VERSION 5.7 ;
  NOWIREEXTENSIONATPIN ON ;
  DIVIDERCHAR "/" ;
  BUSBITCHARS "[]" ;
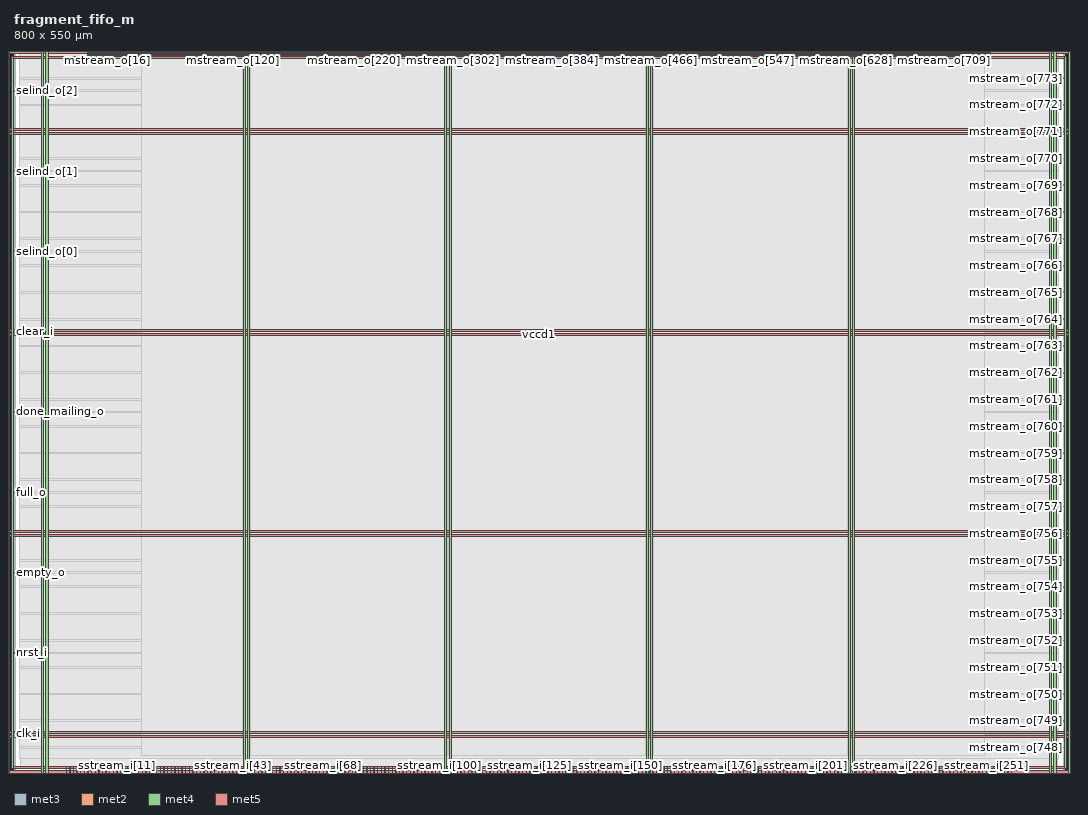
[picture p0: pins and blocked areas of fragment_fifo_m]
MACRO fragment_fifo_m
  CLASS BLOCK ;
  FOREIGN fragment_fifo_m ;
  ORIGIN 0.000 0.000 ;
  SIZE 800.000 BY 550.000 ;
  PIN clear_i
    DIRECTION INPUT ;
    USE SIGNAL ;
    ANTENNAGATEAREA 0.159000 ;
    PORT
      LAYER met3 ;
        RECT 0.000 335.960 4.000 336.560 ;
    END
  END clear_i
  PIN clk_i
    DIRECTION INPUT ;
    USE SIGNAL ;
    ANTENNAGATEAREA 0.852000 ;
    PORT
      LAYER met3 ;
        RECT 0.000 29.960 4.000 30.560 ;
    END
  END clk_i
  PIN done_mailing_o
    DIRECTION OUTPUT TRISTATE ;
    USE SIGNAL ;
    ANTENNADIFFAREA 0.795200 ;
    PORT
      LAYER met3 ;
        RECT 0.000 274.760 4.000 275.360 ;
    END
  END done_mailing_o
  PIN empty_o
    DIRECTION OUTPUT TRISTATE ;
    USE SIGNAL ;
    ANTENNADIFFAREA 0.795200 ;
    PORT
      LAYER met3 ;
        RECT 0.000 152.360 4.000 152.960 ;
    END
  END empty_o
  PIN full_o
    DIRECTION OUTPUT TRISTATE ;
    USE SIGNAL ;
    ANTENNADIFFAREA 0.795200 ;
    PORT
      LAYER met3 ;
        RECT 0.000 213.560 4.000 214.160 ;
    END
  END full_o
  PIN mstream_i[0]
    DIRECTION INPUT ;
    USE SIGNAL ;
    ANTENNAGATEAREA 0.159000 ;
    PORT
      LAYER met2 ;
        RECT 39.650 0.000 39.930 4.000 ;
    END
  END mstream_i[0]
  PIN mstream_i[1]
    DIRECTION INPUT ;
    USE SIGNAL ;
    ANTENNAGATEAREA 0.213000 ;
    PORT
      LAYER met2 ;
        RECT 42.410 0.000 42.690 4.000 ;
    END
  END mstream_i[1]
  PIN mstream_i[2]
    DIRECTION INPUT ;
    USE SIGNAL ;
    ANTENNAGATEAREA 0.213000 ;
    PORT
      LAYER met2 ;
        RECT 45.170 0.000 45.450 4.000 ;
    END
  END mstream_i[2]
  PIN mstream_o[0]
    DIRECTION OUTPUT TRISTATE ;
    USE SIGNAL ;
    ANTENNADIFFAREA 0.795200 ;
    PORT
      LAYER met2 ;
        RECT 56.210 546.000 56.490 550.000 ;
    END
  END mstream_o[0]
  PIN mstream_o[100]
    DIRECTION OUTPUT TRISTATE ;
    USE SIGNAL ;
    ANTENNADIFFAREA 0.795200 ;
    PORT
      LAYER met2 ;
        RECT 148.210 546.000 148.490 550.000 ;
    END
  END mstream_o[100]
  PIN mstream_o[101]
    DIRECTION OUTPUT TRISTATE ;
    USE SIGNAL ;
    ANTENNADIFFAREA 0.795200 ;
    PORT
      LAYER met2 ;
        RECT 149.130 546.000 149.410 550.000 ;
    END
  END mstream_o[101]
  PIN mstream_o[102]
    DIRECTION OUTPUT TRISTATE ;
    USE SIGNAL ;
    ANTENNADIFFAREA 0.795200 ;
    PORT
      LAYER met2 ;
        RECT 150.050 546.000 150.330 550.000 ;
    END
  END mstream_o[102]
  PIN mstream_o[103]
    DIRECTION OUTPUT TRISTATE ;
    USE SIGNAL ;
    ANTENNADIFFAREA 0.795200 ;
    PORT
      LAYER met2 ;
        RECT 150.970 546.000 151.250 550.000 ;
    END
  END mstream_o[103]
  PIN mstream_o[104]
    DIRECTION OUTPUT TRISTATE ;
    USE SIGNAL ;
    ANTENNADIFFAREA 0.795200 ;
    PORT
      LAYER met2 ;
        RECT 151.890 546.000 152.170 550.000 ;
    END
  END mstream_o[104]
  PIN mstream_o[105]
    DIRECTION OUTPUT TRISTATE ;
    USE SIGNAL ;
    ANTENNADIFFAREA 0.795200 ;
    PORT
      LAYER met2 ;
        RECT 152.810 546.000 153.090 550.000 ;
    END
  END mstream_o[105]
  PIN mstream_o[106]
    DIRECTION OUTPUT TRISTATE ;
    USE SIGNAL ;
    ANTENNADIFFAREA 0.795200 ;
    PORT
      LAYER met2 ;
        RECT 153.730 546.000 154.010 550.000 ;
    END
  END mstream_o[106]
  PIN mstream_o[107]
    DIRECTION OUTPUT TRISTATE ;
    USE SIGNAL ;
    ANTENNADIFFAREA 0.795200 ;
    PORT
      LAYER met2 ;
        RECT 154.650 546.000 154.930 550.000 ;
    END
  END mstream_o[107]
  PIN mstream_o[108]
    DIRECTION OUTPUT TRISTATE ;
    USE SIGNAL ;
    ANTENNADIFFAREA 0.795200 ;
    PORT
      LAYER met2 ;
        RECT 155.570 546.000 155.850 550.000 ;
    END
  END mstream_o[108]
  PIN mstream_o[109]
    DIRECTION OUTPUT TRISTATE ;
    USE SIGNAL ;
    ANTENNADIFFAREA 0.795200 ;
    PORT
      LAYER met2 ;
        RECT 156.490 546.000 156.770 550.000 ;
    END
  END mstream_o[109]
  PIN mstream_o[10]
    DIRECTION OUTPUT TRISTATE ;
    USE SIGNAL ;
    ANTENNADIFFAREA 0.795200 ;
    PORT
      LAYER met2 ;
        RECT 65.410 546.000 65.690 550.000 ;
    END
  END mstream_o[10]
  PIN mstream_o[110]
    DIRECTION OUTPUT TRISTATE ;
    USE SIGNAL ;
    ANTENNADIFFAREA 0.795200 ;
    PORT
      LAYER met2 ;
        RECT 157.410 546.000 157.690 550.000 ;
    END
  END mstream_o[110]
  PIN mstream_o[111]
    DIRECTION OUTPUT TRISTATE ;
    USE SIGNAL ;
    ANTENNADIFFAREA 0.795200 ;
    PORT
      LAYER met2 ;
        RECT 158.330 546.000 158.610 550.000 ;
    END
  END mstream_o[111]
  PIN mstream_o[112]
    DIRECTION OUTPUT TRISTATE ;
    USE SIGNAL ;
    ANTENNADIFFAREA 0.795200 ;
    PORT
      LAYER met2 ;
        RECT 159.250 546.000 159.530 550.000 ;
    END
  END mstream_o[112]
  PIN mstream_o[113]
    DIRECTION OUTPUT TRISTATE ;
    USE SIGNAL ;
    ANTENNADIFFAREA 0.795200 ;
    PORT
      LAYER met2 ;
        RECT 160.170 546.000 160.450 550.000 ;
    END
  END mstream_o[113]
  PIN mstream_o[114]
    DIRECTION OUTPUT TRISTATE ;
    USE SIGNAL ;
    ANTENNADIFFAREA 0.795200 ;
    PORT
      LAYER met2 ;
        RECT 161.090 546.000 161.370 550.000 ;
    END
  END mstream_o[114]
  PIN mstream_o[115]
    DIRECTION OUTPUT TRISTATE ;
    USE SIGNAL ;
    ANTENNADIFFAREA 0.795200 ;
    PORT
      LAYER met2 ;
        RECT 162.010 546.000 162.290 550.000 ;
    END
  END mstream_o[115]
  PIN mstream_o[116]
    DIRECTION OUTPUT TRISTATE ;
    USE SIGNAL ;
    ANTENNADIFFAREA 0.795200 ;
    PORT
      LAYER met2 ;
        RECT 162.930 546.000 163.210 550.000 ;
    END
  END mstream_o[116]
  PIN mstream_o[117]
    DIRECTION OUTPUT TRISTATE ;
    USE SIGNAL ;
    ANTENNADIFFAREA 0.795200 ;
    PORT
      LAYER met2 ;
        RECT 163.850 546.000 164.130 550.000 ;
    END
  END mstream_o[117]
  PIN mstream_o[118]
    DIRECTION OUTPUT TRISTATE ;
    USE SIGNAL ;
    ANTENNADIFFAREA 0.795200 ;
    PORT
      LAYER met2 ;
        RECT 164.770 546.000 165.050 550.000 ;
    END
  END mstream_o[118]
  PIN mstream_o[119]
    DIRECTION OUTPUT TRISTATE ;
    USE SIGNAL ;
    ANTENNADIFFAREA 0.795200 ;
    PORT
      LAYER met2 ;
        RECT 165.690 546.000 165.970 550.000 ;
    END
  END mstream_o[119]
  PIN mstream_o[11]
    DIRECTION OUTPUT TRISTATE ;
    USE SIGNAL ;
    ANTENNADIFFAREA 0.795200 ;
    PORT
      LAYER met2 ;
        RECT 66.330 546.000 66.610 550.000 ;
    END
  END mstream_o[11]
  PIN mstream_o[120]
    DIRECTION OUTPUT TRISTATE ;
    USE SIGNAL ;
    ANTENNADIFFAREA 0.795200 ;
    PORT
      LAYER met2 ;
        RECT 166.610 546.000 166.890 550.000 ;
    END
  END mstream_o[120]
  PIN mstream_o[121]
    DIRECTION OUTPUT TRISTATE ;
    USE SIGNAL ;
    ANTENNADIFFAREA 0.795200 ;
    PORT
      LAYER met2 ;
        RECT 167.530 546.000 167.810 550.000 ;
    END
  END mstream_o[121]
  PIN mstream_o[122]
    DIRECTION OUTPUT TRISTATE ;
    USE SIGNAL ;
    ANTENNADIFFAREA 0.795200 ;
    PORT
      LAYER met2 ;
        RECT 168.450 546.000 168.730 550.000 ;
    END
  END mstream_o[122]
  PIN mstream_o[123]
    DIRECTION OUTPUT TRISTATE ;
    USE SIGNAL ;
    ANTENNADIFFAREA 0.795200 ;
    PORT
      LAYER met2 ;
        RECT 169.370 546.000 169.650 550.000 ;
    END
  END mstream_o[123]
  PIN mstream_o[124]
    DIRECTION OUTPUT TRISTATE ;
    USE SIGNAL ;
    ANTENNADIFFAREA 0.795200 ;
    PORT
      LAYER met2 ;
        RECT 170.290 546.000 170.570 550.000 ;
    END
  END mstream_o[124]
  PIN mstream_o[125]
    DIRECTION OUTPUT TRISTATE ;
    USE SIGNAL ;
    ANTENNADIFFAREA 0.795200 ;
    PORT
      LAYER met2 ;
        RECT 171.210 546.000 171.490 550.000 ;
    END
  END mstream_o[125]
  PIN mstream_o[126]
    DIRECTION OUTPUT TRISTATE ;
    USE SIGNAL ;
    ANTENNADIFFAREA 0.795200 ;
    PORT
      LAYER met2 ;
        RECT 172.130 546.000 172.410 550.000 ;
    END
  END mstream_o[126]
  PIN mstream_o[127]
    DIRECTION OUTPUT TRISTATE ;
    USE SIGNAL ;
    ANTENNADIFFAREA 0.795200 ;
    PORT
      LAYER met2 ;
        RECT 173.050 546.000 173.330 550.000 ;
    END
  END mstream_o[127]
  PIN mstream_o[128]
    DIRECTION OUTPUT TRISTATE ;
    USE SIGNAL ;
    ANTENNADIFFAREA 0.795200 ;
    PORT
      LAYER met2 ;
        RECT 173.970 546.000 174.250 550.000 ;
    END
  END mstream_o[128]
  PIN mstream_o[129]
    DIRECTION OUTPUT TRISTATE ;
    USE SIGNAL ;
    ANTENNADIFFAREA 0.795200 ;
    PORT
      LAYER met2 ;
        RECT 174.890 546.000 175.170 550.000 ;
    END
  END mstream_o[129]
  PIN mstream_o[12]
    DIRECTION OUTPUT TRISTATE ;
    USE SIGNAL ;
    ANTENNADIFFAREA 0.795200 ;
    PORT
      LAYER met2 ;
        RECT 67.250 546.000 67.530 550.000 ;
    END
  END mstream_o[12]
  PIN mstream_o[130]
    DIRECTION OUTPUT TRISTATE ;
    USE SIGNAL ;
    ANTENNADIFFAREA 0.795200 ;
    PORT
      LAYER met2 ;
        RECT 175.810 546.000 176.090 550.000 ;
    END
  END mstream_o[130]
  PIN mstream_o[131]
    DIRECTION OUTPUT TRISTATE ;
    USE SIGNAL ;
    ANTENNADIFFAREA 0.795200 ;
    PORT
      LAYER met2 ;
        RECT 176.730 546.000 177.010 550.000 ;
    END
  END mstream_o[131]
  PIN mstream_o[132]
    DIRECTION OUTPUT TRISTATE ;
    USE SIGNAL ;
    ANTENNADIFFAREA 0.795200 ;
    PORT
      LAYER met2 ;
        RECT 177.650 546.000 177.930 550.000 ;
    END
  END mstream_o[132]
  PIN mstream_o[133]
    DIRECTION OUTPUT TRISTATE ;
    USE SIGNAL ;
    ANTENNADIFFAREA 0.795200 ;
    PORT
      LAYER met2 ;
        RECT 178.570 546.000 178.850 550.000 ;
    END
  END mstream_o[133]
  PIN mstream_o[134]
    DIRECTION OUTPUT TRISTATE ;
    USE SIGNAL ;
    ANTENNADIFFAREA 0.795200 ;
    PORT
      LAYER met2 ;
        RECT 179.490 546.000 179.770 550.000 ;
    END
  END mstream_o[134]
  PIN mstream_o[135]
    DIRECTION OUTPUT TRISTATE ;
    USE SIGNAL ;
    ANTENNADIFFAREA 0.795200 ;
    PORT
      LAYER met2 ;
        RECT 180.410 546.000 180.690 550.000 ;
    END
  END mstream_o[135]
  PIN mstream_o[136]
    DIRECTION OUTPUT TRISTATE ;
    USE SIGNAL ;
    ANTENNADIFFAREA 0.795200 ;
    PORT
      LAYER met2 ;
        RECT 181.330 546.000 181.610 550.000 ;
    END
  END mstream_o[136]
  PIN mstream_o[137]
    DIRECTION OUTPUT TRISTATE ;
    USE SIGNAL ;
    ANTENNADIFFAREA 0.795200 ;
    PORT
      LAYER met2 ;
        RECT 182.250 546.000 182.530 550.000 ;
    END
  END mstream_o[137]
  PIN mstream_o[138]
    DIRECTION OUTPUT TRISTATE ;
    USE SIGNAL ;
    ANTENNADIFFAREA 0.795200 ;
    PORT
      LAYER met2 ;
        RECT 183.170 546.000 183.450 550.000 ;
    END
  END mstream_o[138]
  PIN mstream_o[139]
    DIRECTION OUTPUT TRISTATE ;
    USE SIGNAL ;
    ANTENNADIFFAREA 0.795200 ;
    PORT
      LAYER met2 ;
        RECT 184.090 546.000 184.370 550.000 ;
    END
  END mstream_o[139]
  PIN mstream_o[13]
    DIRECTION OUTPUT TRISTATE ;
    USE SIGNAL ;
    ANTENNADIFFAREA 0.795200 ;
    PORT
      LAYER met2 ;
        RECT 68.170 546.000 68.450 550.000 ;
    END
  END mstream_o[13]
  PIN mstream_o[140]
    DIRECTION OUTPUT TRISTATE ;
    USE SIGNAL ;
    ANTENNADIFFAREA 0.795200 ;
    PORT
      LAYER met2 ;
        RECT 185.010 546.000 185.290 550.000 ;
    END
  END mstream_o[140]
  PIN mstream_o[141]
    DIRECTION OUTPUT TRISTATE ;
    USE SIGNAL ;
    ANTENNADIFFAREA 0.795200 ;
    PORT
      LAYER met2 ;
        RECT 185.930 546.000 186.210 550.000 ;
    END
  END mstream_o[141]
  PIN mstream_o[142]
    DIRECTION OUTPUT TRISTATE ;
    USE SIGNAL ;
    ANTENNADIFFAREA 0.795200 ;
    PORT
      LAYER met2 ;
        RECT 186.850 546.000 187.130 550.000 ;
    END
  END mstream_o[142]
  PIN mstream_o[143]
    DIRECTION OUTPUT TRISTATE ;
    USE SIGNAL ;
    ANTENNADIFFAREA 0.795200 ;
    PORT
      LAYER met2 ;
        RECT 187.770 546.000 188.050 550.000 ;
    END
  END mstream_o[143]
  PIN mstream_o[144]
    DIRECTION OUTPUT TRISTATE ;
    USE SIGNAL ;
    ANTENNADIFFAREA 0.795200 ;
    PORT
      LAYER met2 ;
        RECT 188.690 546.000 188.970 550.000 ;
    END
  END mstream_o[144]
  PIN mstream_o[145]
    DIRECTION OUTPUT TRISTATE ;
    USE SIGNAL ;
    ANTENNADIFFAREA 0.795200 ;
    PORT
      LAYER met2 ;
        RECT 189.610 546.000 189.890 550.000 ;
    END
  END mstream_o[145]
  PIN mstream_o[146]
    DIRECTION OUTPUT TRISTATE ;
    USE SIGNAL ;
    ANTENNADIFFAREA 0.795200 ;
    PORT
      LAYER met2 ;
        RECT 190.530 546.000 190.810 550.000 ;
    END
  END mstream_o[146]
  PIN mstream_o[147]
    DIRECTION OUTPUT TRISTATE ;
    USE SIGNAL ;
    ANTENNADIFFAREA 0.795200 ;
    PORT
      LAYER met2 ;
        RECT 191.450 546.000 191.730 550.000 ;
    END
  END mstream_o[147]
  PIN mstream_o[148]
    DIRECTION OUTPUT TRISTATE ;
    USE SIGNAL ;
    ANTENNADIFFAREA 0.795200 ;
    PORT
      LAYER met2 ;
        RECT 192.370 546.000 192.650 550.000 ;
    END
  END mstream_o[148]
  PIN mstream_o[149]
    DIRECTION OUTPUT TRISTATE ;
    USE SIGNAL ;
    ANTENNADIFFAREA 0.795200 ;
    PORT
      LAYER met2 ;
        RECT 193.290 546.000 193.570 550.000 ;
    END
  END mstream_o[149]
  PIN mstream_o[14]
    DIRECTION OUTPUT TRISTATE ;
    USE SIGNAL ;
    ANTENNADIFFAREA 0.795200 ;
    PORT
      LAYER met2 ;
        RECT 69.090 546.000 69.370 550.000 ;
    END
  END mstream_o[14]
  PIN mstream_o[150]
    DIRECTION OUTPUT TRISTATE ;
    USE SIGNAL ;
    ANTENNADIFFAREA 0.795200 ;
    PORT
      LAYER met2 ;
        RECT 194.210 546.000 194.490 550.000 ;
    END
  END mstream_o[150]
  PIN mstream_o[151]
    DIRECTION OUTPUT TRISTATE ;
    USE SIGNAL ;
    ANTENNADIFFAREA 0.795200 ;
    PORT
      LAYER met2 ;
        RECT 195.130 546.000 195.410 550.000 ;
    END
  END mstream_o[151]
  PIN mstream_o[152]
    DIRECTION OUTPUT TRISTATE ;
    USE SIGNAL ;
    ANTENNADIFFAREA 0.795200 ;
    PORT
      LAYER met2 ;
        RECT 196.050 546.000 196.330 550.000 ;
    END
  END mstream_o[152]
  PIN mstream_o[153]
    DIRECTION OUTPUT TRISTATE ;
    USE SIGNAL ;
    ANTENNADIFFAREA 0.795200 ;
    PORT
      LAYER met2 ;
        RECT 196.970 546.000 197.250 550.000 ;
    END
  END mstream_o[153]
  PIN mstream_o[154]
    DIRECTION OUTPUT TRISTATE ;
    USE SIGNAL ;
    ANTENNADIFFAREA 0.795200 ;
    PORT
      LAYER met2 ;
        RECT 197.890 546.000 198.170 550.000 ;
    END
  END mstream_o[154]
  PIN mstream_o[155]
    DIRECTION OUTPUT TRISTATE ;
    USE SIGNAL ;
    ANTENNADIFFAREA 0.795200 ;
    PORT
      LAYER met2 ;
        RECT 198.810 546.000 199.090 550.000 ;
    END
  END mstream_o[155]
  PIN mstream_o[156]
    DIRECTION OUTPUT TRISTATE ;
    USE SIGNAL ;
    ANTENNADIFFAREA 0.795200 ;
    PORT
      LAYER met2 ;
        RECT 199.730 546.000 200.010 550.000 ;
    END
  END mstream_o[156]
  PIN mstream_o[157]
    DIRECTION OUTPUT TRISTATE ;
    USE SIGNAL ;
    ANTENNADIFFAREA 0.795200 ;
    PORT
      LAYER met2 ;
        RECT 200.650 546.000 200.930 550.000 ;
    END
  END mstream_o[157]
  PIN mstream_o[158]
    DIRECTION OUTPUT TRISTATE ;
    USE SIGNAL ;
    ANTENNADIFFAREA 0.795200 ;
    PORT
      LAYER met2 ;
        RECT 201.570 546.000 201.850 550.000 ;
    END
  END mstream_o[158]
  PIN mstream_o[159]
    DIRECTION OUTPUT TRISTATE ;
    USE SIGNAL ;
    ANTENNADIFFAREA 0.795200 ;
    PORT
      LAYER met2 ;
        RECT 202.490 546.000 202.770 550.000 ;
    END
  END mstream_o[159]
  PIN mstream_o[15]
    DIRECTION OUTPUT TRISTATE ;
    USE SIGNAL ;
    ANTENNADIFFAREA 0.795200 ;
    PORT
      LAYER met2 ;
        RECT 70.010 546.000 70.290 550.000 ;
    END
  END mstream_o[15]
  PIN mstream_o[160]
    DIRECTION OUTPUT TRISTATE ;
    USE SIGNAL ;
    ANTENNADIFFAREA 0.795200 ;
    PORT
      LAYER met2 ;
        RECT 203.410 546.000 203.690 550.000 ;
    END
  END mstream_o[160]
  PIN mstream_o[161]
    DIRECTION OUTPUT TRISTATE ;
    USE SIGNAL ;
    ANTENNADIFFAREA 0.795200 ;
    PORT
      LAYER met2 ;
        RECT 204.330 546.000 204.610 550.000 ;
    END
  END mstream_o[161]
  PIN mstream_o[162]
    DIRECTION OUTPUT TRISTATE ;
    USE SIGNAL ;
    ANTENNADIFFAREA 0.795200 ;
    PORT
      LAYER met2 ;
        RECT 205.250 546.000 205.530 550.000 ;
    END
  END mstream_o[162]
  PIN mstream_o[163]
    DIRECTION OUTPUT TRISTATE ;
    USE SIGNAL ;
    ANTENNADIFFAREA 0.795200 ;
    PORT
      LAYER met2 ;
        RECT 206.170 546.000 206.450 550.000 ;
    END
  END mstream_o[163]
  PIN mstream_o[164]
    DIRECTION OUTPUT TRISTATE ;
    USE SIGNAL ;
    ANTENNADIFFAREA 0.795200 ;
    PORT
      LAYER met2 ;
        RECT 207.090 546.000 207.370 550.000 ;
    END
  END mstream_o[164]
  PIN mstream_o[165]
    DIRECTION OUTPUT TRISTATE ;
    USE SIGNAL ;
    ANTENNADIFFAREA 0.795200 ;
    PORT
      LAYER met2 ;
        RECT 208.010 546.000 208.290 550.000 ;
    END
  END mstream_o[165]
  PIN mstream_o[166]
    DIRECTION OUTPUT TRISTATE ;
    USE SIGNAL ;
    ANTENNADIFFAREA 0.795200 ;
    PORT
      LAYER met2 ;
        RECT 208.930 546.000 209.210 550.000 ;
    END
  END mstream_o[166]
  PIN mstream_o[167]
    DIRECTION OUTPUT TRISTATE ;
    USE SIGNAL ;
    ANTENNADIFFAREA 0.795200 ;
    PORT
      LAYER met2 ;
        RECT 209.850 546.000 210.130 550.000 ;
    END
  END mstream_o[167]
  PIN mstream_o[168]
    DIRECTION OUTPUT TRISTATE ;
    USE SIGNAL ;
    ANTENNADIFFAREA 0.795200 ;
    PORT
      LAYER met2 ;
        RECT 210.770 546.000 211.050 550.000 ;
    END
  END mstream_o[168]
  PIN mstream_o[169]
    DIRECTION OUTPUT TRISTATE ;
    USE SIGNAL ;
    ANTENNADIFFAREA 0.795200 ;
    PORT
      LAYER met2 ;
        RECT 211.690 546.000 211.970 550.000 ;
    END
  END mstream_o[169]
  PIN mstream_o[16]
    DIRECTION OUTPUT TRISTATE ;
    USE SIGNAL ;
    ANTENNADIFFAREA 0.795200 ;
    PORT
      LAYER met2 ;
        RECT 70.930 546.000 71.210 550.000 ;
    END
  END mstream_o[16]
  PIN mstream_o[170]
    DIRECTION OUTPUT TRISTATE ;
    USE SIGNAL ;
    ANTENNADIFFAREA 0.795200 ;
    PORT
      LAYER met2 ;
        RECT 212.610 546.000 212.890 550.000 ;
    END
  END mstream_o[170]
  PIN mstream_o[171]
    DIRECTION OUTPUT TRISTATE ;
    USE SIGNAL ;
    ANTENNADIFFAREA 0.795200 ;
    PORT
      LAYER met2 ;
        RECT 213.530 546.000 213.810 550.000 ;
    END
  END mstream_o[171]
  PIN mstream_o[172]
    DIRECTION OUTPUT TRISTATE ;
    USE SIGNAL ;
    ANTENNADIFFAREA 0.795200 ;
    PORT
      LAYER met2 ;
        RECT 214.450 546.000 214.730 550.000 ;
    END
  END mstream_o[172]
  PIN mstream_o[173]
    DIRECTION OUTPUT TRISTATE ;
    USE SIGNAL ;
    ANTENNADIFFAREA 0.795200 ;
    PORT
      LAYER met2 ;
        RECT 215.370 546.000 215.650 550.000 ;
    END
  END mstream_o[173]
  PIN mstream_o[174]
    DIRECTION OUTPUT TRISTATE ;
    USE SIGNAL ;
    ANTENNADIFFAREA 0.795200 ;
    PORT
      LAYER met2 ;
        RECT 216.290 546.000 216.570 550.000 ;
    END
  END mstream_o[174]
  PIN mstream_o[175]
    DIRECTION OUTPUT TRISTATE ;
    USE SIGNAL ;
    ANTENNADIFFAREA 0.795200 ;
    PORT
      LAYER met2 ;
        RECT 217.210 546.000 217.490 550.000 ;
    END
  END mstream_o[175]
  PIN mstream_o[176]
    DIRECTION OUTPUT TRISTATE ;
    USE SIGNAL ;
    ANTENNADIFFAREA 0.795200 ;
    PORT
      LAYER met2 ;
        RECT 218.130 546.000 218.410 550.000 ;
    END
  END mstream_o[176]
  PIN mstream_o[177]
    DIRECTION OUTPUT TRISTATE ;
    USE SIGNAL ;
    ANTENNADIFFAREA 0.795200 ;
    PORT
      LAYER met2 ;
        RECT 219.050 546.000 219.330 550.000 ;
    END
  END mstream_o[177]
  PIN mstream_o[178]
    DIRECTION OUTPUT TRISTATE ;
    USE SIGNAL ;
    ANTENNADIFFAREA 0.795200 ;
    PORT
      LAYER met2 ;
        RECT 219.970 546.000 220.250 550.000 ;
    END
  END mstream_o[178]
  PIN mstream_o[179]
    DIRECTION OUTPUT TRISTATE ;
    USE SIGNAL ;
    ANTENNADIFFAREA 0.795200 ;
    PORT
      LAYER met2 ;
        RECT 220.890 546.000 221.170 550.000 ;
    END
  END mstream_o[179]
  PIN mstream_o[17]
    DIRECTION OUTPUT TRISTATE ;
    USE SIGNAL ;
    ANTENNADIFFAREA 0.795200 ;
    PORT
      LAYER met2 ;
        RECT 71.850 546.000 72.130 550.000 ;
    END
  END mstream_o[17]
  PIN mstream_o[180]
    DIRECTION OUTPUT TRISTATE ;
    USE SIGNAL ;
    ANTENNADIFFAREA 0.795200 ;
    PORT
      LAYER met2 ;
        RECT 221.810 546.000 222.090 550.000 ;
    END
  END mstream_o[180]
  PIN mstream_o[181]
    DIRECTION OUTPUT TRISTATE ;
    USE SIGNAL ;
    ANTENNADIFFAREA 0.795200 ;
    PORT
      LAYER met2 ;
        RECT 222.730 546.000 223.010 550.000 ;
    END
  END mstream_o[181]
  PIN mstream_o[182]
    DIRECTION OUTPUT TRISTATE ;
    USE SIGNAL ;
    ANTENNADIFFAREA 0.795200 ;
    PORT
      LAYER met2 ;
        RECT 223.650 546.000 223.930 550.000 ;
    END
  END mstream_o[182]
  PIN mstream_o[183]
    DIRECTION OUTPUT TRISTATE ;
    USE SIGNAL ;
    ANTENNADIFFAREA 0.795200 ;
    PORT
      LAYER met2 ;
        RECT 224.570 546.000 224.850 550.000 ;
    END
  END mstream_o[183]
  PIN mstream_o[184]
    DIRECTION OUTPUT TRISTATE ;
    USE SIGNAL ;
    ANTENNADIFFAREA 0.795200 ;
    PORT
      LAYER met2 ;
        RECT 225.490 546.000 225.770 550.000 ;
    END
  END mstream_o[184]
  PIN mstream_o[185]
    DIRECTION OUTPUT TRISTATE ;
    USE SIGNAL ;
    ANTENNADIFFAREA 0.795200 ;
    PORT
      LAYER met2 ;
        RECT 226.410 546.000 226.690 550.000 ;
    END
  END mstream_o[185]
  PIN mstream_o[186]
    DIRECTION OUTPUT TRISTATE ;
    USE SIGNAL ;
    ANTENNADIFFAREA 0.795200 ;
    PORT
      LAYER met2 ;
        RECT 227.330 546.000 227.610 550.000 ;
    END
  END mstream_o[186]
  PIN mstream_o[187]
    DIRECTION OUTPUT TRISTATE ;
    USE SIGNAL ;
    ANTENNADIFFAREA 0.795200 ;
    PORT
      LAYER met2 ;
        RECT 228.250 546.000 228.530 550.000 ;
    END
  END mstream_o[187]
  PIN mstream_o[188]
    DIRECTION OUTPUT TRISTATE ;
    USE SIGNAL ;
    ANTENNADIFFAREA 0.795200 ;
    PORT
      LAYER met2 ;
        RECT 229.170 546.000 229.450 550.000 ;
    END
  END mstream_o[188]
  PIN mstream_o[189]
    DIRECTION OUTPUT TRISTATE ;
    USE SIGNAL ;
    ANTENNADIFFAREA 0.795200 ;
    PORT
      LAYER met2 ;
        RECT 230.090 546.000 230.370 550.000 ;
    END
  END mstream_o[189]
  PIN mstream_o[18]
    DIRECTION OUTPUT TRISTATE ;
    USE SIGNAL ;
    ANTENNADIFFAREA 0.795200 ;
    PORT
      LAYER met2 ;
        RECT 72.770 546.000 73.050 550.000 ;
    END
  END mstream_o[18]
  PIN mstream_o[190]
    DIRECTION OUTPUT TRISTATE ;
    USE SIGNAL ;
    ANTENNADIFFAREA 0.795200 ;
    PORT
      LAYER met2 ;
        RECT 231.010 546.000 231.290 550.000 ;
    END
  END mstream_o[190]
  PIN mstream_o[191]
    DIRECTION OUTPUT TRISTATE ;
    USE SIGNAL ;
    ANTENNADIFFAREA 0.795200 ;
    PORT
      LAYER met2 ;
        RECT 231.930 546.000 232.210 550.000 ;
    END
  END mstream_o[191]
  PIN mstream_o[192]
    DIRECTION OUTPUT TRISTATE ;
    USE SIGNAL ;
    ANTENNADIFFAREA 0.795200 ;
    PORT
      LAYER met2 ;
        RECT 232.850 546.000 233.130 550.000 ;
    END
  END mstream_o[192]
  PIN mstream_o[193]
    DIRECTION OUTPUT TRISTATE ;
    USE SIGNAL ;
    ANTENNADIFFAREA 0.795200 ;
    PORT
      LAYER met2 ;
        RECT 233.770 546.000 234.050 550.000 ;
    END
  END mstream_o[193]
  PIN mstream_o[194]
    DIRECTION OUTPUT TRISTATE ;
    USE SIGNAL ;
    ANTENNADIFFAREA 0.795200 ;
    PORT
      LAYER met2 ;
        RECT 234.690 546.000 234.970 550.000 ;
    END
  END mstream_o[194]
  PIN mstream_o[195]
    DIRECTION OUTPUT TRISTATE ;
    USE SIGNAL ;
    ANTENNADIFFAREA 0.795200 ;
    PORT
      LAYER met2 ;
        RECT 235.610 546.000 235.890 550.000 ;
    END
  END mstream_o[195]
  PIN mstream_o[196]
    DIRECTION OUTPUT TRISTATE ;
    USE SIGNAL ;
    ANTENNADIFFAREA 0.795200 ;
    PORT
      LAYER met2 ;
        RECT 236.530 546.000 236.810 550.000 ;
    END
  END mstream_o[196]
  PIN mstream_o[197]
    DIRECTION OUTPUT TRISTATE ;
    USE SIGNAL ;
    ANTENNADIFFAREA 0.795200 ;
    PORT
      LAYER met2 ;
        RECT 237.450 546.000 237.730 550.000 ;
    END
  END mstream_o[197]
  PIN mstream_o[198]
    DIRECTION OUTPUT TRISTATE ;
    USE SIGNAL ;
    ANTENNADIFFAREA 0.795200 ;
    PORT
      LAYER met2 ;
        RECT 238.370 546.000 238.650 550.000 ;
    END
  END mstream_o[198]
  PIN mstream_o[199]
    DIRECTION OUTPUT TRISTATE ;
    USE SIGNAL ;
    ANTENNADIFFAREA 0.795200 ;
    PORT
      LAYER met2 ;
        RECT 239.290 546.000 239.570 550.000 ;
    END
  END mstream_o[199]
  PIN mstream_o[19]
    DIRECTION OUTPUT TRISTATE ;
    USE SIGNAL ;
    ANTENNADIFFAREA 0.795200 ;
    PORT
      LAYER met2 ;
        RECT 73.690 546.000 73.970 550.000 ;
    END
  END mstream_o[19]
  PIN mstream_o[1]
    DIRECTION OUTPUT TRISTATE ;
    USE SIGNAL ;
    ANTENNADIFFAREA 0.795200 ;
    PORT
      LAYER met2 ;
        RECT 57.130 546.000 57.410 550.000 ;
    END
  END mstream_o[1]
  PIN mstream_o[200]
    DIRECTION OUTPUT TRISTATE ;
    USE SIGNAL ;
    ANTENNADIFFAREA 0.795200 ;
    PORT
      LAYER met2 ;
        RECT 240.210 546.000 240.490 550.000 ;
    END
  END mstream_o[200]
  PIN mstream_o[201]
    DIRECTION OUTPUT TRISTATE ;
    USE SIGNAL ;
    ANTENNADIFFAREA 0.795200 ;
    PORT
      LAYER met2 ;
        RECT 241.130 546.000 241.410 550.000 ;
    END
  END mstream_o[201]
  PIN mstream_o[202]
    DIRECTION OUTPUT TRISTATE ;
    USE SIGNAL ;
    ANTENNADIFFAREA 0.795200 ;
    PORT
      LAYER met2 ;
        RECT 242.050 546.000 242.330 550.000 ;
    END
  END mstream_o[202]
  PIN mstream_o[203]
    DIRECTION OUTPUT TRISTATE ;
    USE SIGNAL ;
    ANTENNADIFFAREA 0.795200 ;
    PORT
      LAYER met2 ;
        RECT 242.970 546.000 243.250 550.000 ;
    END
  END mstream_o[203]
  PIN mstream_o[204]
    DIRECTION OUTPUT TRISTATE ;
    USE SIGNAL ;
    ANTENNADIFFAREA 0.795200 ;
    PORT
      LAYER met2 ;
        RECT 243.890 546.000 244.170 550.000 ;
    END
  END mstream_o[204]
  PIN mstream_o[205]
    DIRECTION OUTPUT TRISTATE ;
    USE SIGNAL ;
    ANTENNADIFFAREA 0.795200 ;
    PORT
      LAYER met2 ;
        RECT 244.810 546.000 245.090 550.000 ;
    END
  END mstream_o[205]
  PIN mstream_o[206]
    DIRECTION OUTPUT TRISTATE ;
    USE SIGNAL ;
    ANTENNADIFFAREA 0.795200 ;
    PORT
      LAYER met2 ;
        RECT 245.730 546.000 246.010 550.000 ;
    END
  END mstream_o[206]
  PIN mstream_o[207]
    DIRECTION OUTPUT TRISTATE ;
    USE SIGNAL ;
    ANTENNADIFFAREA 0.795200 ;
    PORT
      LAYER met2 ;
        RECT 246.650 546.000 246.930 550.000 ;
    END
  END mstream_o[207]
  PIN mstream_o[208]
    DIRECTION OUTPUT TRISTATE ;
    USE SIGNAL ;
    ANTENNADIFFAREA 0.795200 ;
    PORT
      LAYER met2 ;
        RECT 247.570 546.000 247.850 550.000 ;
    END
  END mstream_o[208]
  PIN mstream_o[209]
    DIRECTION OUTPUT TRISTATE ;
    USE SIGNAL ;
    ANTENNADIFFAREA 0.795200 ;
    PORT
      LAYER met2 ;
        RECT 248.490 546.000 248.770 550.000 ;
    END
  END mstream_o[209]
  PIN mstream_o[20]
    DIRECTION OUTPUT TRISTATE ;
    USE SIGNAL ;
    ANTENNADIFFAREA 0.795200 ;
    PORT
      LAYER met2 ;
        RECT 74.610 546.000 74.890 550.000 ;
    END
  END mstream_o[20]
  PIN mstream_o[210]
    DIRECTION OUTPUT TRISTATE ;
    USE SIGNAL ;
    ANTENNADIFFAREA 0.795200 ;
    PORT
      LAYER met2 ;
        RECT 249.410 546.000 249.690 550.000 ;
    END
  END mstream_o[210]
  PIN mstream_o[211]
    DIRECTION OUTPUT TRISTATE ;
    USE SIGNAL ;
    ANTENNADIFFAREA 0.795200 ;
    PORT
      LAYER met2 ;
        RECT 250.330 546.000 250.610 550.000 ;
    END
  END mstream_o[211]
  PIN mstream_o[212]
    DIRECTION OUTPUT TRISTATE ;
    USE SIGNAL ;
    ANTENNADIFFAREA 0.795200 ;
    PORT
      LAYER met2 ;
        RECT 251.250 546.000 251.530 550.000 ;
    END
  END mstream_o[212]
  PIN mstream_o[213]
    DIRECTION OUTPUT TRISTATE ;
    USE SIGNAL ;
    ANTENNADIFFAREA 0.795200 ;
    PORT
      LAYER met2 ;
        RECT 252.170 546.000 252.450 550.000 ;
    END
  END mstream_o[213]
  PIN mstream_o[214]
    DIRECTION OUTPUT TRISTATE ;
    USE SIGNAL ;
    ANTENNADIFFAREA 0.795200 ;
    PORT
      LAYER met2 ;
        RECT 253.090 546.000 253.370 550.000 ;
    END
  END mstream_o[214]
  PIN mstream_o[215]
    DIRECTION OUTPUT TRISTATE ;
    USE SIGNAL ;
    ANTENNADIFFAREA 0.795200 ;
    PORT
      LAYER met2 ;
        RECT 254.010 546.000 254.290 550.000 ;
    END
  END mstream_o[215]
  PIN mstream_o[216]
    DIRECTION OUTPUT TRISTATE ;
    USE SIGNAL ;
    ANTENNADIFFAREA 0.795200 ;
    PORT
      LAYER met2 ;
        RECT 254.930 546.000 255.210 550.000 ;
    END
  END mstream_o[216]
  PIN mstream_o[217]
    DIRECTION OUTPUT TRISTATE ;
    USE SIGNAL ;
    ANTENNADIFFAREA 0.795200 ;
    PORT
      LAYER met2 ;
        RECT 255.850 546.000 256.130 550.000 ;
    END
  END mstream_o[217]
  PIN mstream_o[218]
    DIRECTION OUTPUT TRISTATE ;
    USE SIGNAL ;
    ANTENNADIFFAREA 0.795200 ;
    PORT
      LAYER met2 ;
        RECT 256.770 546.000 257.050 550.000 ;
    END
  END mstream_o[218]
  PIN mstream_o[219]
    DIRECTION OUTPUT TRISTATE ;
    USE SIGNAL ;
    ANTENNADIFFAREA 0.795200 ;
    PORT
      LAYER met2 ;
        RECT 257.690 546.000 257.970 550.000 ;
    END
  END mstream_o[219]
  PIN mstream_o[21]
    DIRECTION OUTPUT TRISTATE ;
    USE SIGNAL ;
    ANTENNADIFFAREA 0.795200 ;
    PORT
      LAYER met2 ;
        RECT 75.530 546.000 75.810 550.000 ;
    END
  END mstream_o[21]
  PIN mstream_o[220]
    DIRECTION OUTPUT TRISTATE ;
    USE SIGNAL ;
    ANTENNADIFFAREA 0.795200 ;
    PORT
      LAYER met2 ;
        RECT 258.610 546.000 258.890 550.000 ;
    END
  END mstream_o[220]
  PIN mstream_o[221]
    DIRECTION OUTPUT TRISTATE ;
    USE SIGNAL ;
    ANTENNADIFFAREA 0.795200 ;
    PORT
      LAYER met2 ;
        RECT 259.530 546.000 259.810 550.000 ;
    END
  END mstream_o[221]
  PIN mstream_o[222]
    DIRECTION OUTPUT TRISTATE ;
    USE SIGNAL ;
    ANTENNADIFFAREA 0.795200 ;
    PORT
      LAYER met2 ;
        RECT 260.450 546.000 260.730 550.000 ;
    END
  END mstream_o[222]
  PIN mstream_o[223]
    DIRECTION OUTPUT TRISTATE ;
    USE SIGNAL ;
    ANTENNADIFFAREA 0.795200 ;
    PORT
      LAYER met2 ;
        RECT 261.370 546.000 261.650 550.000 ;
    END
  END mstream_o[223]
  PIN mstream_o[224]
    DIRECTION OUTPUT TRISTATE ;
    USE SIGNAL ;
    ANTENNADIFFAREA 0.795200 ;
    PORT
      LAYER met2 ;
        RECT 262.290 546.000 262.570 550.000 ;
    END
  END mstream_o[224]
  PIN mstream_o[225]
    DIRECTION OUTPUT TRISTATE ;
    USE SIGNAL ;
    ANTENNADIFFAREA 0.795200 ;
    PORT
      LAYER met2 ;
        RECT 263.210 546.000 263.490 550.000 ;
    END
  END mstream_o[225]
  PIN mstream_o[226]
    DIRECTION OUTPUT TRISTATE ;
    USE SIGNAL ;
    ANTENNADIFFAREA 0.795200 ;
    PORT
      LAYER met2 ;
        RECT 264.130 546.000 264.410 550.000 ;
    END
  END mstream_o[226]
  PIN mstream_o[227]
    DIRECTION OUTPUT TRISTATE ;
    USE SIGNAL ;
    ANTENNADIFFAREA 0.795200 ;
    PORT
      LAYER met2 ;
        RECT 265.050 546.000 265.330 550.000 ;
    END
  END mstream_o[227]
  PIN mstream_o[228]
    DIRECTION OUTPUT TRISTATE ;
    USE SIGNAL ;
    ANTENNADIFFAREA 0.795200 ;
    PORT
      LAYER met2 ;
        RECT 265.970 546.000 266.250 550.000 ;
    END
  END mstream_o[228]
  PIN mstream_o[229]
    DIRECTION OUTPUT TRISTATE ;
    USE SIGNAL ;
    ANTENNADIFFAREA 0.795200 ;
    PORT
      LAYER met2 ;
        RECT 266.890 546.000 267.170 550.000 ;
    END
  END mstream_o[229]
  PIN mstream_o[22]
    DIRECTION OUTPUT TRISTATE ;
    USE SIGNAL ;
    ANTENNADIFFAREA 0.795200 ;
    PORT
      LAYER met2 ;
        RECT 76.450 546.000 76.730 550.000 ;
    END
  END mstream_o[22]
  PIN mstream_o[230]
    DIRECTION OUTPUT TRISTATE ;
    USE SIGNAL ;
    ANTENNADIFFAREA 0.795200 ;
    PORT
      LAYER met2 ;
        RECT 267.810 546.000 268.090 550.000 ;
    END
  END mstream_o[230]
  PIN mstream_o[231]
    DIRECTION OUTPUT TRISTATE ;
    USE SIGNAL ;
    ANTENNADIFFAREA 0.795200 ;
    PORT
      LAYER met2 ;
        RECT 268.730 546.000 269.010 550.000 ;
    END
  END mstream_o[231]
  PIN mstream_o[232]
    DIRECTION OUTPUT TRISTATE ;
    USE SIGNAL ;
    ANTENNADIFFAREA 0.795200 ;
    PORT
      LAYER met2 ;
        RECT 269.650 546.000 269.930 550.000 ;
    END
  END mstream_o[232]
  PIN mstream_o[233]
    DIRECTION OUTPUT TRISTATE ;
    USE SIGNAL ;
    ANTENNADIFFAREA 0.795200 ;
    PORT
      LAYER met2 ;
        RECT 270.570 546.000 270.850 550.000 ;
    END
  END mstream_o[233]
  PIN mstream_o[234]
    DIRECTION OUTPUT TRISTATE ;
    USE SIGNAL ;
    ANTENNADIFFAREA 0.795200 ;
    PORT
      LAYER met2 ;
        RECT 271.490 546.000 271.770 550.000 ;
    END
  END mstream_o[234]
  PIN mstream_o[235]
    DIRECTION OUTPUT TRISTATE ;
    USE SIGNAL ;
    ANTENNADIFFAREA 0.795200 ;
    PORT
      LAYER met2 ;
        RECT 272.410 546.000 272.690 550.000 ;
    END
  END mstream_o[235]
  PIN mstream_o[236]
    DIRECTION OUTPUT TRISTATE ;
    USE SIGNAL ;
    ANTENNADIFFAREA 0.795200 ;
    PORT
      LAYER met2 ;
        RECT 273.330 546.000 273.610 550.000 ;
    END
  END mstream_o[236]
  PIN mstream_o[237]
    DIRECTION OUTPUT TRISTATE ;
    USE SIGNAL ;
    ANTENNADIFFAREA 0.795200 ;
    PORT
      LAYER met2 ;
        RECT 274.250 546.000 274.530 550.000 ;
    END
  END mstream_o[237]
  PIN mstream_o[238]
    DIRECTION OUTPUT TRISTATE ;
    USE SIGNAL ;
    ANTENNADIFFAREA 0.795200 ;
    PORT
      LAYER met2 ;
        RECT 275.170 546.000 275.450 550.000 ;
    END
  END mstream_o[238]
  PIN mstream_o[239]
    DIRECTION OUTPUT TRISTATE ;
    USE SIGNAL ;
    ANTENNADIFFAREA 0.795200 ;
    PORT
      LAYER met2 ;
        RECT 276.090 546.000 276.370 550.000 ;
    END
  END mstream_o[239]
  PIN mstream_o[23]
    DIRECTION OUTPUT TRISTATE ;
    USE SIGNAL ;
    ANTENNADIFFAREA 0.795200 ;
    PORT
      LAYER met2 ;
        RECT 77.370 546.000 77.650 550.000 ;
    END
  END mstream_o[23]
  PIN mstream_o[240]
    DIRECTION OUTPUT TRISTATE ;
    USE SIGNAL ;
    ANTENNADIFFAREA 0.795200 ;
    PORT
      LAYER met2 ;
        RECT 277.010 546.000 277.290 550.000 ;
    END
  END mstream_o[240]
  PIN mstream_o[241]
    DIRECTION OUTPUT TRISTATE ;
    USE SIGNAL ;
    ANTENNADIFFAREA 0.795200 ;
    PORT
      LAYER met2 ;
        RECT 277.930 546.000 278.210 550.000 ;
    END
  END mstream_o[241]
  PIN mstream_o[242]
    DIRECTION OUTPUT TRISTATE ;
    USE SIGNAL ;
    ANTENNADIFFAREA 0.795200 ;
    PORT
      LAYER met2 ;
        RECT 278.850 546.000 279.130 550.000 ;
    END
  END mstream_o[242]
  PIN mstream_o[243]
    DIRECTION OUTPUT TRISTATE ;
    USE SIGNAL ;
    ANTENNADIFFAREA 0.795200 ;
    PORT
      LAYER met2 ;
        RECT 279.770 546.000 280.050 550.000 ;
    END
  END mstream_o[243]
  PIN mstream_o[244]
    DIRECTION OUTPUT TRISTATE ;
    USE SIGNAL ;
    ANTENNADIFFAREA 0.795200 ;
    PORT
      LAYER met2 ;
        RECT 280.690 546.000 280.970 550.000 ;
    END
  END mstream_o[244]
  PIN mstream_o[245]
    DIRECTION OUTPUT TRISTATE ;
    USE SIGNAL ;
    ANTENNADIFFAREA 0.795200 ;
    PORT
      LAYER met2 ;
        RECT 281.610 546.000 281.890 550.000 ;
    END
  END mstream_o[245]
  PIN mstream_o[246]
    DIRECTION OUTPUT TRISTATE ;
    USE SIGNAL ;
    ANTENNADIFFAREA 0.795200 ;
    PORT
      LAYER met2 ;
        RECT 282.530 546.000 282.810 550.000 ;
    END
  END mstream_o[246]
  PIN mstream_o[247]
    DIRECTION OUTPUT TRISTATE ;
    USE SIGNAL ;
    ANTENNADIFFAREA 0.795200 ;
    PORT
      LAYER met2 ;
        RECT 283.450 546.000 283.730 550.000 ;
    END
  END mstream_o[247]
  PIN mstream_o[248]
    DIRECTION OUTPUT TRISTATE ;
    USE SIGNAL ;
    ANTENNADIFFAREA 0.795200 ;
    PORT
      LAYER met2 ;
        RECT 284.370 546.000 284.650 550.000 ;
    END
  END mstream_o[248]
  PIN mstream_o[249]
    DIRECTION OUTPUT TRISTATE ;
    USE SIGNAL ;
    ANTENNADIFFAREA 0.795200 ;
    PORT
      LAYER met2 ;
        RECT 285.290 546.000 285.570 550.000 ;
    END
  END mstream_o[249]
  PIN mstream_o[24]
    DIRECTION OUTPUT TRISTATE ;
    USE SIGNAL ;
    ANTENNADIFFAREA 0.795200 ;
    PORT
      LAYER met2 ;
        RECT 78.290 546.000 78.570 550.000 ;
    END
  END mstream_o[24]
  PIN mstream_o[250]
    DIRECTION OUTPUT TRISTATE ;
    USE SIGNAL ;
    ANTENNADIFFAREA 0.795200 ;
    PORT
      LAYER met2 ;
        RECT 286.210 546.000 286.490 550.000 ;
    END
  END mstream_o[250]
  PIN mstream_o[251]
    DIRECTION OUTPUT TRISTATE ;
    USE SIGNAL ;
    ANTENNADIFFAREA 0.795200 ;
    PORT
      LAYER met2 ;
        RECT 287.130 546.000 287.410 550.000 ;
    END
  END mstream_o[251]
  PIN mstream_o[252]
    DIRECTION OUTPUT TRISTATE ;
    USE SIGNAL ;
    ANTENNADIFFAREA 0.795200 ;
    PORT
      LAYER met2 ;
        RECT 288.050 546.000 288.330 550.000 ;
    END
  END mstream_o[252]
  PIN mstream_o[253]
    DIRECTION OUTPUT TRISTATE ;
    USE SIGNAL ;
    ANTENNADIFFAREA 0.795200 ;
    PORT
      LAYER met2 ;
        RECT 288.970 546.000 289.250 550.000 ;
    END
  END mstream_o[253]
  PIN mstream_o[254]
    DIRECTION OUTPUT TRISTATE ;
    USE SIGNAL ;
    ANTENNADIFFAREA 0.795200 ;
    PORT
      LAYER met2 ;
        RECT 289.890 546.000 290.170 550.000 ;
    END
  END mstream_o[254]
  PIN mstream_o[255]
    DIRECTION OUTPUT TRISTATE ;
    USE SIGNAL ;
    ANTENNADIFFAREA 0.795200 ;
    PORT
      LAYER met2 ;
        RECT 290.810 546.000 291.090 550.000 ;
    END
  END mstream_o[255]
  PIN mstream_o[256]
    DIRECTION OUTPUT TRISTATE ;
    USE SIGNAL ;
    ANTENNADIFFAREA 0.795200 ;
    PORT
      LAYER met2 ;
        RECT 291.730 546.000 292.010 550.000 ;
    END
  END mstream_o[256]
  PIN mstream_o[257]
    DIRECTION OUTPUT TRISTATE ;
    USE SIGNAL ;
    ANTENNADIFFAREA 0.795200 ;
    PORT
      LAYER met2 ;
        RECT 292.650 546.000 292.930 550.000 ;
    END
  END mstream_o[257]
  PIN mstream_o[258]
    DIRECTION OUTPUT TRISTATE ;
    USE SIGNAL ;
    ANTENNADIFFAREA 0.795200 ;
    PORT
      LAYER met2 ;
        RECT 293.570 546.000 293.850 550.000 ;
    END
  END mstream_o[258]
  PIN mstream_o[259]
    DIRECTION OUTPUT TRISTATE ;
    USE SIGNAL ;
    ANTENNADIFFAREA 0.795200 ;
    PORT
      LAYER met2 ;
        RECT 294.490 546.000 294.770 550.000 ;
    END
  END mstream_o[259]
  PIN mstream_o[25]
    DIRECTION OUTPUT TRISTATE ;
    USE SIGNAL ;
    ANTENNADIFFAREA 0.795200 ;
    PORT
      LAYER met2 ;
        RECT 79.210 546.000 79.490 550.000 ;
    END
  END mstream_o[25]
  PIN mstream_o[260]
    DIRECTION OUTPUT TRISTATE ;
    USE SIGNAL ;
    ANTENNADIFFAREA 0.795200 ;
    PORT
      LAYER met2 ;
        RECT 295.410 546.000 295.690 550.000 ;
    END
  END mstream_o[260]
  PIN mstream_o[261]
    DIRECTION OUTPUT TRISTATE ;
    USE SIGNAL ;
    ANTENNADIFFAREA 0.795200 ;
    PORT
      LAYER met2 ;
        RECT 296.330 546.000 296.610 550.000 ;
    END
  END mstream_o[261]
  PIN mstream_o[262]
    DIRECTION OUTPUT TRISTATE ;
    USE SIGNAL ;
    ANTENNADIFFAREA 0.795200 ;
    PORT
      LAYER met2 ;
        RECT 297.250 546.000 297.530 550.000 ;
    END
  END mstream_o[262]
  PIN mstream_o[263]
    DIRECTION OUTPUT TRISTATE ;
    USE SIGNAL ;
    ANTENNADIFFAREA 0.795200 ;
    PORT
      LAYER met2 ;
        RECT 298.170 546.000 298.450 550.000 ;
    END
  END mstream_o[263]
  PIN mstream_o[264]
    DIRECTION OUTPUT TRISTATE ;
    USE SIGNAL ;
    ANTENNADIFFAREA 0.795200 ;
    PORT
      LAYER met2 ;
        RECT 299.090 546.000 299.370 550.000 ;
    END
  END mstream_o[264]
  PIN mstream_o[265]
    DIRECTION OUTPUT TRISTATE ;
    USE SIGNAL ;
    ANTENNADIFFAREA 0.795200 ;
    PORT
      LAYER met2 ;
        RECT 300.010 546.000 300.290 550.000 ;
    END
  END mstream_o[265]
  PIN mstream_o[266]
    DIRECTION OUTPUT TRISTATE ;
    USE SIGNAL ;
    ANTENNADIFFAREA 0.795200 ;
    PORT
      LAYER met2 ;
        RECT 300.930 546.000 301.210 550.000 ;
    END
  END mstream_o[266]
  PIN mstream_o[267]
    DIRECTION OUTPUT TRISTATE ;
    USE SIGNAL ;
    ANTENNADIFFAREA 0.795200 ;
    PORT
      LAYER met2 ;
        RECT 301.850 546.000 302.130 550.000 ;
    END
  END mstream_o[267]
  PIN mstream_o[268]
    DIRECTION OUTPUT TRISTATE ;
    USE SIGNAL ;
    ANTENNADIFFAREA 0.795200 ;
    PORT
      LAYER met2 ;
        RECT 302.770 546.000 303.050 550.000 ;
    END
  END mstream_o[268]
  PIN mstream_o[269]
    DIRECTION OUTPUT TRISTATE ;
    USE SIGNAL ;
    ANTENNADIFFAREA 0.795200 ;
    PORT
      LAYER met2 ;
        RECT 303.690 546.000 303.970 550.000 ;
    END
  END mstream_o[269]
  PIN mstream_o[26]
    DIRECTION OUTPUT TRISTATE ;
    USE SIGNAL ;
    ANTENNADIFFAREA 0.795200 ;
    PORT
      LAYER met2 ;
        RECT 80.130 546.000 80.410 550.000 ;
    END
  END mstream_o[26]
  PIN mstream_o[270]
    DIRECTION OUTPUT TRISTATE ;
    USE SIGNAL ;
    ANTENNADIFFAREA 0.795200 ;
    PORT
      LAYER met2 ;
        RECT 304.610 546.000 304.890 550.000 ;
    END
  END mstream_o[270]
  PIN mstream_o[271]
    DIRECTION OUTPUT TRISTATE ;
    USE SIGNAL ;
    ANTENNADIFFAREA 0.795200 ;
    PORT
      LAYER met2 ;
        RECT 305.530 546.000 305.810 550.000 ;
    END
  END mstream_o[271]
  PIN mstream_o[272]
    DIRECTION OUTPUT TRISTATE ;
    USE SIGNAL ;
    ANTENNADIFFAREA 0.795200 ;
    PORT
      LAYER met2 ;
        RECT 306.450 546.000 306.730 550.000 ;
    END
  END mstream_o[272]
  PIN mstream_o[273]
    DIRECTION OUTPUT TRISTATE ;
    USE SIGNAL ;
    ANTENNADIFFAREA 0.795200 ;
    PORT
      LAYER met2 ;
        RECT 307.370 546.000 307.650 550.000 ;
    END
  END mstream_o[273]
  PIN mstream_o[274]
    DIRECTION OUTPUT TRISTATE ;
    USE SIGNAL ;
    ANTENNADIFFAREA 0.795200 ;
    PORT
      LAYER met2 ;
        RECT 308.290 546.000 308.570 550.000 ;
    END
  END mstream_o[274]
  PIN mstream_o[275]
    DIRECTION OUTPUT TRISTATE ;
    USE SIGNAL ;
    ANTENNADIFFAREA 0.795200 ;
    PORT
      LAYER met2 ;
        RECT 309.210 546.000 309.490 550.000 ;
    END
  END mstream_o[275]
  PIN mstream_o[276]
    DIRECTION OUTPUT TRISTATE ;
    USE SIGNAL ;
    ANTENNADIFFAREA 0.795200 ;
    PORT
      LAYER met2 ;
        RECT 310.130 546.000 310.410 550.000 ;
    END
  END mstream_o[276]
  PIN mstream_o[277]
    DIRECTION OUTPUT TRISTATE ;
    USE SIGNAL ;
    ANTENNADIFFAREA 0.795200 ;
    PORT
      LAYER met2 ;
        RECT 311.050 546.000 311.330 550.000 ;
    END
  END mstream_o[277]
  PIN mstream_o[278]
    DIRECTION OUTPUT TRISTATE ;
    USE SIGNAL ;
    ANTENNADIFFAREA 0.795200 ;
    PORT
      LAYER met2 ;
        RECT 311.970 546.000 312.250 550.000 ;
    END
  END mstream_o[278]
  PIN mstream_o[279]
    DIRECTION OUTPUT TRISTATE ;
    USE SIGNAL ;
    ANTENNADIFFAREA 0.795200 ;
    PORT
      LAYER met2 ;
        RECT 312.890 546.000 313.170 550.000 ;
    END
  END mstream_o[279]
  PIN mstream_o[27]
    DIRECTION OUTPUT TRISTATE ;
    USE SIGNAL ;
    ANTENNADIFFAREA 0.795200 ;
    PORT
      LAYER met2 ;
        RECT 81.050 546.000 81.330 550.000 ;
    END
  END mstream_o[27]
  PIN mstream_o[280]
    DIRECTION OUTPUT TRISTATE ;
    USE SIGNAL ;
    ANTENNADIFFAREA 0.795200 ;
    PORT
      LAYER met2 ;
        RECT 313.810 546.000 314.090 550.000 ;
    END
  END mstream_o[280]
  PIN mstream_o[281]
    DIRECTION OUTPUT TRISTATE ;
    USE SIGNAL ;
    ANTENNADIFFAREA 0.795200 ;
    PORT
      LAYER met2 ;
        RECT 314.730 546.000 315.010 550.000 ;
    END
  END mstream_o[281]
  PIN mstream_o[282]
    DIRECTION OUTPUT TRISTATE ;
    USE SIGNAL ;
    ANTENNADIFFAREA 0.795200 ;
    PORT
      LAYER met2 ;
        RECT 315.650 546.000 315.930 550.000 ;
    END
  END mstream_o[282]
  PIN mstream_o[283]
    DIRECTION OUTPUT TRISTATE ;
    USE SIGNAL ;
    ANTENNADIFFAREA 0.795200 ;
    PORT
      LAYER met2 ;
        RECT 316.570 546.000 316.850 550.000 ;
    END
  END mstream_o[283]
  PIN mstream_o[284]
    DIRECTION OUTPUT TRISTATE ;
    USE SIGNAL ;
    ANTENNADIFFAREA 0.795200 ;
    PORT
      LAYER met2 ;
        RECT 317.490 546.000 317.770 550.000 ;
    END
  END mstream_o[284]
  PIN mstream_o[285]
    DIRECTION OUTPUT TRISTATE ;
    USE SIGNAL ;
    ANTENNADIFFAREA 0.795200 ;
    PORT
      LAYER met2 ;
        RECT 318.410 546.000 318.690 550.000 ;
    END
  END mstream_o[285]
  PIN mstream_o[286]
    DIRECTION OUTPUT TRISTATE ;
    USE SIGNAL ;
    ANTENNADIFFAREA 0.795200 ;
    PORT
      LAYER met2 ;
        RECT 319.330 546.000 319.610 550.000 ;
    END
  END mstream_o[286]
  PIN mstream_o[287]
    DIRECTION OUTPUT TRISTATE ;
    USE SIGNAL ;
    ANTENNADIFFAREA 0.795200 ;
    PORT
      LAYER met2 ;
        RECT 320.250 546.000 320.530 550.000 ;
    END
  END mstream_o[287]
  PIN mstream_o[288]
    DIRECTION OUTPUT TRISTATE ;
    USE SIGNAL ;
    ANTENNADIFFAREA 0.795200 ;
    PORT
      LAYER met2 ;
        RECT 321.170 546.000 321.450 550.000 ;
    END
  END mstream_o[288]
  PIN mstream_o[289]
    DIRECTION OUTPUT TRISTATE ;
    USE SIGNAL ;
    ANTENNADIFFAREA 0.795200 ;
    PORT
      LAYER met2 ;
        RECT 322.090 546.000 322.370 550.000 ;
    END
  END mstream_o[289]
  PIN mstream_o[28]
    DIRECTION OUTPUT TRISTATE ;
    USE SIGNAL ;
    ANTENNADIFFAREA 0.795200 ;
    PORT
      LAYER met2 ;
        RECT 81.970 546.000 82.250 550.000 ;
    END
  END mstream_o[28]
  PIN mstream_o[290]
    DIRECTION OUTPUT TRISTATE ;
    USE SIGNAL ;
    ANTENNADIFFAREA 0.795200 ;
    PORT
      LAYER met2 ;
        RECT 323.010 546.000 323.290 550.000 ;
    END
  END mstream_o[290]
  PIN mstream_o[291]
    DIRECTION OUTPUT TRISTATE ;
    USE SIGNAL ;
    ANTENNADIFFAREA 0.795200 ;
    PORT
      LAYER met2 ;
        RECT 323.930 546.000 324.210 550.000 ;
    END
  END mstream_o[291]
  PIN mstream_o[292]
    DIRECTION OUTPUT TRISTATE ;
    USE SIGNAL ;
    ANTENNADIFFAREA 0.795200 ;
    PORT
      LAYER met2 ;
        RECT 324.850 546.000 325.130 550.000 ;
    END
  END mstream_o[292]
  PIN mstream_o[293]
    DIRECTION OUTPUT TRISTATE ;
    USE SIGNAL ;
    ANTENNADIFFAREA 0.795200 ;
    PORT
      LAYER met2 ;
        RECT 325.770 546.000 326.050 550.000 ;
    END
  END mstream_o[293]
  PIN mstream_o[294]
    DIRECTION OUTPUT TRISTATE ;
    USE SIGNAL ;
    ANTENNADIFFAREA 0.795200 ;
    PORT
      LAYER met2 ;
        RECT 326.690 546.000 326.970 550.000 ;
    END
  END mstream_o[294]
  PIN mstream_o[295]
    DIRECTION OUTPUT TRISTATE ;
    USE SIGNAL ;
    ANTENNADIFFAREA 0.795200 ;
    PORT
      LAYER met2 ;
        RECT 327.610 546.000 327.890 550.000 ;
    END
  END mstream_o[295]
  PIN mstream_o[296]
    DIRECTION OUTPUT TRISTATE ;
    USE SIGNAL ;
    ANTENNADIFFAREA 0.795200 ;
    PORT
      LAYER met2 ;
        RECT 328.530 546.000 328.810 550.000 ;
    END
  END mstream_o[296]
  PIN mstream_o[297]
    DIRECTION OUTPUT TRISTATE ;
    USE SIGNAL ;
    ANTENNADIFFAREA 0.795200 ;
    PORT
      LAYER met2 ;
        RECT 329.450 546.000 329.730 550.000 ;
    END
  END mstream_o[297]
  PIN mstream_o[298]
    DIRECTION OUTPUT TRISTATE ;
    USE SIGNAL ;
    ANTENNADIFFAREA 0.795200 ;
    PORT
      LAYER met2 ;
        RECT 330.370 546.000 330.650 550.000 ;
    END
  END mstream_o[298]
  PIN mstream_o[299]
    DIRECTION OUTPUT TRISTATE ;
    USE SIGNAL ;
    ANTENNADIFFAREA 0.795200 ;
    PORT
      LAYER met2 ;
        RECT 331.290 546.000 331.570 550.000 ;
    END
  END mstream_o[299]
  PIN mstream_o[29]
    DIRECTION OUTPUT TRISTATE ;
    USE SIGNAL ;
    ANTENNADIFFAREA 0.795200 ;
    PORT
      LAYER met2 ;
        RECT 82.890 546.000 83.170 550.000 ;
    END
  END mstream_o[29]
  PIN mstream_o[2]
    DIRECTION OUTPUT TRISTATE ;
    USE SIGNAL ;
    ANTENNADIFFAREA 0.795200 ;
    PORT
      LAYER met2 ;
        RECT 58.050 546.000 58.330 550.000 ;
    END
  END mstream_o[2]
  PIN mstream_o[300]
    DIRECTION OUTPUT TRISTATE ;
    USE SIGNAL ;
    ANTENNADIFFAREA 0.795200 ;
    PORT
      LAYER met2 ;
        RECT 332.210 546.000 332.490 550.000 ;
    END
  END mstream_o[300]
  PIN mstream_o[301]
    DIRECTION OUTPUT TRISTATE ;
    USE SIGNAL ;
    ANTENNADIFFAREA 0.795200 ;
    PORT
      LAYER met2 ;
        RECT 333.130 546.000 333.410 550.000 ;
    END
  END mstream_o[301]
  PIN mstream_o[302]
    DIRECTION OUTPUT TRISTATE ;
    USE SIGNAL ;
    ANTENNADIFFAREA 0.795200 ;
    PORT
      LAYER met2 ;
        RECT 334.050 546.000 334.330 550.000 ;
    END
  END mstream_o[302]
  PIN mstream_o[303]
    DIRECTION OUTPUT TRISTATE ;
    USE SIGNAL ;
    ANTENNADIFFAREA 0.795200 ;
    PORT
      LAYER met2 ;
        RECT 334.970 546.000 335.250 550.000 ;
    END
  END mstream_o[303]
  PIN mstream_o[304]
    DIRECTION OUTPUT TRISTATE ;
    USE SIGNAL ;
    ANTENNADIFFAREA 0.795200 ;
    PORT
      LAYER met2 ;
        RECT 335.890 546.000 336.170 550.000 ;
    END
  END mstream_o[304]
  PIN mstream_o[305]
    DIRECTION OUTPUT TRISTATE ;
    USE SIGNAL ;
    ANTENNADIFFAREA 0.795200 ;
    PORT
      LAYER met2 ;
        RECT 336.810 546.000 337.090 550.000 ;
    END
  END mstream_o[305]
  PIN mstream_o[306]
    DIRECTION OUTPUT TRISTATE ;
    USE SIGNAL ;
    ANTENNADIFFAREA 0.795200 ;
    PORT
      LAYER met2 ;
        RECT 337.730 546.000 338.010 550.000 ;
    END
  END mstream_o[306]
  PIN mstream_o[307]
    DIRECTION OUTPUT TRISTATE ;
    USE SIGNAL ;
    ANTENNADIFFAREA 0.795200 ;
    PORT
      LAYER met2 ;
        RECT 338.650 546.000 338.930 550.000 ;
    END
  END mstream_o[307]
  PIN mstream_o[308]
    DIRECTION OUTPUT TRISTATE ;
    USE SIGNAL ;
    ANTENNADIFFAREA 0.795200 ;
    PORT
      LAYER met2 ;
        RECT 339.570 546.000 339.850 550.000 ;
    END
  END mstream_o[308]
  PIN mstream_o[309]
    DIRECTION OUTPUT TRISTATE ;
    USE SIGNAL ;
    ANTENNADIFFAREA 0.795200 ;
    PORT
      LAYER met2 ;
        RECT 340.490 546.000 340.770 550.000 ;
    END
  END mstream_o[309]
  PIN mstream_o[30]
    DIRECTION OUTPUT TRISTATE ;
    USE SIGNAL ;
    ANTENNADIFFAREA 0.795200 ;
    PORT
      LAYER met2 ;
        RECT 83.810 546.000 84.090 550.000 ;
    END
  END mstream_o[30]
  PIN mstream_o[310]
    DIRECTION OUTPUT TRISTATE ;
    USE SIGNAL ;
    ANTENNADIFFAREA 0.795200 ;
    PORT
      LAYER met2 ;
        RECT 341.410 546.000 341.690 550.000 ;
    END
  END mstream_o[310]
  PIN mstream_o[311]
    DIRECTION OUTPUT TRISTATE ;
    USE SIGNAL ;
    ANTENNADIFFAREA 0.795200 ;
    PORT
      LAYER met2 ;
        RECT 342.330 546.000 342.610 550.000 ;
    END
  END mstream_o[311]
  PIN mstream_o[312]
    DIRECTION OUTPUT TRISTATE ;
    USE SIGNAL ;
    ANTENNADIFFAREA 0.795200 ;
    PORT
      LAYER met2 ;
        RECT 343.250 546.000 343.530 550.000 ;
    END
  END mstream_o[312]
  PIN mstream_o[313]
    DIRECTION OUTPUT TRISTATE ;
    USE SIGNAL ;
    ANTENNADIFFAREA 0.795200 ;
    PORT
      LAYER met2 ;
        RECT 344.170 546.000 344.450 550.000 ;
    END
  END mstream_o[313]
  PIN mstream_o[314]
    DIRECTION OUTPUT TRISTATE ;
    USE SIGNAL ;
    ANTENNADIFFAREA 0.795200 ;
    PORT
      LAYER met2 ;
        RECT 345.090 546.000 345.370 550.000 ;
    END
  END mstream_o[314]
  PIN mstream_o[315]
    DIRECTION OUTPUT TRISTATE ;
    USE SIGNAL ;
    ANTENNADIFFAREA 0.795200 ;
    PORT
      LAYER met2 ;
        RECT 346.010 546.000 346.290 550.000 ;
    END
  END mstream_o[315]
  PIN mstream_o[316]
    DIRECTION OUTPUT TRISTATE ;
    USE SIGNAL ;
    ANTENNADIFFAREA 0.795200 ;
    PORT
      LAYER met2 ;
        RECT 346.930 546.000 347.210 550.000 ;
    END
  END mstream_o[316]
  PIN mstream_o[317]
    DIRECTION OUTPUT TRISTATE ;
    USE SIGNAL ;
    ANTENNADIFFAREA 0.795200 ;
    PORT
      LAYER met2 ;
        RECT 347.850 546.000 348.130 550.000 ;
    END
  END mstream_o[317]
  PIN mstream_o[318]
    DIRECTION OUTPUT TRISTATE ;
    USE SIGNAL ;
    ANTENNADIFFAREA 0.795200 ;
    PORT
      LAYER met2 ;
        RECT 348.770 546.000 349.050 550.000 ;
    END
  END mstream_o[318]
  PIN mstream_o[319]
    DIRECTION OUTPUT TRISTATE ;
    USE SIGNAL ;
    ANTENNADIFFAREA 0.795200 ;
    PORT
      LAYER met2 ;
        RECT 349.690 546.000 349.970 550.000 ;
    END
  END mstream_o[319]
  PIN mstream_o[31]
    DIRECTION OUTPUT TRISTATE ;
    USE SIGNAL ;
    ANTENNADIFFAREA 0.795200 ;
    PORT
      LAYER met2 ;
        RECT 84.730 546.000 85.010 550.000 ;
    END
  END mstream_o[31]
  PIN mstream_o[320]
    DIRECTION OUTPUT TRISTATE ;
    USE SIGNAL ;
    ANTENNADIFFAREA 0.795200 ;
    PORT
      LAYER met2 ;
        RECT 350.610 546.000 350.890 550.000 ;
    END
  END mstream_o[320]
  PIN mstream_o[321]
    DIRECTION OUTPUT TRISTATE ;
    USE SIGNAL ;
    ANTENNADIFFAREA 0.795200 ;
    PORT
      LAYER met2 ;
        RECT 351.530 546.000 351.810 550.000 ;
    END
  END mstream_o[321]
  PIN mstream_o[322]
    DIRECTION OUTPUT TRISTATE ;
    USE SIGNAL ;
    ANTENNADIFFAREA 0.795200 ;
    PORT
      LAYER met2 ;
        RECT 352.450 546.000 352.730 550.000 ;
    END
  END mstream_o[322]
  PIN mstream_o[323]
    DIRECTION OUTPUT TRISTATE ;
    USE SIGNAL ;
    ANTENNADIFFAREA 0.795200 ;
    PORT
      LAYER met2 ;
        RECT 353.370 546.000 353.650 550.000 ;
    END
  END mstream_o[323]
  PIN mstream_o[324]
    DIRECTION OUTPUT TRISTATE ;
    USE SIGNAL ;
    ANTENNADIFFAREA 0.795200 ;
    PORT
      LAYER met2 ;
        RECT 354.290 546.000 354.570 550.000 ;
    END
  END mstream_o[324]
  PIN mstream_o[325]
    DIRECTION OUTPUT TRISTATE ;
    USE SIGNAL ;
    ANTENNADIFFAREA 0.795200 ;
    PORT
      LAYER met2 ;
        RECT 355.210 546.000 355.490 550.000 ;
    END
  END mstream_o[325]
  PIN mstream_o[326]
    DIRECTION OUTPUT TRISTATE ;
    USE SIGNAL ;
    ANTENNADIFFAREA 0.795200 ;
    PORT
      LAYER met2 ;
        RECT 356.130 546.000 356.410 550.000 ;
    END
  END mstream_o[326]
  PIN mstream_o[327]
    DIRECTION OUTPUT TRISTATE ;
    USE SIGNAL ;
    ANTENNADIFFAREA 0.795200 ;
    PORT
      LAYER met2 ;
        RECT 357.050 546.000 357.330 550.000 ;
    END
  END mstream_o[327]
  PIN mstream_o[328]
    DIRECTION OUTPUT TRISTATE ;
    USE SIGNAL ;
    ANTENNADIFFAREA 0.795200 ;
    PORT
      LAYER met2 ;
        RECT 357.970 546.000 358.250 550.000 ;
    END
  END mstream_o[328]
  PIN mstream_o[329]
    DIRECTION OUTPUT TRISTATE ;
    USE SIGNAL ;
    ANTENNADIFFAREA 0.795200 ;
    PORT
      LAYER met2 ;
        RECT 358.890 546.000 359.170 550.000 ;
    END
  END mstream_o[329]
  PIN mstream_o[32]
    DIRECTION OUTPUT TRISTATE ;
    USE SIGNAL ;
    ANTENNADIFFAREA 0.795200 ;
    PORT
      LAYER met2 ;
        RECT 85.650 546.000 85.930 550.000 ;
    END
  END mstream_o[32]
  PIN mstream_o[330]
    DIRECTION OUTPUT TRISTATE ;
    USE SIGNAL ;
    ANTENNADIFFAREA 0.795200 ;
    PORT
      LAYER met2 ;
        RECT 359.810 546.000 360.090 550.000 ;
    END
  END mstream_o[330]
  PIN mstream_o[331]
    DIRECTION OUTPUT TRISTATE ;
    USE SIGNAL ;
    ANTENNADIFFAREA 0.795200 ;
    PORT
      LAYER met2 ;
        RECT 360.730 546.000 361.010 550.000 ;
    END
  END mstream_o[331]
  PIN mstream_o[332]
    DIRECTION OUTPUT TRISTATE ;
    USE SIGNAL ;
    ANTENNADIFFAREA 0.795200 ;
    PORT
      LAYER met2 ;
        RECT 361.650 546.000 361.930 550.000 ;
    END
  END mstream_o[332]
  PIN mstream_o[333]
    DIRECTION OUTPUT TRISTATE ;
    USE SIGNAL ;
    ANTENNADIFFAREA 0.795200 ;
    PORT
      LAYER met2 ;
        RECT 362.570 546.000 362.850 550.000 ;
    END
  END mstream_o[333]
  PIN mstream_o[334]
    DIRECTION OUTPUT TRISTATE ;
    USE SIGNAL ;
    ANTENNADIFFAREA 0.795200 ;
    PORT
      LAYER met2 ;
        RECT 363.490 546.000 363.770 550.000 ;
    END
  END mstream_o[334]
  PIN mstream_o[335]
    DIRECTION OUTPUT TRISTATE ;
    USE SIGNAL ;
    ANTENNADIFFAREA 0.795200 ;
    PORT
      LAYER met2 ;
        RECT 364.410 546.000 364.690 550.000 ;
    END
  END mstream_o[335]
  PIN mstream_o[336]
    DIRECTION OUTPUT TRISTATE ;
    USE SIGNAL ;
    ANTENNADIFFAREA 0.795200 ;
    PORT
      LAYER met2 ;
        RECT 365.330 546.000 365.610 550.000 ;
    END
  END mstream_o[336]
  PIN mstream_o[337]
    DIRECTION OUTPUT TRISTATE ;
    USE SIGNAL ;
    ANTENNADIFFAREA 0.795200 ;
    PORT
      LAYER met2 ;
        RECT 366.250 546.000 366.530 550.000 ;
    END
  END mstream_o[337]
  PIN mstream_o[338]
    DIRECTION OUTPUT TRISTATE ;
    USE SIGNAL ;
    ANTENNADIFFAREA 0.795200 ;
    PORT
      LAYER met2 ;
        RECT 367.170 546.000 367.450 550.000 ;
    END
  END mstream_o[338]
  PIN mstream_o[339]
    DIRECTION OUTPUT TRISTATE ;
    USE SIGNAL ;
    ANTENNADIFFAREA 0.795200 ;
    PORT
      LAYER met2 ;
        RECT 368.090 546.000 368.370 550.000 ;
    END
  END mstream_o[339]
  PIN mstream_o[33]
    DIRECTION OUTPUT TRISTATE ;
    USE SIGNAL ;
    ANTENNADIFFAREA 0.795200 ;
    PORT
      LAYER met2 ;
        RECT 86.570 546.000 86.850 550.000 ;
    END
  END mstream_o[33]
  PIN mstream_o[340]
    DIRECTION OUTPUT TRISTATE ;
    USE SIGNAL ;
    ANTENNADIFFAREA 0.795200 ;
    PORT
      LAYER met2 ;
        RECT 369.010 546.000 369.290 550.000 ;
    END
  END mstream_o[340]
  PIN mstream_o[341]
    DIRECTION OUTPUT TRISTATE ;
    USE SIGNAL ;
    ANTENNADIFFAREA 0.795200 ;
    PORT
      LAYER met2 ;
        RECT 369.930 546.000 370.210 550.000 ;
    END
  END mstream_o[341]
  PIN mstream_o[342]
    DIRECTION OUTPUT TRISTATE ;
    USE SIGNAL ;
    ANTENNADIFFAREA 0.795200 ;
    PORT
      LAYER met2 ;
        RECT 370.850 546.000 371.130 550.000 ;
    END
  END mstream_o[342]
  PIN mstream_o[343]
    DIRECTION OUTPUT TRISTATE ;
    USE SIGNAL ;
    ANTENNADIFFAREA 0.795200 ;
    PORT
      LAYER met2 ;
        RECT 371.770 546.000 372.050 550.000 ;
    END
  END mstream_o[343]
  PIN mstream_o[344]
    DIRECTION OUTPUT TRISTATE ;
    USE SIGNAL ;
    ANTENNADIFFAREA 0.795200 ;
    PORT
      LAYER met2 ;
        RECT 372.690 546.000 372.970 550.000 ;
    END
  END mstream_o[344]
  PIN mstream_o[345]
    DIRECTION OUTPUT TRISTATE ;
    USE SIGNAL ;
    ANTENNADIFFAREA 0.795200 ;
    PORT
      LAYER met2 ;
        RECT 373.610 546.000 373.890 550.000 ;
    END
  END mstream_o[345]
  PIN mstream_o[346]
    DIRECTION OUTPUT TRISTATE ;
    USE SIGNAL ;
    ANTENNADIFFAREA 0.795200 ;
    PORT
      LAYER met2 ;
        RECT 374.530 546.000 374.810 550.000 ;
    END
  END mstream_o[346]
  PIN mstream_o[347]
    DIRECTION OUTPUT TRISTATE ;
    USE SIGNAL ;
    ANTENNADIFFAREA 0.795200 ;
    PORT
      LAYER met2 ;
        RECT 375.450 546.000 375.730 550.000 ;
    END
  END mstream_o[347]
  PIN mstream_o[348]
    DIRECTION OUTPUT TRISTATE ;
    USE SIGNAL ;
    ANTENNADIFFAREA 0.795200 ;
    PORT
      LAYER met2 ;
        RECT 376.370 546.000 376.650 550.000 ;
    END
  END mstream_o[348]
  PIN mstream_o[349]
    DIRECTION OUTPUT TRISTATE ;
    USE SIGNAL ;
    ANTENNADIFFAREA 0.795200 ;
    PORT
      LAYER met2 ;
        RECT 377.290 546.000 377.570 550.000 ;
    END
  END mstream_o[349]
  PIN mstream_o[34]
    DIRECTION OUTPUT TRISTATE ;
    USE SIGNAL ;
    ANTENNADIFFAREA 0.795200 ;
    PORT
      LAYER met2 ;
        RECT 87.490 546.000 87.770 550.000 ;
    END
  END mstream_o[34]
  PIN mstream_o[350]
    DIRECTION OUTPUT TRISTATE ;
    USE SIGNAL ;
    ANTENNADIFFAREA 0.795200 ;
    PORT
      LAYER met2 ;
        RECT 378.210 546.000 378.490 550.000 ;
    END
  END mstream_o[350]
  PIN mstream_o[351]
    DIRECTION OUTPUT TRISTATE ;
    USE SIGNAL ;
    ANTENNADIFFAREA 0.795200 ;
    PORT
      LAYER met2 ;
        RECT 379.130 546.000 379.410 550.000 ;
    END
  END mstream_o[351]
  PIN mstream_o[352]
    DIRECTION OUTPUT TRISTATE ;
    USE SIGNAL ;
    ANTENNADIFFAREA 0.795200 ;
    PORT
      LAYER met2 ;
        RECT 380.050 546.000 380.330 550.000 ;
    END
  END mstream_o[352]
  PIN mstream_o[353]
    DIRECTION OUTPUT TRISTATE ;
    USE SIGNAL ;
    ANTENNADIFFAREA 0.795200 ;
    PORT
      LAYER met2 ;
        RECT 380.970 546.000 381.250 550.000 ;
    END
  END mstream_o[353]
  PIN mstream_o[354]
    DIRECTION OUTPUT TRISTATE ;
    USE SIGNAL ;
    ANTENNADIFFAREA 0.795200 ;
    PORT
      LAYER met2 ;
        RECT 381.890 546.000 382.170 550.000 ;
    END
  END mstream_o[354]
  PIN mstream_o[355]
    DIRECTION OUTPUT TRISTATE ;
    USE SIGNAL ;
    ANTENNADIFFAREA 0.795200 ;
    PORT
      LAYER met2 ;
        RECT 382.810 546.000 383.090 550.000 ;
    END
  END mstream_o[355]
  PIN mstream_o[356]
    DIRECTION OUTPUT TRISTATE ;
    USE SIGNAL ;
    ANTENNADIFFAREA 0.795200 ;
    PORT
      LAYER met2 ;
        RECT 383.730 546.000 384.010 550.000 ;
    END
  END mstream_o[356]
  PIN mstream_o[357]
    DIRECTION OUTPUT TRISTATE ;
    USE SIGNAL ;
    ANTENNADIFFAREA 0.795200 ;
    PORT
      LAYER met2 ;
        RECT 384.650 546.000 384.930 550.000 ;
    END
  END mstream_o[357]
  PIN mstream_o[358]
    DIRECTION OUTPUT TRISTATE ;
    USE SIGNAL ;
    ANTENNADIFFAREA 0.795200 ;
    PORT
      LAYER met2 ;
        RECT 385.570 546.000 385.850 550.000 ;
    END
  END mstream_o[358]
  PIN mstream_o[359]
    DIRECTION OUTPUT TRISTATE ;
    USE SIGNAL ;
    ANTENNADIFFAREA 0.795200 ;
    PORT
      LAYER met2 ;
        RECT 386.490 546.000 386.770 550.000 ;
    END
  END mstream_o[359]
  PIN mstream_o[35]
    DIRECTION OUTPUT TRISTATE ;
    USE SIGNAL ;
    ANTENNADIFFAREA 0.795200 ;
    PORT
      LAYER met2 ;
        RECT 88.410 546.000 88.690 550.000 ;
    END
  END mstream_o[35]
  PIN mstream_o[360]
    DIRECTION OUTPUT TRISTATE ;
    USE SIGNAL ;
    ANTENNADIFFAREA 0.795200 ;
    PORT
      LAYER met2 ;
        RECT 387.410 546.000 387.690 550.000 ;
    END
  END mstream_o[360]
  PIN mstream_o[361]
    DIRECTION OUTPUT TRISTATE ;
    USE SIGNAL ;
    ANTENNADIFFAREA 0.795200 ;
    PORT
      LAYER met2 ;
        RECT 388.330 546.000 388.610 550.000 ;
    END
  END mstream_o[361]
  PIN mstream_o[362]
    DIRECTION OUTPUT TRISTATE ;
    USE SIGNAL ;
    ANTENNADIFFAREA 0.795200 ;
    PORT
      LAYER met2 ;
        RECT 389.250 546.000 389.530 550.000 ;
    END
  END mstream_o[362]
  PIN mstream_o[363]
    DIRECTION OUTPUT TRISTATE ;
    USE SIGNAL ;
    ANTENNADIFFAREA 0.795200 ;
    PORT
      LAYER met2 ;
        RECT 390.170 546.000 390.450 550.000 ;
    END
  END mstream_o[363]
  PIN mstream_o[364]
    DIRECTION OUTPUT TRISTATE ;
    USE SIGNAL ;
    ANTENNADIFFAREA 0.795200 ;
    PORT
      LAYER met2 ;
        RECT 391.090 546.000 391.370 550.000 ;
    END
  END mstream_o[364]
  PIN mstream_o[365]
    DIRECTION OUTPUT TRISTATE ;
    USE SIGNAL ;
    ANTENNADIFFAREA 0.795200 ;
    PORT
      LAYER met2 ;
        RECT 392.010 546.000 392.290 550.000 ;
    END
  END mstream_o[365]
  PIN mstream_o[366]
    DIRECTION OUTPUT TRISTATE ;
    USE SIGNAL ;
    ANTENNADIFFAREA 0.795200 ;
    PORT
      LAYER met2 ;
        RECT 392.930 546.000 393.210 550.000 ;
    END
  END mstream_o[366]
  PIN mstream_o[367]
    DIRECTION OUTPUT TRISTATE ;
    USE SIGNAL ;
    ANTENNADIFFAREA 0.795200 ;
    PORT
      LAYER met2 ;
        RECT 393.850 546.000 394.130 550.000 ;
    END
  END mstream_o[367]
  PIN mstream_o[368]
    DIRECTION OUTPUT TRISTATE ;
    USE SIGNAL ;
    ANTENNADIFFAREA 0.795200 ;
    PORT
      LAYER met2 ;
        RECT 394.770 546.000 395.050 550.000 ;
    END
  END mstream_o[368]
  PIN mstream_o[369]
    DIRECTION OUTPUT TRISTATE ;
    USE SIGNAL ;
    ANTENNADIFFAREA 0.795200 ;
    PORT
      LAYER met2 ;
        RECT 395.690 546.000 395.970 550.000 ;
    END
  END mstream_o[369]
  PIN mstream_o[36]
    DIRECTION OUTPUT TRISTATE ;
    USE SIGNAL ;
    ANTENNADIFFAREA 0.795200 ;
    PORT
      LAYER met2 ;
        RECT 89.330 546.000 89.610 550.000 ;
    END
  END mstream_o[36]
  PIN mstream_o[370]
    DIRECTION OUTPUT TRISTATE ;
    USE SIGNAL ;
    ANTENNADIFFAREA 0.795200 ;
    PORT
      LAYER met2 ;
        RECT 396.610 546.000 396.890 550.000 ;
    END
  END mstream_o[370]
  PIN mstream_o[371]
    DIRECTION OUTPUT TRISTATE ;
    USE SIGNAL ;
    ANTENNADIFFAREA 0.795200 ;
    PORT
      LAYER met2 ;
        RECT 397.530 546.000 397.810 550.000 ;
    END
  END mstream_o[371]
  PIN mstream_o[372]
    DIRECTION OUTPUT TRISTATE ;
    USE SIGNAL ;
    ANTENNADIFFAREA 0.795200 ;
    PORT
      LAYER met2 ;
        RECT 398.450 546.000 398.730 550.000 ;
    END
  END mstream_o[372]
  PIN mstream_o[373]
    DIRECTION OUTPUT TRISTATE ;
    USE SIGNAL ;
    ANTENNADIFFAREA 0.795200 ;
    PORT
      LAYER met2 ;
        RECT 399.370 546.000 399.650 550.000 ;
    END
  END mstream_o[373]
  PIN mstream_o[374]
    DIRECTION OUTPUT TRISTATE ;
    USE SIGNAL ;
    ANTENNADIFFAREA 0.795200 ;
    PORT
      LAYER met2 ;
        RECT 400.290 546.000 400.570 550.000 ;
    END
  END mstream_o[374]
  PIN mstream_o[375]
    DIRECTION OUTPUT TRISTATE ;
    USE SIGNAL ;
    ANTENNADIFFAREA 0.795200 ;
    PORT
      LAYER met2 ;
        RECT 401.210 546.000 401.490 550.000 ;
    END
  END mstream_o[375]
  PIN mstream_o[376]
    DIRECTION OUTPUT TRISTATE ;
    USE SIGNAL ;
    ANTENNADIFFAREA 0.795200 ;
    PORT
      LAYER met2 ;
        RECT 402.130 546.000 402.410 550.000 ;
    END
  END mstream_o[376]
  PIN mstream_o[377]
    DIRECTION OUTPUT TRISTATE ;
    USE SIGNAL ;
    ANTENNADIFFAREA 0.795200 ;
    PORT
      LAYER met2 ;
        RECT 403.050 546.000 403.330 550.000 ;
    END
  END mstream_o[377]
  PIN mstream_o[378]
    DIRECTION OUTPUT TRISTATE ;
    USE SIGNAL ;
    ANTENNADIFFAREA 0.795200 ;
    PORT
      LAYER met2 ;
        RECT 403.970 546.000 404.250 550.000 ;
    END
  END mstream_o[378]
  PIN mstream_o[379]
    DIRECTION OUTPUT TRISTATE ;
    USE SIGNAL ;
    ANTENNADIFFAREA 0.795200 ;
    PORT
      LAYER met2 ;
        RECT 404.890 546.000 405.170 550.000 ;
    END
  END mstream_o[379]
  PIN mstream_o[37]
    DIRECTION OUTPUT TRISTATE ;
    USE SIGNAL ;
    ANTENNADIFFAREA 0.795200 ;
    PORT
      LAYER met2 ;
        RECT 90.250 546.000 90.530 550.000 ;
    END
  END mstream_o[37]
  PIN mstream_o[380]
    DIRECTION OUTPUT TRISTATE ;
    USE SIGNAL ;
    ANTENNADIFFAREA 0.795200 ;
    PORT
      LAYER met2 ;
        RECT 405.810 546.000 406.090 550.000 ;
    END
  END mstream_o[380]
  PIN mstream_o[381]
    DIRECTION OUTPUT TRISTATE ;
    USE SIGNAL ;
    ANTENNADIFFAREA 0.795200 ;
    PORT
      LAYER met2 ;
        RECT 406.730 546.000 407.010 550.000 ;
    END
  END mstream_o[381]
  PIN mstream_o[382]
    DIRECTION OUTPUT TRISTATE ;
    USE SIGNAL ;
    ANTENNADIFFAREA 0.795200 ;
    PORT
      LAYER met2 ;
        RECT 407.650 546.000 407.930 550.000 ;
    END
  END mstream_o[382]
  PIN mstream_o[383]
    DIRECTION OUTPUT TRISTATE ;
    USE SIGNAL ;
    ANTENNADIFFAREA 0.795200 ;
    PORT
      LAYER met2 ;
        RECT 408.570 546.000 408.850 550.000 ;
    END
  END mstream_o[383]
  PIN mstream_o[384]
    DIRECTION OUTPUT TRISTATE ;
    USE SIGNAL ;
    ANTENNADIFFAREA 0.795200 ;
    PORT
      LAYER met2 ;
        RECT 409.490 546.000 409.770 550.000 ;
    END
  END mstream_o[384]
  PIN mstream_o[385]
    DIRECTION OUTPUT TRISTATE ;
    USE SIGNAL ;
    ANTENNADIFFAREA 0.795200 ;
    PORT
      LAYER met2 ;
        RECT 410.410 546.000 410.690 550.000 ;
    END
  END mstream_o[385]
  PIN mstream_o[386]
    DIRECTION OUTPUT TRISTATE ;
    USE SIGNAL ;
    ANTENNADIFFAREA 0.795200 ;
    PORT
      LAYER met2 ;
        RECT 411.330 546.000 411.610 550.000 ;
    END
  END mstream_o[386]
  PIN mstream_o[387]
    DIRECTION OUTPUT TRISTATE ;
    USE SIGNAL ;
    ANTENNADIFFAREA 0.795200 ;
    PORT
      LAYER met2 ;
        RECT 412.250 546.000 412.530 550.000 ;
    END
  END mstream_o[387]
  PIN mstream_o[388]
    DIRECTION OUTPUT TRISTATE ;
    USE SIGNAL ;
    ANTENNADIFFAREA 0.795200 ;
    PORT
      LAYER met2 ;
        RECT 413.170 546.000 413.450 550.000 ;
    END
  END mstream_o[388]
  PIN mstream_o[389]
    DIRECTION OUTPUT TRISTATE ;
    USE SIGNAL ;
    ANTENNADIFFAREA 0.795200 ;
    PORT
      LAYER met2 ;
        RECT 414.090 546.000 414.370 550.000 ;
    END
  END mstream_o[389]
  PIN mstream_o[38]
    DIRECTION OUTPUT TRISTATE ;
    USE SIGNAL ;
    ANTENNADIFFAREA 0.795200 ;
    PORT
      LAYER met2 ;
        RECT 91.170 546.000 91.450 550.000 ;
    END
  END mstream_o[38]
  PIN mstream_o[390]
    DIRECTION OUTPUT TRISTATE ;
    USE SIGNAL ;
    ANTENNADIFFAREA 0.795200 ;
    PORT
      LAYER met2 ;
        RECT 415.010 546.000 415.290 550.000 ;
    END
  END mstream_o[390]
  PIN mstream_o[391]
    DIRECTION OUTPUT TRISTATE ;
    USE SIGNAL ;
    ANTENNADIFFAREA 0.795200 ;
    PORT
      LAYER met2 ;
        RECT 415.930 546.000 416.210 550.000 ;
    END
  END mstream_o[391]
  PIN mstream_o[392]
    DIRECTION OUTPUT TRISTATE ;
    USE SIGNAL ;
    ANTENNADIFFAREA 0.795200 ;
    PORT
      LAYER met2 ;
        RECT 416.850 546.000 417.130 550.000 ;
    END
  END mstream_o[392]
  PIN mstream_o[393]
    DIRECTION OUTPUT TRISTATE ;
    USE SIGNAL ;
    ANTENNADIFFAREA 0.795200 ;
    PORT
      LAYER met2 ;
        RECT 417.770 546.000 418.050 550.000 ;
    END
  END mstream_o[393]
  PIN mstream_o[394]
    DIRECTION OUTPUT TRISTATE ;
    USE SIGNAL ;
    ANTENNADIFFAREA 0.795200 ;
    PORT
      LAYER met2 ;
        RECT 418.690 546.000 418.970 550.000 ;
    END
  END mstream_o[394]
  PIN mstream_o[395]
    DIRECTION OUTPUT TRISTATE ;
    USE SIGNAL ;
    ANTENNADIFFAREA 0.795200 ;
    PORT
      LAYER met2 ;
        RECT 419.610 546.000 419.890 550.000 ;
    END
  END mstream_o[395]
  PIN mstream_o[396]
    DIRECTION OUTPUT TRISTATE ;
    USE SIGNAL ;
    ANTENNADIFFAREA 0.795200 ;
    PORT
      LAYER met2 ;
        RECT 420.530 546.000 420.810 550.000 ;
    END
  END mstream_o[396]
  PIN mstream_o[397]
    DIRECTION OUTPUT TRISTATE ;
    USE SIGNAL ;
    ANTENNADIFFAREA 0.795200 ;
    PORT
      LAYER met2 ;
        RECT 421.450 546.000 421.730 550.000 ;
    END
  END mstream_o[397]
  PIN mstream_o[398]
    DIRECTION OUTPUT TRISTATE ;
    USE SIGNAL ;
    ANTENNADIFFAREA 0.795200 ;
    PORT
      LAYER met2 ;
        RECT 422.370 546.000 422.650 550.000 ;
    END
  END mstream_o[398]
  PIN mstream_o[399]
    DIRECTION OUTPUT TRISTATE ;
    USE SIGNAL ;
    ANTENNADIFFAREA 0.795200 ;
    PORT
      LAYER met2 ;
        RECT 423.290 546.000 423.570 550.000 ;
    END
  END mstream_o[399]
  PIN mstream_o[39]
    DIRECTION OUTPUT TRISTATE ;
    USE SIGNAL ;
    ANTENNADIFFAREA 0.795200 ;
    PORT
      LAYER met2 ;
        RECT 92.090 546.000 92.370 550.000 ;
    END
  END mstream_o[39]
  PIN mstream_o[3]
    DIRECTION OUTPUT TRISTATE ;
    USE SIGNAL ;
    ANTENNADIFFAREA 0.795200 ;
    PORT
      LAYER met2 ;
        RECT 58.970 546.000 59.250 550.000 ;
    END
  END mstream_o[3]
  PIN mstream_o[400]
    DIRECTION OUTPUT TRISTATE ;
    USE SIGNAL ;
    ANTENNADIFFAREA 0.795200 ;
    PORT
      LAYER met2 ;
        RECT 424.210 546.000 424.490 550.000 ;
    END
  END mstream_o[400]
  PIN mstream_o[401]
    DIRECTION OUTPUT TRISTATE ;
    USE SIGNAL ;
    ANTENNADIFFAREA 0.795200 ;
    PORT
      LAYER met2 ;
        RECT 425.130 546.000 425.410 550.000 ;
    END
  END mstream_o[401]
  PIN mstream_o[402]
    DIRECTION OUTPUT TRISTATE ;
    USE SIGNAL ;
    ANTENNADIFFAREA 0.795200 ;
    PORT
      LAYER met2 ;
        RECT 426.050 546.000 426.330 550.000 ;
    END
  END mstream_o[402]
  PIN mstream_o[403]
    DIRECTION OUTPUT TRISTATE ;
    USE SIGNAL ;
    ANTENNADIFFAREA 0.795200 ;
    PORT
      LAYER met2 ;
        RECT 426.970 546.000 427.250 550.000 ;
    END
  END mstream_o[403]
  PIN mstream_o[404]
    DIRECTION OUTPUT TRISTATE ;
    USE SIGNAL ;
    ANTENNADIFFAREA 0.795200 ;
    PORT
      LAYER met2 ;
        RECT 427.890 546.000 428.170 550.000 ;
    END
  END mstream_o[404]
  PIN mstream_o[405]
    DIRECTION OUTPUT TRISTATE ;
    USE SIGNAL ;
    ANTENNADIFFAREA 0.795200 ;
    PORT
      LAYER met2 ;
        RECT 428.810 546.000 429.090 550.000 ;
    END
  END mstream_o[405]
  PIN mstream_o[406]
    DIRECTION OUTPUT TRISTATE ;
    USE SIGNAL ;
    ANTENNADIFFAREA 0.795200 ;
    PORT
      LAYER met2 ;
        RECT 429.730 546.000 430.010 550.000 ;
    END
  END mstream_o[406]
  PIN mstream_o[407]
    DIRECTION OUTPUT TRISTATE ;
    USE SIGNAL ;
    ANTENNADIFFAREA 0.795200 ;
    PORT
      LAYER met2 ;
        RECT 430.650 546.000 430.930 550.000 ;
    END
  END mstream_o[407]
  PIN mstream_o[408]
    DIRECTION OUTPUT TRISTATE ;
    USE SIGNAL ;
    ANTENNADIFFAREA 0.795200 ;
    PORT
      LAYER met2 ;
        RECT 431.570 546.000 431.850 550.000 ;
    END
  END mstream_o[408]
  PIN mstream_o[409]
    DIRECTION OUTPUT TRISTATE ;
    USE SIGNAL ;
    ANTENNADIFFAREA 0.795200 ;
    PORT
      LAYER met2 ;
        RECT 432.490 546.000 432.770 550.000 ;
    END
  END mstream_o[409]
  PIN mstream_o[40]
    DIRECTION OUTPUT TRISTATE ;
    USE SIGNAL ;
    ANTENNADIFFAREA 0.795200 ;
    PORT
      LAYER met2 ;
        RECT 93.010 546.000 93.290 550.000 ;
    END
  END mstream_o[40]
  PIN mstream_o[410]
    DIRECTION OUTPUT TRISTATE ;
    USE SIGNAL ;
    ANTENNADIFFAREA 0.795200 ;
    PORT
      LAYER met2 ;
        RECT 433.410 546.000 433.690 550.000 ;
    END
  END mstream_o[410]
  PIN mstream_o[411]
    DIRECTION OUTPUT TRISTATE ;
    USE SIGNAL ;
    ANTENNADIFFAREA 0.795200 ;
    PORT
      LAYER met2 ;
        RECT 434.330 546.000 434.610 550.000 ;
    END
  END mstream_o[411]
  PIN mstream_o[412]
    DIRECTION OUTPUT TRISTATE ;
    USE SIGNAL ;
    ANTENNADIFFAREA 0.795200 ;
    PORT
      LAYER met2 ;
        RECT 435.250 546.000 435.530 550.000 ;
    END
  END mstream_o[412]
  PIN mstream_o[413]
    DIRECTION OUTPUT TRISTATE ;
    USE SIGNAL ;
    ANTENNADIFFAREA 0.795200 ;
    PORT
      LAYER met2 ;
        RECT 436.170 546.000 436.450 550.000 ;
    END
  END mstream_o[413]
  PIN mstream_o[414]
    DIRECTION OUTPUT TRISTATE ;
    USE SIGNAL ;
    ANTENNADIFFAREA 0.795200 ;
    PORT
      LAYER met2 ;
        RECT 437.090 546.000 437.370 550.000 ;
    END
  END mstream_o[414]
  PIN mstream_o[415]
    DIRECTION OUTPUT TRISTATE ;
    USE SIGNAL ;
    ANTENNADIFFAREA 0.795200 ;
    PORT
      LAYER met2 ;
        RECT 438.010 546.000 438.290 550.000 ;
    END
  END mstream_o[415]
  PIN mstream_o[416]
    DIRECTION OUTPUT TRISTATE ;
    USE SIGNAL ;
    ANTENNADIFFAREA 0.795200 ;
    PORT
      LAYER met2 ;
        RECT 438.930 546.000 439.210 550.000 ;
    END
  END mstream_o[416]
  PIN mstream_o[417]
    DIRECTION OUTPUT TRISTATE ;
    USE SIGNAL ;
    ANTENNADIFFAREA 0.795200 ;
    PORT
      LAYER met2 ;
        RECT 439.850 546.000 440.130 550.000 ;
    END
  END mstream_o[417]
  PIN mstream_o[418]
    DIRECTION OUTPUT TRISTATE ;
    USE SIGNAL ;
    ANTENNADIFFAREA 0.795200 ;
    PORT
      LAYER met2 ;
        RECT 440.770 546.000 441.050 550.000 ;
    END
  END mstream_o[418]
  PIN mstream_o[419]
    DIRECTION OUTPUT TRISTATE ;
    USE SIGNAL ;
    ANTENNADIFFAREA 0.795200 ;
    PORT
      LAYER met2 ;
        RECT 441.690 546.000 441.970 550.000 ;
    END
  END mstream_o[419]
  PIN mstream_o[41]
    DIRECTION OUTPUT TRISTATE ;
    USE SIGNAL ;
    ANTENNADIFFAREA 0.795200 ;
    PORT
      LAYER met2 ;
        RECT 93.930 546.000 94.210 550.000 ;
    END
  END mstream_o[41]
  PIN mstream_o[420]
    DIRECTION OUTPUT TRISTATE ;
    USE SIGNAL ;
    ANTENNADIFFAREA 0.795200 ;
    PORT
      LAYER met2 ;
        RECT 442.610 546.000 442.890 550.000 ;
    END
  END mstream_o[420]
  PIN mstream_o[421]
    DIRECTION OUTPUT TRISTATE ;
    USE SIGNAL ;
    ANTENNADIFFAREA 0.795200 ;
    PORT
      LAYER met2 ;
        RECT 443.530 546.000 443.810 550.000 ;
    END
  END mstream_o[421]
  PIN mstream_o[422]
    DIRECTION OUTPUT TRISTATE ;
    USE SIGNAL ;
    ANTENNADIFFAREA 0.795200 ;
    PORT
      LAYER met2 ;
        RECT 444.450 546.000 444.730 550.000 ;
    END
  END mstream_o[422]
  PIN mstream_o[423]
    DIRECTION OUTPUT TRISTATE ;
    USE SIGNAL ;
    ANTENNADIFFAREA 0.795200 ;
    PORT
      LAYER met2 ;
        RECT 445.370 546.000 445.650 550.000 ;
    END
  END mstream_o[423]
  PIN mstream_o[424]
    DIRECTION OUTPUT TRISTATE ;
    USE SIGNAL ;
    ANTENNADIFFAREA 0.795200 ;
    PORT
      LAYER met2 ;
        RECT 446.290 546.000 446.570 550.000 ;
    END
  END mstream_o[424]
  PIN mstream_o[425]
    DIRECTION OUTPUT TRISTATE ;
    USE SIGNAL ;
    ANTENNADIFFAREA 0.795200 ;
    PORT
      LAYER met2 ;
        RECT 447.210 546.000 447.490 550.000 ;
    END
  END mstream_o[425]
  PIN mstream_o[426]
    DIRECTION OUTPUT TRISTATE ;
    USE SIGNAL ;
    ANTENNADIFFAREA 0.795200 ;
    PORT
      LAYER met2 ;
        RECT 448.130 546.000 448.410 550.000 ;
    END
  END mstream_o[426]
  PIN mstream_o[427]
    DIRECTION OUTPUT TRISTATE ;
    USE SIGNAL ;
    ANTENNADIFFAREA 0.795200 ;
    PORT
      LAYER met2 ;
        RECT 449.050 546.000 449.330 550.000 ;
    END
  END mstream_o[427]
  PIN mstream_o[428]
    DIRECTION OUTPUT TRISTATE ;
    USE SIGNAL ;
    ANTENNADIFFAREA 0.795200 ;
    PORT
      LAYER met2 ;
        RECT 449.970 546.000 450.250 550.000 ;
    END
  END mstream_o[428]
  PIN mstream_o[429]
    DIRECTION OUTPUT TRISTATE ;
    USE SIGNAL ;
    ANTENNADIFFAREA 0.795200 ;
    PORT
      LAYER met2 ;
        RECT 450.890 546.000 451.170 550.000 ;
    END
  END mstream_o[429]
  PIN mstream_o[42]
    DIRECTION OUTPUT TRISTATE ;
    USE SIGNAL ;
    ANTENNADIFFAREA 0.795200 ;
    PORT
      LAYER met2 ;
        RECT 94.850 546.000 95.130 550.000 ;
    END
  END mstream_o[42]
  PIN mstream_o[430]
    DIRECTION OUTPUT TRISTATE ;
    USE SIGNAL ;
    ANTENNADIFFAREA 0.795200 ;
    PORT
      LAYER met2 ;
        RECT 451.810 546.000 452.090 550.000 ;
    END
  END mstream_o[430]
  PIN mstream_o[431]
    DIRECTION OUTPUT TRISTATE ;
    USE SIGNAL ;
    ANTENNADIFFAREA 0.795200 ;
    PORT
      LAYER met2 ;
        RECT 452.730 546.000 453.010 550.000 ;
    END
  END mstream_o[431]
  PIN mstream_o[432]
    DIRECTION OUTPUT TRISTATE ;
    USE SIGNAL ;
    ANTENNADIFFAREA 0.795200 ;
    PORT
      LAYER met2 ;
        RECT 453.650 546.000 453.930 550.000 ;
    END
  END mstream_o[432]
  PIN mstream_o[433]
    DIRECTION OUTPUT TRISTATE ;
    USE SIGNAL ;
    ANTENNADIFFAREA 0.795200 ;
    PORT
      LAYER met2 ;
        RECT 454.570 546.000 454.850 550.000 ;
    END
  END mstream_o[433]
  PIN mstream_o[434]
    DIRECTION OUTPUT TRISTATE ;
    USE SIGNAL ;
    ANTENNADIFFAREA 0.795200 ;
    PORT
      LAYER met2 ;
        RECT 455.490 546.000 455.770 550.000 ;
    END
  END mstream_o[434]
  PIN mstream_o[435]
    DIRECTION OUTPUT TRISTATE ;
    USE SIGNAL ;
    ANTENNADIFFAREA 0.891000 ;
    PORT
      LAYER met2 ;
        RECT 456.410 546.000 456.690 550.000 ;
    END
  END mstream_o[435]
  PIN mstream_o[436]
    DIRECTION OUTPUT TRISTATE ;
    USE SIGNAL ;
    ANTENNADIFFAREA 0.795200 ;
    PORT
      LAYER met2 ;
        RECT 457.330 546.000 457.610 550.000 ;
    END
  END mstream_o[436]
  PIN mstream_o[437]
    DIRECTION OUTPUT TRISTATE ;
    USE SIGNAL ;
    ANTENNADIFFAREA 0.795200 ;
    PORT
      LAYER met2 ;
        RECT 458.250 546.000 458.530 550.000 ;
    END
  END mstream_o[437]
  PIN mstream_o[438]
    DIRECTION OUTPUT TRISTATE ;
    USE SIGNAL ;
    ANTENNADIFFAREA 0.795200 ;
    PORT
      LAYER met2 ;
        RECT 459.170 546.000 459.450 550.000 ;
    END
  END mstream_o[438]
  PIN mstream_o[439]
    DIRECTION OUTPUT TRISTATE ;
    USE SIGNAL ;
    ANTENNADIFFAREA 0.795200 ;
    PORT
      LAYER met2 ;
        RECT 460.090 546.000 460.370 550.000 ;
    END
  END mstream_o[439]
  PIN mstream_o[43]
    DIRECTION OUTPUT TRISTATE ;
    USE SIGNAL ;
    ANTENNADIFFAREA 0.795200 ;
    PORT
      LAYER met2 ;
        RECT 95.770 546.000 96.050 550.000 ;
    END
  END mstream_o[43]
  PIN mstream_o[440]
    DIRECTION OUTPUT TRISTATE ;
    USE SIGNAL ;
    ANTENNADIFFAREA 0.795200 ;
    PORT
      LAYER met2 ;
        RECT 461.010 546.000 461.290 550.000 ;
    END
  END mstream_o[440]
  PIN mstream_o[441]
    DIRECTION OUTPUT TRISTATE ;
    USE SIGNAL ;
    ANTENNADIFFAREA 0.795200 ;
    PORT
      LAYER met2 ;
        RECT 461.930 546.000 462.210 550.000 ;
    END
  END mstream_o[441]
  PIN mstream_o[442]
    DIRECTION OUTPUT TRISTATE ;
    USE SIGNAL ;
    ANTENNADIFFAREA 0.795200 ;
    PORT
      LAYER met2 ;
        RECT 462.850 546.000 463.130 550.000 ;
    END
  END mstream_o[442]
  PIN mstream_o[443]
    DIRECTION OUTPUT TRISTATE ;
    USE SIGNAL ;
    ANTENNADIFFAREA 0.795200 ;
    PORT
      LAYER met2 ;
        RECT 463.770 546.000 464.050 550.000 ;
    END
  END mstream_o[443]
  PIN mstream_o[444]
    DIRECTION OUTPUT TRISTATE ;
    USE SIGNAL ;
    ANTENNADIFFAREA 0.795200 ;
    PORT
      LAYER met2 ;
        RECT 464.690 546.000 464.970 550.000 ;
    END
  END mstream_o[444]
  PIN mstream_o[445]
    DIRECTION OUTPUT TRISTATE ;
    USE SIGNAL ;
    ANTENNADIFFAREA 0.795200 ;
    PORT
      LAYER met2 ;
        RECT 465.610 546.000 465.890 550.000 ;
    END
  END mstream_o[445]
  PIN mstream_o[446]
    DIRECTION OUTPUT TRISTATE ;
    USE SIGNAL ;
    ANTENNADIFFAREA 0.795200 ;
    PORT
      LAYER met2 ;
        RECT 466.530 546.000 466.810 550.000 ;
    END
  END mstream_o[446]
  PIN mstream_o[447]
    DIRECTION OUTPUT TRISTATE ;
    USE SIGNAL ;
    ANTENNADIFFAREA 0.795200 ;
    PORT
      LAYER met2 ;
        RECT 467.450 546.000 467.730 550.000 ;
    END
  END mstream_o[447]
  PIN mstream_o[448]
    DIRECTION OUTPUT TRISTATE ;
    USE SIGNAL ;
    ANTENNADIFFAREA 0.795200 ;
    PORT
      LAYER met2 ;
        RECT 468.370 546.000 468.650 550.000 ;
    END
  END mstream_o[448]
  PIN mstream_o[449]
    DIRECTION OUTPUT TRISTATE ;
    USE SIGNAL ;
    ANTENNADIFFAREA 0.795200 ;
    PORT
      LAYER met2 ;
        RECT 469.290 546.000 469.570 550.000 ;
    END
  END mstream_o[449]
  PIN mstream_o[44]
    DIRECTION OUTPUT TRISTATE ;
    USE SIGNAL ;
    ANTENNADIFFAREA 0.795200 ;
    PORT
      LAYER met2 ;
        RECT 96.690 546.000 96.970 550.000 ;
    END
  END mstream_o[44]
  PIN mstream_o[450]
    DIRECTION OUTPUT TRISTATE ;
    USE SIGNAL ;
    ANTENNADIFFAREA 0.795200 ;
    PORT
      LAYER met2 ;
        RECT 470.210 546.000 470.490 550.000 ;
    END
  END mstream_o[450]
  PIN mstream_o[451]
    DIRECTION OUTPUT TRISTATE ;
    USE SIGNAL ;
    ANTENNADIFFAREA 0.795200 ;
    PORT
      LAYER met2 ;
        RECT 471.130 546.000 471.410 550.000 ;
    END
  END mstream_o[451]
  PIN mstream_o[452]
    DIRECTION OUTPUT TRISTATE ;
    USE SIGNAL ;
    ANTENNADIFFAREA 0.795200 ;
    PORT
      LAYER met2 ;
        RECT 472.050 546.000 472.330 550.000 ;
    END
  END mstream_o[452]
  PIN mstream_o[453]
    DIRECTION OUTPUT TRISTATE ;
    USE SIGNAL ;
    ANTENNADIFFAREA 0.795200 ;
    PORT
      LAYER met2 ;
        RECT 472.970 546.000 473.250 550.000 ;
    END
  END mstream_o[453]
  PIN mstream_o[454]
    DIRECTION OUTPUT TRISTATE ;
    USE SIGNAL ;
    ANTENNADIFFAREA 0.795200 ;
    PORT
      LAYER met2 ;
        RECT 473.890 546.000 474.170 550.000 ;
    END
  END mstream_o[454]
  PIN mstream_o[455]
    DIRECTION OUTPUT TRISTATE ;
    USE SIGNAL ;
    ANTENNADIFFAREA 0.795200 ;
    PORT
      LAYER met2 ;
        RECT 474.810 546.000 475.090 550.000 ;
    END
  END mstream_o[455]
  PIN mstream_o[456]
    DIRECTION OUTPUT TRISTATE ;
    USE SIGNAL ;
    ANTENNADIFFAREA 0.795200 ;
    PORT
      LAYER met2 ;
        RECT 475.730 546.000 476.010 550.000 ;
    END
  END mstream_o[456]
  PIN mstream_o[457]
    DIRECTION OUTPUT TRISTATE ;
    USE SIGNAL ;
    ANTENNADIFFAREA 0.795200 ;
    PORT
      LAYER met2 ;
        RECT 476.650 546.000 476.930 550.000 ;
    END
  END mstream_o[457]
  PIN mstream_o[458]
    DIRECTION OUTPUT TRISTATE ;
    USE SIGNAL ;
    ANTENNADIFFAREA 0.795200 ;
    PORT
      LAYER met2 ;
        RECT 477.570 546.000 477.850 550.000 ;
    END
  END mstream_o[458]
  PIN mstream_o[459]
    DIRECTION OUTPUT TRISTATE ;
    USE SIGNAL ;
    ANTENNADIFFAREA 0.795200 ;
    PORT
      LAYER met2 ;
        RECT 478.490 546.000 478.770 550.000 ;
    END
  END mstream_o[459]
  PIN mstream_o[45]
    DIRECTION OUTPUT TRISTATE ;
    USE SIGNAL ;
    ANTENNADIFFAREA 0.795200 ;
    PORT
      LAYER met2 ;
        RECT 97.610 546.000 97.890 550.000 ;
    END
  END mstream_o[45]
  PIN mstream_o[460]
    DIRECTION OUTPUT TRISTATE ;
    USE SIGNAL ;
    ANTENNADIFFAREA 0.795200 ;
    PORT
      LAYER met2 ;
        RECT 479.410 546.000 479.690 550.000 ;
    END
  END mstream_o[460]
  PIN mstream_o[461]
    DIRECTION OUTPUT TRISTATE ;
    USE SIGNAL ;
    ANTENNADIFFAREA 0.795200 ;
    PORT
      LAYER met2 ;
        RECT 480.330 546.000 480.610 550.000 ;
    END
  END mstream_o[461]
  PIN mstream_o[462]
    DIRECTION OUTPUT TRISTATE ;
    USE SIGNAL ;
    ANTENNADIFFAREA 0.795200 ;
    PORT
      LAYER met2 ;
        RECT 481.250 546.000 481.530 550.000 ;
    END
  END mstream_o[462]
  PIN mstream_o[463]
    DIRECTION OUTPUT TRISTATE ;
    USE SIGNAL ;
    ANTENNADIFFAREA 0.795200 ;
    PORT
      LAYER met2 ;
        RECT 482.170 546.000 482.450 550.000 ;
    END
  END mstream_o[463]
  PIN mstream_o[464]
    DIRECTION OUTPUT TRISTATE ;
    USE SIGNAL ;
    ANTENNADIFFAREA 0.795200 ;
    PORT
      LAYER met2 ;
        RECT 483.090 546.000 483.370 550.000 ;
    END
  END mstream_o[464]
  PIN mstream_o[465]
    DIRECTION OUTPUT TRISTATE ;
    USE SIGNAL ;
    ANTENNADIFFAREA 0.795200 ;
    PORT
      LAYER met2 ;
        RECT 484.010 546.000 484.290 550.000 ;
    END
  END mstream_o[465]
  PIN mstream_o[466]
    DIRECTION OUTPUT TRISTATE ;
    USE SIGNAL ;
    ANTENNADIFFAREA 0.795200 ;
    PORT
      LAYER met2 ;
        RECT 484.930 546.000 485.210 550.000 ;
    END
  END mstream_o[466]
  PIN mstream_o[467]
    DIRECTION OUTPUT TRISTATE ;
    USE SIGNAL ;
    ANTENNADIFFAREA 0.795200 ;
    PORT
      LAYER met2 ;
        RECT 485.850 546.000 486.130 550.000 ;
    END
  END mstream_o[467]
  PIN mstream_o[468]
    DIRECTION OUTPUT TRISTATE ;
    USE SIGNAL ;
    ANTENNADIFFAREA 0.795200 ;
    PORT
      LAYER met2 ;
        RECT 486.770 546.000 487.050 550.000 ;
    END
  END mstream_o[468]
  PIN mstream_o[469]
    DIRECTION OUTPUT TRISTATE ;
    USE SIGNAL ;
    ANTENNADIFFAREA 0.795200 ;
    PORT
      LAYER met2 ;
        RECT 487.690 546.000 487.970 550.000 ;
    END
  END mstream_o[469]
  PIN mstream_o[46]
    DIRECTION OUTPUT TRISTATE ;
    USE SIGNAL ;
    ANTENNADIFFAREA 0.795200 ;
    PORT
      LAYER met2 ;
        RECT 98.530 546.000 98.810 550.000 ;
    END
  END mstream_o[46]
  PIN mstream_o[470]
    DIRECTION OUTPUT TRISTATE ;
    USE SIGNAL ;
    ANTENNADIFFAREA 0.795200 ;
    PORT
      LAYER met2 ;
        RECT 488.610 546.000 488.890 550.000 ;
    END
  END mstream_o[470]
  PIN mstream_o[471]
    DIRECTION OUTPUT TRISTATE ;
    USE SIGNAL ;
    ANTENNADIFFAREA 0.795200 ;
    PORT
      LAYER met2 ;
        RECT 489.530 546.000 489.810 550.000 ;
    END
  END mstream_o[471]
  PIN mstream_o[472]
    DIRECTION OUTPUT TRISTATE ;
    USE SIGNAL ;
    ANTENNADIFFAREA 0.795200 ;
    PORT
      LAYER met2 ;
        RECT 490.450 546.000 490.730 550.000 ;
    END
  END mstream_o[472]
  PIN mstream_o[473]
    DIRECTION OUTPUT TRISTATE ;
    USE SIGNAL ;
    ANTENNADIFFAREA 0.795200 ;
    PORT
      LAYER met2 ;
        RECT 491.370 546.000 491.650 550.000 ;
    END
  END mstream_o[473]
  PIN mstream_o[474]
    DIRECTION OUTPUT TRISTATE ;
    USE SIGNAL ;
    ANTENNADIFFAREA 0.795200 ;
    PORT
      LAYER met2 ;
        RECT 492.290 546.000 492.570 550.000 ;
    END
  END mstream_o[474]
  PIN mstream_o[475]
    DIRECTION OUTPUT TRISTATE ;
    USE SIGNAL ;
    ANTENNADIFFAREA 0.795200 ;
    PORT
      LAYER met2 ;
        RECT 493.210 546.000 493.490 550.000 ;
    END
  END mstream_o[475]
  PIN mstream_o[476]
    DIRECTION OUTPUT TRISTATE ;
    USE SIGNAL ;
    ANTENNADIFFAREA 0.795200 ;
    PORT
      LAYER met2 ;
        RECT 494.130 546.000 494.410 550.000 ;
    END
  END mstream_o[476]
  PIN mstream_o[477]
    DIRECTION OUTPUT TRISTATE ;
    USE SIGNAL ;
    ANTENNADIFFAREA 0.795200 ;
    PORT
      LAYER met2 ;
        RECT 495.050 546.000 495.330 550.000 ;
    END
  END mstream_o[477]
  PIN mstream_o[478]
    DIRECTION OUTPUT TRISTATE ;
    USE SIGNAL ;
    ANTENNADIFFAREA 0.795200 ;
    PORT
      LAYER met2 ;
        RECT 495.970 546.000 496.250 550.000 ;
    END
  END mstream_o[478]
  PIN mstream_o[479]
    DIRECTION OUTPUT TRISTATE ;
    USE SIGNAL ;
    ANTENNADIFFAREA 0.795200 ;
    PORT
      LAYER met2 ;
        RECT 496.890 546.000 497.170 550.000 ;
    END
  END mstream_o[479]
  PIN mstream_o[47]
    DIRECTION OUTPUT TRISTATE ;
    USE SIGNAL ;
    ANTENNADIFFAREA 0.795200 ;
    PORT
      LAYER met2 ;
        RECT 99.450 546.000 99.730 550.000 ;
    END
  END mstream_o[47]
  PIN mstream_o[480]
    DIRECTION OUTPUT TRISTATE ;
    USE SIGNAL ;
    ANTENNADIFFAREA 0.795200 ;
    PORT
      LAYER met2 ;
        RECT 497.810 546.000 498.090 550.000 ;
    END
  END mstream_o[480]
  PIN mstream_o[481]
    DIRECTION OUTPUT TRISTATE ;
    USE SIGNAL ;
    ANTENNADIFFAREA 0.795200 ;
    PORT
      LAYER met2 ;
        RECT 498.730 546.000 499.010 550.000 ;
    END
  END mstream_o[481]
  PIN mstream_o[482]
    DIRECTION OUTPUT TRISTATE ;
    USE SIGNAL ;
    ANTENNADIFFAREA 0.795200 ;
    PORT
      LAYER met2 ;
        RECT 499.650 546.000 499.930 550.000 ;
    END
  END mstream_o[482]
  PIN mstream_o[483]
    DIRECTION OUTPUT TRISTATE ;
    USE SIGNAL ;
    ANTENNADIFFAREA 0.795200 ;
    PORT
      LAYER met2 ;
        RECT 500.570 546.000 500.850 550.000 ;
    END
  END mstream_o[483]
  PIN mstream_o[484]
    DIRECTION OUTPUT TRISTATE ;
    USE SIGNAL ;
    ANTENNADIFFAREA 0.795200 ;
    PORT
      LAYER met2 ;
        RECT 501.490 546.000 501.770 550.000 ;
    END
  END mstream_o[484]
  PIN mstream_o[485]
    DIRECTION OUTPUT TRISTATE ;
    USE SIGNAL ;
    ANTENNADIFFAREA 0.795200 ;
    PORT
      LAYER met2 ;
        RECT 502.410 546.000 502.690 550.000 ;
    END
  END mstream_o[485]
  PIN mstream_o[486]
    DIRECTION OUTPUT TRISTATE ;
    USE SIGNAL ;
    ANTENNADIFFAREA 0.795200 ;
    PORT
      LAYER met2 ;
        RECT 503.330 546.000 503.610 550.000 ;
    END
  END mstream_o[486]
  PIN mstream_o[487]
    DIRECTION OUTPUT TRISTATE ;
    USE SIGNAL ;
    ANTENNADIFFAREA 0.795200 ;
    PORT
      LAYER met2 ;
        RECT 504.250 546.000 504.530 550.000 ;
    END
  END mstream_o[487]
  PIN mstream_o[488]
    DIRECTION OUTPUT TRISTATE ;
    USE SIGNAL ;
    ANTENNADIFFAREA 0.795200 ;
    PORT
      LAYER met2 ;
        RECT 505.170 546.000 505.450 550.000 ;
    END
  END mstream_o[488]
  PIN mstream_o[489]
    DIRECTION OUTPUT TRISTATE ;
    USE SIGNAL ;
    ANTENNADIFFAREA 0.795200 ;
    PORT
      LAYER met2 ;
        RECT 506.090 546.000 506.370 550.000 ;
    END
  END mstream_o[489]
  PIN mstream_o[48]
    DIRECTION OUTPUT TRISTATE ;
    USE SIGNAL ;
    ANTENNADIFFAREA 0.795200 ;
    PORT
      LAYER met2 ;
        RECT 100.370 546.000 100.650 550.000 ;
    END
  END mstream_o[48]
  PIN mstream_o[490]
    DIRECTION OUTPUT TRISTATE ;
    USE SIGNAL ;
    ANTENNADIFFAREA 0.795200 ;
    PORT
      LAYER met2 ;
        RECT 507.010 546.000 507.290 550.000 ;
    END
  END mstream_o[490]
  PIN mstream_o[491]
    DIRECTION OUTPUT TRISTATE ;
    USE SIGNAL ;
    ANTENNADIFFAREA 0.795200 ;
    PORT
      LAYER met2 ;
        RECT 507.930 546.000 508.210 550.000 ;
    END
  END mstream_o[491]
  PIN mstream_o[492]
    DIRECTION OUTPUT TRISTATE ;
    USE SIGNAL ;
    ANTENNADIFFAREA 0.795200 ;
    PORT
      LAYER met2 ;
        RECT 508.850 546.000 509.130 550.000 ;
    END
  END mstream_o[492]
  PIN mstream_o[493]
    DIRECTION OUTPUT TRISTATE ;
    USE SIGNAL ;
    ANTENNADIFFAREA 0.795200 ;
    PORT
      LAYER met2 ;
        RECT 509.770 546.000 510.050 550.000 ;
    END
  END mstream_o[493]
  PIN mstream_o[494]
    DIRECTION OUTPUT TRISTATE ;
    USE SIGNAL ;
    ANTENNADIFFAREA 0.795200 ;
    PORT
      LAYER met2 ;
        RECT 510.690 546.000 510.970 550.000 ;
    END
  END mstream_o[494]
  PIN mstream_o[495]
    DIRECTION OUTPUT TRISTATE ;
    USE SIGNAL ;
    ANTENNADIFFAREA 0.795200 ;
    PORT
      LAYER met2 ;
        RECT 511.610 546.000 511.890 550.000 ;
    END
  END mstream_o[495]
  PIN mstream_o[496]
    DIRECTION OUTPUT TRISTATE ;
    USE SIGNAL ;
    ANTENNADIFFAREA 0.795200 ;
    PORT
      LAYER met2 ;
        RECT 512.530 546.000 512.810 550.000 ;
    END
  END mstream_o[496]
  PIN mstream_o[497]
    DIRECTION OUTPUT TRISTATE ;
    USE SIGNAL ;
    ANTENNADIFFAREA 0.795200 ;
    PORT
      LAYER met2 ;
        RECT 513.450 546.000 513.730 550.000 ;
    END
  END mstream_o[497]
  PIN mstream_o[498]
    DIRECTION OUTPUT TRISTATE ;
    USE SIGNAL ;
    ANTENNADIFFAREA 0.795200 ;
    PORT
      LAYER met2 ;
        RECT 514.370 546.000 514.650 550.000 ;
    END
  END mstream_o[498]
  PIN mstream_o[499]
    DIRECTION OUTPUT TRISTATE ;
    USE SIGNAL ;
    ANTENNADIFFAREA 0.795200 ;
    PORT
      LAYER met2 ;
        RECT 515.290 546.000 515.570 550.000 ;
    END
  END mstream_o[499]
  PIN mstream_o[49]
    DIRECTION OUTPUT TRISTATE ;
    USE SIGNAL ;
    ANTENNADIFFAREA 0.795200 ;
    PORT
      LAYER met2 ;
        RECT 101.290 546.000 101.570 550.000 ;
    END
  END mstream_o[49]
  PIN mstream_o[4]
    DIRECTION OUTPUT TRISTATE ;
    USE SIGNAL ;
    ANTENNADIFFAREA 0.795200 ;
    PORT
      LAYER met2 ;
        RECT 59.890 546.000 60.170 550.000 ;
    END
  END mstream_o[4]
  PIN mstream_o[500]
    DIRECTION OUTPUT TRISTATE ;
    USE SIGNAL ;
    ANTENNADIFFAREA 0.795200 ;
    PORT
      LAYER met2 ;
        RECT 516.210 546.000 516.490 550.000 ;
    END
  END mstream_o[500]
  PIN mstream_o[501]
    DIRECTION OUTPUT TRISTATE ;
    USE SIGNAL ;
    ANTENNADIFFAREA 0.795200 ;
    PORT
      LAYER met2 ;
        RECT 517.130 546.000 517.410 550.000 ;
    END
  END mstream_o[501]
  PIN mstream_o[502]
    DIRECTION OUTPUT TRISTATE ;
    USE SIGNAL ;
    ANTENNADIFFAREA 0.795200 ;
    PORT
      LAYER met2 ;
        RECT 518.050 546.000 518.330 550.000 ;
    END
  END mstream_o[502]
  PIN mstream_o[503]
    DIRECTION OUTPUT TRISTATE ;
    USE SIGNAL ;
    ANTENNADIFFAREA 0.795200 ;
    PORT
      LAYER met2 ;
        RECT 518.970 546.000 519.250 550.000 ;
    END
  END mstream_o[503]
  PIN mstream_o[504]
    DIRECTION OUTPUT TRISTATE ;
    USE SIGNAL ;
    ANTENNADIFFAREA 0.795200 ;
    PORT
      LAYER met2 ;
        RECT 519.890 546.000 520.170 550.000 ;
    END
  END mstream_o[504]
  PIN mstream_o[505]
    DIRECTION OUTPUT TRISTATE ;
    USE SIGNAL ;
    ANTENNADIFFAREA 0.795200 ;
    PORT
      LAYER met2 ;
        RECT 520.810 546.000 521.090 550.000 ;
    END
  END mstream_o[505]
  PIN mstream_o[506]
    DIRECTION OUTPUT TRISTATE ;
    USE SIGNAL ;
    ANTENNADIFFAREA 0.795200 ;
    PORT
      LAYER met2 ;
        RECT 521.730 546.000 522.010 550.000 ;
    END
  END mstream_o[506]
  PIN mstream_o[507]
    DIRECTION OUTPUT TRISTATE ;
    USE SIGNAL ;
    ANTENNADIFFAREA 0.795200 ;
    PORT
      LAYER met2 ;
        RECT 522.650 546.000 522.930 550.000 ;
    END
  END mstream_o[507]
  PIN mstream_o[508]
    DIRECTION OUTPUT TRISTATE ;
    USE SIGNAL ;
    ANTENNADIFFAREA 0.795200 ;
    PORT
      LAYER met2 ;
        RECT 523.570 546.000 523.850 550.000 ;
    END
  END mstream_o[508]
  PIN mstream_o[509]
    DIRECTION OUTPUT TRISTATE ;
    USE SIGNAL ;
    ANTENNADIFFAREA 0.795200 ;
    PORT
      LAYER met2 ;
        RECT 524.490 546.000 524.770 550.000 ;
    END
  END mstream_o[509]
  PIN mstream_o[50]
    DIRECTION OUTPUT TRISTATE ;
    USE SIGNAL ;
    ANTENNADIFFAREA 0.795200 ;
    PORT
      LAYER met2 ;
        RECT 102.210 546.000 102.490 550.000 ;
    END
  END mstream_o[50]
  PIN mstream_o[510]
    DIRECTION OUTPUT TRISTATE ;
    USE SIGNAL ;
    ANTENNADIFFAREA 0.795200 ;
    PORT
      LAYER met2 ;
        RECT 525.410 546.000 525.690 550.000 ;
    END
  END mstream_o[510]
  PIN mstream_o[511]
    DIRECTION OUTPUT TRISTATE ;
    USE SIGNAL ;
    ANTENNADIFFAREA 0.795200 ;
    PORT
      LAYER met2 ;
        RECT 526.330 546.000 526.610 550.000 ;
    END
  END mstream_o[511]
  PIN mstream_o[512]
    DIRECTION OUTPUT TRISTATE ;
    USE SIGNAL ;
    ANTENNADIFFAREA 0.795200 ;
    PORT
      LAYER met2 ;
        RECT 527.250 546.000 527.530 550.000 ;
    END
  END mstream_o[512]
  PIN mstream_o[513]
    DIRECTION OUTPUT TRISTATE ;
    USE SIGNAL ;
    ANTENNADIFFAREA 0.795200 ;
    PORT
      LAYER met2 ;
        RECT 528.170 546.000 528.450 550.000 ;
    END
  END mstream_o[513]
  PIN mstream_o[514]
    DIRECTION OUTPUT TRISTATE ;
    USE SIGNAL ;
    ANTENNADIFFAREA 0.795200 ;
    PORT
      LAYER met2 ;
        RECT 529.090 546.000 529.370 550.000 ;
    END
  END mstream_o[514]
  PIN mstream_o[515]
    DIRECTION OUTPUT TRISTATE ;
    USE SIGNAL ;
    ANTENNADIFFAREA 0.795200 ;
    PORT
      LAYER met2 ;
        RECT 530.010 546.000 530.290 550.000 ;
    END
  END mstream_o[515]
  PIN mstream_o[516]
    DIRECTION OUTPUT TRISTATE ;
    USE SIGNAL ;
    ANTENNADIFFAREA 0.795200 ;
    PORT
      LAYER met2 ;
        RECT 530.930 546.000 531.210 550.000 ;
    END
  END mstream_o[516]
  PIN mstream_o[517]
    DIRECTION OUTPUT TRISTATE ;
    USE SIGNAL ;
    ANTENNADIFFAREA 0.795200 ;
    PORT
      LAYER met2 ;
        RECT 531.850 546.000 532.130 550.000 ;
    END
  END mstream_o[517]
  PIN mstream_o[518]
    DIRECTION OUTPUT TRISTATE ;
    USE SIGNAL ;
    ANTENNADIFFAREA 0.795200 ;
    PORT
      LAYER met2 ;
        RECT 532.770 546.000 533.050 550.000 ;
    END
  END mstream_o[518]
  PIN mstream_o[519]
    DIRECTION OUTPUT TRISTATE ;
    USE SIGNAL ;
    ANTENNADIFFAREA 0.795200 ;
    PORT
      LAYER met2 ;
        RECT 533.690 546.000 533.970 550.000 ;
    END
  END mstream_o[519]
  PIN mstream_o[51]
    DIRECTION OUTPUT TRISTATE ;
    USE SIGNAL ;
    ANTENNADIFFAREA 0.795200 ;
    PORT
      LAYER met2 ;
        RECT 103.130 546.000 103.410 550.000 ;
    END
  END mstream_o[51]
  PIN mstream_o[520]
    DIRECTION OUTPUT TRISTATE ;
    USE SIGNAL ;
    ANTENNADIFFAREA 0.795200 ;
    PORT
      LAYER met2 ;
        RECT 534.610 546.000 534.890 550.000 ;
    END
  END mstream_o[520]
  PIN mstream_o[521]
    DIRECTION OUTPUT TRISTATE ;
    USE SIGNAL ;
    ANTENNADIFFAREA 0.795200 ;
    PORT
      LAYER met2 ;
        RECT 535.530 546.000 535.810 550.000 ;
    END
  END mstream_o[521]
  PIN mstream_o[522]
    DIRECTION OUTPUT TRISTATE ;
    USE SIGNAL ;
    ANTENNADIFFAREA 0.795200 ;
    PORT
      LAYER met2 ;
        RECT 536.450 546.000 536.730 550.000 ;
    END
  END mstream_o[522]
  PIN mstream_o[523]
    DIRECTION OUTPUT TRISTATE ;
    USE SIGNAL ;
    ANTENNADIFFAREA 0.795200 ;
    PORT
      LAYER met2 ;
        RECT 537.370 546.000 537.650 550.000 ;
    END
  END mstream_o[523]
  PIN mstream_o[524]
    DIRECTION OUTPUT TRISTATE ;
    USE SIGNAL ;
    ANTENNADIFFAREA 0.795200 ;
    PORT
      LAYER met2 ;
        RECT 538.290 546.000 538.570 550.000 ;
    END
  END mstream_o[524]
  PIN mstream_o[525]
    DIRECTION OUTPUT TRISTATE ;
    USE SIGNAL ;
    ANTENNADIFFAREA 0.795200 ;
    PORT
      LAYER met2 ;
        RECT 539.210 546.000 539.490 550.000 ;
    END
  END mstream_o[525]
  PIN mstream_o[526]
    DIRECTION OUTPUT TRISTATE ;
    USE SIGNAL ;
    ANTENNADIFFAREA 0.795200 ;
    PORT
      LAYER met2 ;
        RECT 540.130 546.000 540.410 550.000 ;
    END
  END mstream_o[526]
  PIN mstream_o[527]
    DIRECTION OUTPUT TRISTATE ;
    USE SIGNAL ;
    ANTENNADIFFAREA 0.795200 ;
    PORT
      LAYER met2 ;
        RECT 541.050 546.000 541.330 550.000 ;
    END
  END mstream_o[527]
  PIN mstream_o[528]
    DIRECTION OUTPUT TRISTATE ;
    USE SIGNAL ;
    ANTENNADIFFAREA 0.795200 ;
    PORT
      LAYER met2 ;
        RECT 541.970 546.000 542.250 550.000 ;
    END
  END mstream_o[528]
  PIN mstream_o[529]
    DIRECTION OUTPUT TRISTATE ;
    USE SIGNAL ;
    ANTENNADIFFAREA 0.795200 ;
    PORT
      LAYER met2 ;
        RECT 542.890 546.000 543.170 550.000 ;
    END
  END mstream_o[529]
  PIN mstream_o[52]
    DIRECTION OUTPUT TRISTATE ;
    USE SIGNAL ;
    ANTENNADIFFAREA 0.795200 ;
    PORT
      LAYER met2 ;
        RECT 104.050 546.000 104.330 550.000 ;
    END
  END mstream_o[52]
  PIN mstream_o[530]
    DIRECTION OUTPUT TRISTATE ;
    USE SIGNAL ;
    ANTENNADIFFAREA 0.795200 ;
    PORT
      LAYER met2 ;
        RECT 543.810 546.000 544.090 550.000 ;
    END
  END mstream_o[530]
  PIN mstream_o[531]
    DIRECTION OUTPUT TRISTATE ;
    USE SIGNAL ;
    ANTENNADIFFAREA 0.795200 ;
    PORT
      LAYER met2 ;
        RECT 544.730 546.000 545.010 550.000 ;
    END
  END mstream_o[531]
  PIN mstream_o[532]
    DIRECTION OUTPUT TRISTATE ;
    USE SIGNAL ;
    ANTENNADIFFAREA 0.795200 ;
    PORT
      LAYER met2 ;
        RECT 545.650 546.000 545.930 550.000 ;
    END
  END mstream_o[532]
  PIN mstream_o[533]
    DIRECTION OUTPUT TRISTATE ;
    USE SIGNAL ;
    ANTENNADIFFAREA 0.795200 ;
    PORT
      LAYER met2 ;
        RECT 546.570 546.000 546.850 550.000 ;
    END
  END mstream_o[533]
  PIN mstream_o[534]
    DIRECTION OUTPUT TRISTATE ;
    USE SIGNAL ;
    ANTENNADIFFAREA 0.795200 ;
    PORT
      LAYER met2 ;
        RECT 547.490 546.000 547.770 550.000 ;
    END
  END mstream_o[534]
  PIN mstream_o[535]
    DIRECTION OUTPUT TRISTATE ;
    USE SIGNAL ;
    ANTENNADIFFAREA 0.795200 ;
    PORT
      LAYER met2 ;
        RECT 548.410 546.000 548.690 550.000 ;
    END
  END mstream_o[535]
  PIN mstream_o[536]
    DIRECTION OUTPUT TRISTATE ;
    USE SIGNAL ;
    ANTENNADIFFAREA 0.795200 ;
    PORT
      LAYER met2 ;
        RECT 549.330 546.000 549.610 550.000 ;
    END
  END mstream_o[536]
  PIN mstream_o[537]
    DIRECTION OUTPUT TRISTATE ;
    USE SIGNAL ;
    ANTENNADIFFAREA 0.795200 ;
    PORT
      LAYER met2 ;
        RECT 550.250 546.000 550.530 550.000 ;
    END
  END mstream_o[537]
  PIN mstream_o[538]
    DIRECTION OUTPUT TRISTATE ;
    USE SIGNAL ;
    ANTENNADIFFAREA 0.795200 ;
    PORT
      LAYER met2 ;
        RECT 551.170 546.000 551.450 550.000 ;
    END
  END mstream_o[538]
  PIN mstream_o[539]
    DIRECTION OUTPUT TRISTATE ;
    USE SIGNAL ;
    ANTENNADIFFAREA 0.795200 ;
    PORT
      LAYER met2 ;
        RECT 552.090 546.000 552.370 550.000 ;
    END
  END mstream_o[539]
  PIN mstream_o[53]
    DIRECTION OUTPUT TRISTATE ;
    USE SIGNAL ;
    ANTENNADIFFAREA 0.795200 ;
    PORT
      LAYER met2 ;
        RECT 104.970 546.000 105.250 550.000 ;
    END
  END mstream_o[53]
  PIN mstream_o[540]
    DIRECTION OUTPUT TRISTATE ;
    USE SIGNAL ;
    ANTENNADIFFAREA 0.795200 ;
    PORT
      LAYER met2 ;
        RECT 553.010 546.000 553.290 550.000 ;
    END
  END mstream_o[540]
  PIN mstream_o[541]
    DIRECTION OUTPUT TRISTATE ;
    USE SIGNAL ;
    ANTENNADIFFAREA 0.795200 ;
    PORT
      LAYER met2 ;
        RECT 553.930 546.000 554.210 550.000 ;
    END
  END mstream_o[541]
  PIN mstream_o[542]
    DIRECTION OUTPUT TRISTATE ;
    USE SIGNAL ;
    ANTENNADIFFAREA 0.795200 ;
    PORT
      LAYER met2 ;
        RECT 554.850 546.000 555.130 550.000 ;
    END
  END mstream_o[542]
  PIN mstream_o[543]
    DIRECTION OUTPUT TRISTATE ;
    USE SIGNAL ;
    ANTENNADIFFAREA 0.795200 ;
    PORT
      LAYER met2 ;
        RECT 555.770 546.000 556.050 550.000 ;
    END
  END mstream_o[543]
  PIN mstream_o[544]
    DIRECTION OUTPUT TRISTATE ;
    USE SIGNAL ;
    ANTENNADIFFAREA 0.795200 ;
    PORT
      LAYER met2 ;
        RECT 556.690 546.000 556.970 550.000 ;
    END
  END mstream_o[544]
  PIN mstream_o[545]
    DIRECTION OUTPUT TRISTATE ;
    USE SIGNAL ;
    ANTENNADIFFAREA 0.795200 ;
    PORT
      LAYER met2 ;
        RECT 557.610 546.000 557.890 550.000 ;
    END
  END mstream_o[545]
  PIN mstream_o[546]
    DIRECTION OUTPUT TRISTATE ;
    USE SIGNAL ;
    ANTENNADIFFAREA 0.795200 ;
    PORT
      LAYER met2 ;
        RECT 558.530 546.000 558.810 550.000 ;
    END
  END mstream_o[546]
  PIN mstream_o[547]
    DIRECTION OUTPUT TRISTATE ;
    USE SIGNAL ;
    ANTENNADIFFAREA 0.795200 ;
    PORT
      LAYER met2 ;
        RECT 559.450 546.000 559.730 550.000 ;
    END
  END mstream_o[547]
  PIN mstream_o[548]
    DIRECTION OUTPUT TRISTATE ;
    USE SIGNAL ;
    ANTENNADIFFAREA 0.795200 ;
    PORT
      LAYER met2 ;
        RECT 560.370 546.000 560.650 550.000 ;
    END
  END mstream_o[548]
  PIN mstream_o[549]
    DIRECTION OUTPUT TRISTATE ;
    USE SIGNAL ;
    ANTENNADIFFAREA 0.795200 ;
    PORT
      LAYER met2 ;
        RECT 561.290 546.000 561.570 550.000 ;
    END
  END mstream_o[549]
  PIN mstream_o[54]
    DIRECTION OUTPUT TRISTATE ;
    USE SIGNAL ;
    ANTENNADIFFAREA 0.795200 ;
    PORT
      LAYER met2 ;
        RECT 105.890 546.000 106.170 550.000 ;
    END
  END mstream_o[54]
  PIN mstream_o[550]
    DIRECTION OUTPUT TRISTATE ;
    USE SIGNAL ;
    ANTENNADIFFAREA 0.795200 ;
    PORT
      LAYER met2 ;
        RECT 562.210 546.000 562.490 550.000 ;
    END
  END mstream_o[550]
  PIN mstream_o[551]
    DIRECTION OUTPUT TRISTATE ;
    USE SIGNAL ;
    ANTENNADIFFAREA 0.795200 ;
    PORT
      LAYER met2 ;
        RECT 563.130 546.000 563.410 550.000 ;
    END
  END mstream_o[551]
  PIN mstream_o[552]
    DIRECTION OUTPUT TRISTATE ;
    USE SIGNAL ;
    ANTENNADIFFAREA 0.795200 ;
    PORT
      LAYER met2 ;
        RECT 564.050 546.000 564.330 550.000 ;
    END
  END mstream_o[552]
  PIN mstream_o[553]
    DIRECTION OUTPUT TRISTATE ;
    USE SIGNAL ;
    ANTENNADIFFAREA 0.795200 ;
    PORT
      LAYER met2 ;
        RECT 564.970 546.000 565.250 550.000 ;
    END
  END mstream_o[553]
  PIN mstream_o[554]
    DIRECTION OUTPUT TRISTATE ;
    USE SIGNAL ;
    ANTENNADIFFAREA 0.795200 ;
    PORT
      LAYER met2 ;
        RECT 565.890 546.000 566.170 550.000 ;
    END
  END mstream_o[554]
  PIN mstream_o[555]
    DIRECTION OUTPUT TRISTATE ;
    USE SIGNAL ;
    ANTENNADIFFAREA 0.795200 ;
    PORT
      LAYER met2 ;
        RECT 566.810 546.000 567.090 550.000 ;
    END
  END mstream_o[555]
  PIN mstream_o[556]
    DIRECTION OUTPUT TRISTATE ;
    USE SIGNAL ;
    ANTENNADIFFAREA 0.795200 ;
    PORT
      LAYER met2 ;
        RECT 567.730 546.000 568.010 550.000 ;
    END
  END mstream_o[556]
  PIN mstream_o[557]
    DIRECTION OUTPUT TRISTATE ;
    USE SIGNAL ;
    ANTENNADIFFAREA 0.795200 ;
    PORT
      LAYER met2 ;
        RECT 568.650 546.000 568.930 550.000 ;
    END
  END mstream_o[557]
  PIN mstream_o[558]
    DIRECTION OUTPUT TRISTATE ;
    USE SIGNAL ;
    ANTENNADIFFAREA 0.795200 ;
    PORT
      LAYER met2 ;
        RECT 569.570 546.000 569.850 550.000 ;
    END
  END mstream_o[558]
  PIN mstream_o[559]
    DIRECTION OUTPUT TRISTATE ;
    USE SIGNAL ;
    ANTENNADIFFAREA 0.795200 ;
    PORT
      LAYER met2 ;
        RECT 570.490 546.000 570.770 550.000 ;
    END
  END mstream_o[559]
  PIN mstream_o[55]
    DIRECTION OUTPUT TRISTATE ;
    USE SIGNAL ;
    ANTENNADIFFAREA 0.795200 ;
    PORT
      LAYER met2 ;
        RECT 106.810 546.000 107.090 550.000 ;
    END
  END mstream_o[55]
  PIN mstream_o[560]
    DIRECTION OUTPUT TRISTATE ;
    USE SIGNAL ;
    ANTENNADIFFAREA 0.795200 ;
    PORT
      LAYER met2 ;
        RECT 571.410 546.000 571.690 550.000 ;
    END
  END mstream_o[560]
  PIN mstream_o[561]
    DIRECTION OUTPUT TRISTATE ;
    USE SIGNAL ;
    ANTENNADIFFAREA 0.795200 ;
    PORT
      LAYER met2 ;
        RECT 572.330 546.000 572.610 550.000 ;
    END
  END mstream_o[561]
  PIN mstream_o[562]
    DIRECTION OUTPUT TRISTATE ;
    USE SIGNAL ;
    ANTENNADIFFAREA 0.795200 ;
    PORT
      LAYER met2 ;
        RECT 573.250 546.000 573.530 550.000 ;
    END
  END mstream_o[562]
  PIN mstream_o[563]
    DIRECTION OUTPUT TRISTATE ;
    USE SIGNAL ;
    ANTENNADIFFAREA 0.795200 ;
    PORT
      LAYER met2 ;
        RECT 574.170 546.000 574.450 550.000 ;
    END
  END mstream_o[563]
  PIN mstream_o[564]
    DIRECTION OUTPUT TRISTATE ;
    USE SIGNAL ;
    ANTENNADIFFAREA 0.795200 ;
    PORT
      LAYER met2 ;
        RECT 575.090 546.000 575.370 550.000 ;
    END
  END mstream_o[564]
  PIN mstream_o[565]
    DIRECTION OUTPUT TRISTATE ;
    USE SIGNAL ;
    ANTENNADIFFAREA 0.795200 ;
    PORT
      LAYER met2 ;
        RECT 576.010 546.000 576.290 550.000 ;
    END
  END mstream_o[565]
  PIN mstream_o[566]
    DIRECTION OUTPUT TRISTATE ;
    USE SIGNAL ;
    ANTENNADIFFAREA 0.795200 ;
    PORT
      LAYER met2 ;
        RECT 576.930 546.000 577.210 550.000 ;
    END
  END mstream_o[566]
  PIN mstream_o[567]
    DIRECTION OUTPUT TRISTATE ;
    USE SIGNAL ;
    ANTENNADIFFAREA 0.795200 ;
    PORT
      LAYER met2 ;
        RECT 577.850 546.000 578.130 550.000 ;
    END
  END mstream_o[567]
  PIN mstream_o[568]
    DIRECTION OUTPUT TRISTATE ;
    USE SIGNAL ;
    ANTENNADIFFAREA 0.795200 ;
    PORT
      LAYER met2 ;
        RECT 578.770 546.000 579.050 550.000 ;
    END
  END mstream_o[568]
  PIN mstream_o[569]
    DIRECTION OUTPUT TRISTATE ;
    USE SIGNAL ;
    ANTENNADIFFAREA 0.795200 ;
    PORT
      LAYER met2 ;
        RECT 579.690 546.000 579.970 550.000 ;
    END
  END mstream_o[569]
  PIN mstream_o[56]
    DIRECTION OUTPUT TRISTATE ;
    USE SIGNAL ;
    ANTENNADIFFAREA 0.795200 ;
    PORT
      LAYER met2 ;
        RECT 107.730 546.000 108.010 550.000 ;
    END
  END mstream_o[56]
  PIN mstream_o[570]
    DIRECTION OUTPUT TRISTATE ;
    USE SIGNAL ;
    ANTENNADIFFAREA 0.795200 ;
    PORT
      LAYER met2 ;
        RECT 580.610 546.000 580.890 550.000 ;
    END
  END mstream_o[570]
  PIN mstream_o[571]
    DIRECTION OUTPUT TRISTATE ;
    USE SIGNAL ;
    ANTENNADIFFAREA 0.795200 ;
    PORT
      LAYER met2 ;
        RECT 581.530 546.000 581.810 550.000 ;
    END
  END mstream_o[571]
  PIN mstream_o[572]
    DIRECTION OUTPUT TRISTATE ;
    USE SIGNAL ;
    ANTENNADIFFAREA 0.795200 ;
    PORT
      LAYER met2 ;
        RECT 582.450 546.000 582.730 550.000 ;
    END
  END mstream_o[572]
  PIN mstream_o[573]
    DIRECTION OUTPUT TRISTATE ;
    USE SIGNAL ;
    ANTENNADIFFAREA 0.795200 ;
    PORT
      LAYER met2 ;
        RECT 583.370 546.000 583.650 550.000 ;
    END
  END mstream_o[573]
  PIN mstream_o[574]
    DIRECTION OUTPUT TRISTATE ;
    USE SIGNAL ;
    ANTENNADIFFAREA 0.795200 ;
    PORT
      LAYER met2 ;
        RECT 584.290 546.000 584.570 550.000 ;
    END
  END mstream_o[574]
  PIN mstream_o[575]
    DIRECTION OUTPUT TRISTATE ;
    USE SIGNAL ;
    ANTENNADIFFAREA 0.795200 ;
    PORT
      LAYER met2 ;
        RECT 585.210 546.000 585.490 550.000 ;
    END
  END mstream_o[575]
  PIN mstream_o[576]
    DIRECTION OUTPUT TRISTATE ;
    USE SIGNAL ;
    ANTENNADIFFAREA 0.795200 ;
    PORT
      LAYER met2 ;
        RECT 586.130 546.000 586.410 550.000 ;
    END
  END mstream_o[576]
  PIN mstream_o[577]
    DIRECTION OUTPUT TRISTATE ;
    USE SIGNAL ;
    ANTENNADIFFAREA 0.795200 ;
    PORT
      LAYER met2 ;
        RECT 587.050 546.000 587.330 550.000 ;
    END
  END mstream_o[577]
  PIN mstream_o[578]
    DIRECTION OUTPUT TRISTATE ;
    USE SIGNAL ;
    ANTENNADIFFAREA 0.795200 ;
    PORT
      LAYER met2 ;
        RECT 587.970 546.000 588.250 550.000 ;
    END
  END mstream_o[578]
  PIN mstream_o[579]
    DIRECTION OUTPUT TRISTATE ;
    USE SIGNAL ;
    ANTENNADIFFAREA 0.795200 ;
    PORT
      LAYER met2 ;
        RECT 588.890 546.000 589.170 550.000 ;
    END
  END mstream_o[579]
  PIN mstream_o[57]
    DIRECTION OUTPUT TRISTATE ;
    USE SIGNAL ;
    ANTENNADIFFAREA 0.795200 ;
    PORT
      LAYER met2 ;
        RECT 108.650 546.000 108.930 550.000 ;
    END
  END mstream_o[57]
  PIN mstream_o[580]
    DIRECTION OUTPUT TRISTATE ;
    USE SIGNAL ;
    ANTENNADIFFAREA 0.795200 ;
    PORT
      LAYER met2 ;
        RECT 589.810 546.000 590.090 550.000 ;
    END
  END mstream_o[580]
  PIN mstream_o[581]
    DIRECTION OUTPUT TRISTATE ;
    USE SIGNAL ;
    ANTENNADIFFAREA 0.795200 ;
    PORT
      LAYER met2 ;
        RECT 590.730 546.000 591.010 550.000 ;
    END
  END mstream_o[581]
  PIN mstream_o[582]
    DIRECTION OUTPUT TRISTATE ;
    USE SIGNAL ;
    ANTENNADIFFAREA 0.795200 ;
    PORT
      LAYER met2 ;
        RECT 591.650 546.000 591.930 550.000 ;
    END
  END mstream_o[582]
  PIN mstream_o[583]
    DIRECTION OUTPUT TRISTATE ;
    USE SIGNAL ;
    ANTENNADIFFAREA 0.795200 ;
    PORT
      LAYER met2 ;
        RECT 592.570 546.000 592.850 550.000 ;
    END
  END mstream_o[583]
  PIN mstream_o[584]
    DIRECTION OUTPUT TRISTATE ;
    USE SIGNAL ;
    ANTENNADIFFAREA 0.795200 ;
    PORT
      LAYER met2 ;
        RECT 593.490 546.000 593.770 550.000 ;
    END
  END mstream_o[584]
  PIN mstream_o[585]
    DIRECTION OUTPUT TRISTATE ;
    USE SIGNAL ;
    ANTENNADIFFAREA 0.795200 ;
    PORT
      LAYER met2 ;
        RECT 594.410 546.000 594.690 550.000 ;
    END
  END mstream_o[585]
  PIN mstream_o[586]
    DIRECTION OUTPUT TRISTATE ;
    USE SIGNAL ;
    ANTENNADIFFAREA 0.795200 ;
    PORT
      LAYER met2 ;
        RECT 595.330 546.000 595.610 550.000 ;
    END
  END mstream_o[586]
  PIN mstream_o[587]
    DIRECTION OUTPUT TRISTATE ;
    USE SIGNAL ;
    ANTENNADIFFAREA 0.795200 ;
    PORT
      LAYER met2 ;
        RECT 596.250 546.000 596.530 550.000 ;
    END
  END mstream_o[587]
  PIN mstream_o[588]
    DIRECTION OUTPUT TRISTATE ;
    USE SIGNAL ;
    ANTENNADIFFAREA 0.795200 ;
    PORT
      LAYER met2 ;
        RECT 597.170 546.000 597.450 550.000 ;
    END
  END mstream_o[588]
  PIN mstream_o[589]
    DIRECTION OUTPUT TRISTATE ;
    USE SIGNAL ;
    ANTENNADIFFAREA 0.795200 ;
    PORT
      LAYER met2 ;
        RECT 598.090 546.000 598.370 550.000 ;
    END
  END mstream_o[589]
  PIN mstream_o[58]
    DIRECTION OUTPUT TRISTATE ;
    USE SIGNAL ;
    ANTENNADIFFAREA 0.795200 ;
    PORT
      LAYER met2 ;
        RECT 109.570 546.000 109.850 550.000 ;
    END
  END mstream_o[58]
  PIN mstream_o[590]
    DIRECTION OUTPUT TRISTATE ;
    USE SIGNAL ;
    ANTENNADIFFAREA 0.795200 ;
    PORT
      LAYER met2 ;
        RECT 599.010 546.000 599.290 550.000 ;
    END
  END mstream_o[590]
  PIN mstream_o[591]
    DIRECTION OUTPUT TRISTATE ;
    USE SIGNAL ;
    ANTENNADIFFAREA 0.795200 ;
    PORT
      LAYER met2 ;
        RECT 599.930 546.000 600.210 550.000 ;
    END
  END mstream_o[591]
  PIN mstream_o[592]
    DIRECTION OUTPUT TRISTATE ;
    USE SIGNAL ;
    ANTENNADIFFAREA 0.795200 ;
    PORT
      LAYER met2 ;
        RECT 600.850 546.000 601.130 550.000 ;
    END
  END mstream_o[592]
  PIN mstream_o[593]
    DIRECTION OUTPUT TRISTATE ;
    USE SIGNAL ;
    ANTENNADIFFAREA 0.795200 ;
    PORT
      LAYER met2 ;
        RECT 601.770 546.000 602.050 550.000 ;
    END
  END mstream_o[593]
  PIN mstream_o[594]
    DIRECTION OUTPUT TRISTATE ;
    USE SIGNAL ;
    ANTENNADIFFAREA 0.795200 ;
    PORT
      LAYER met2 ;
        RECT 602.690 546.000 602.970 550.000 ;
    END
  END mstream_o[594]
  PIN mstream_o[595]
    DIRECTION OUTPUT TRISTATE ;
    USE SIGNAL ;
    ANTENNADIFFAREA 0.795200 ;
    PORT
      LAYER met2 ;
        RECT 603.610 546.000 603.890 550.000 ;
    END
  END mstream_o[595]
  PIN mstream_o[596]
    DIRECTION OUTPUT TRISTATE ;
    USE SIGNAL ;
    ANTENNADIFFAREA 0.795200 ;
    PORT
      LAYER met2 ;
        RECT 604.530 546.000 604.810 550.000 ;
    END
  END mstream_o[596]
  PIN mstream_o[597]
    DIRECTION OUTPUT TRISTATE ;
    USE SIGNAL ;
    ANTENNADIFFAREA 0.795200 ;
    PORT
      LAYER met2 ;
        RECT 605.450 546.000 605.730 550.000 ;
    END
  END mstream_o[597]
  PIN mstream_o[598]
    DIRECTION OUTPUT TRISTATE ;
    USE SIGNAL ;
    ANTENNADIFFAREA 0.795200 ;
    PORT
      LAYER met2 ;
        RECT 606.370 546.000 606.650 550.000 ;
    END
  END mstream_o[598]
  PIN mstream_o[599]
    DIRECTION OUTPUT TRISTATE ;
    USE SIGNAL ;
    ANTENNADIFFAREA 0.795200 ;
    PORT
      LAYER met2 ;
        RECT 607.290 546.000 607.570 550.000 ;
    END
  END mstream_o[599]
  PIN mstream_o[59]
    DIRECTION OUTPUT TRISTATE ;
    USE SIGNAL ;
    ANTENNADIFFAREA 0.795200 ;
    PORT
      LAYER met2 ;
        RECT 110.490 546.000 110.770 550.000 ;
    END
  END mstream_o[59]
  PIN mstream_o[5]
    DIRECTION OUTPUT TRISTATE ;
    USE SIGNAL ;
    ANTENNADIFFAREA 0.795200 ;
    PORT
      LAYER met2 ;
        RECT 60.810 546.000 61.090 550.000 ;
    END
  END mstream_o[5]
  PIN mstream_o[600]
    DIRECTION OUTPUT TRISTATE ;
    USE SIGNAL ;
    ANTENNADIFFAREA 0.795200 ;
    PORT
      LAYER met2 ;
        RECT 608.210 546.000 608.490 550.000 ;
    END
  END mstream_o[600]
  PIN mstream_o[601]
    DIRECTION OUTPUT TRISTATE ;
    USE SIGNAL ;
    ANTENNADIFFAREA 0.795200 ;
    PORT
      LAYER met2 ;
        RECT 609.130 546.000 609.410 550.000 ;
    END
  END mstream_o[601]
  PIN mstream_o[602]
    DIRECTION OUTPUT TRISTATE ;
    USE SIGNAL ;
    ANTENNADIFFAREA 0.795200 ;
    PORT
      LAYER met2 ;
        RECT 610.050 546.000 610.330 550.000 ;
    END
  END mstream_o[602]
  PIN mstream_o[603]
    DIRECTION OUTPUT TRISTATE ;
    USE SIGNAL ;
    ANTENNADIFFAREA 0.795200 ;
    PORT
      LAYER met2 ;
        RECT 610.970 546.000 611.250 550.000 ;
    END
  END mstream_o[603]
  PIN mstream_o[604]
    DIRECTION OUTPUT TRISTATE ;
    USE SIGNAL ;
    ANTENNADIFFAREA 0.795200 ;
    PORT
      LAYER met2 ;
        RECT 611.890 546.000 612.170 550.000 ;
    END
  END mstream_o[604]
  PIN mstream_o[605]
    DIRECTION OUTPUT TRISTATE ;
    USE SIGNAL ;
    ANTENNADIFFAREA 0.795200 ;
    PORT
      LAYER met2 ;
        RECT 612.810 546.000 613.090 550.000 ;
    END
  END mstream_o[605]
  PIN mstream_o[606]
    DIRECTION OUTPUT TRISTATE ;
    USE SIGNAL ;
    ANTENNADIFFAREA 0.795200 ;
    PORT
      LAYER met2 ;
        RECT 613.730 546.000 614.010 550.000 ;
    END
  END mstream_o[606]
  PIN mstream_o[607]
    DIRECTION OUTPUT TRISTATE ;
    USE SIGNAL ;
    ANTENNADIFFAREA 0.795200 ;
    PORT
      LAYER met2 ;
        RECT 614.650 546.000 614.930 550.000 ;
    END
  END mstream_o[607]
  PIN mstream_o[608]
    DIRECTION OUTPUT TRISTATE ;
    USE SIGNAL ;
    ANTENNADIFFAREA 0.795200 ;
    PORT
      LAYER met2 ;
        RECT 615.570 546.000 615.850 550.000 ;
    END
  END mstream_o[608]
  PIN mstream_o[609]
    DIRECTION OUTPUT TRISTATE ;
    USE SIGNAL ;
    ANTENNADIFFAREA 0.795200 ;
    PORT
      LAYER met2 ;
        RECT 616.490 546.000 616.770 550.000 ;
    END
  END mstream_o[609]
  PIN mstream_o[60]
    DIRECTION OUTPUT TRISTATE ;
    USE SIGNAL ;
    ANTENNADIFFAREA 0.795200 ;
    PORT
      LAYER met2 ;
        RECT 111.410 546.000 111.690 550.000 ;
    END
  END mstream_o[60]
  PIN mstream_o[610]
    DIRECTION OUTPUT TRISTATE ;
    USE SIGNAL ;
    ANTENNADIFFAREA 0.795200 ;
    PORT
      LAYER met2 ;
        RECT 617.410 546.000 617.690 550.000 ;
    END
  END mstream_o[610]
  PIN mstream_o[611]
    DIRECTION OUTPUT TRISTATE ;
    USE SIGNAL ;
    ANTENNADIFFAREA 0.795200 ;
    PORT
      LAYER met2 ;
        RECT 618.330 546.000 618.610 550.000 ;
    END
  END mstream_o[611]
  PIN mstream_o[612]
    DIRECTION OUTPUT TRISTATE ;
    USE SIGNAL ;
    ANTENNADIFFAREA 0.795200 ;
    PORT
      LAYER met2 ;
        RECT 619.250 546.000 619.530 550.000 ;
    END
  END mstream_o[612]
  PIN mstream_o[613]
    DIRECTION OUTPUT TRISTATE ;
    USE SIGNAL ;
    ANTENNADIFFAREA 0.795200 ;
    PORT
      LAYER met2 ;
        RECT 620.170 546.000 620.450 550.000 ;
    END
  END mstream_o[613]
  PIN mstream_o[614]
    DIRECTION OUTPUT TRISTATE ;
    USE SIGNAL ;
    ANTENNADIFFAREA 0.795200 ;
    PORT
      LAYER met2 ;
        RECT 621.090 546.000 621.370 550.000 ;
    END
  END mstream_o[614]
  PIN mstream_o[615]
    DIRECTION OUTPUT TRISTATE ;
    USE SIGNAL ;
    ANTENNADIFFAREA 0.795200 ;
    PORT
      LAYER met2 ;
        RECT 622.010 546.000 622.290 550.000 ;
    END
  END mstream_o[615]
  PIN mstream_o[616]
    DIRECTION OUTPUT TRISTATE ;
    USE SIGNAL ;
    ANTENNADIFFAREA 0.795200 ;
    PORT
      LAYER met2 ;
        RECT 622.930 546.000 623.210 550.000 ;
    END
  END mstream_o[616]
  PIN mstream_o[617]
    DIRECTION OUTPUT TRISTATE ;
    USE SIGNAL ;
    ANTENNADIFFAREA 0.795200 ;
    PORT
      LAYER met2 ;
        RECT 623.850 546.000 624.130 550.000 ;
    END
  END mstream_o[617]
  PIN mstream_o[618]
    DIRECTION OUTPUT TRISTATE ;
    USE SIGNAL ;
    ANTENNADIFFAREA 0.795200 ;
    PORT
      LAYER met2 ;
        RECT 624.770 546.000 625.050 550.000 ;
    END
  END mstream_o[618]
  PIN mstream_o[619]
    DIRECTION OUTPUT TRISTATE ;
    USE SIGNAL ;
    ANTENNADIFFAREA 0.795200 ;
    PORT
      LAYER met2 ;
        RECT 625.690 546.000 625.970 550.000 ;
    END
  END mstream_o[619]
  PIN mstream_o[61]
    DIRECTION OUTPUT TRISTATE ;
    USE SIGNAL ;
    ANTENNADIFFAREA 0.795200 ;
    PORT
      LAYER met2 ;
        RECT 112.330 546.000 112.610 550.000 ;
    END
  END mstream_o[61]
  PIN mstream_o[620]
    DIRECTION OUTPUT TRISTATE ;
    USE SIGNAL ;
    ANTENNADIFFAREA 0.795200 ;
    PORT
      LAYER met2 ;
        RECT 626.610 546.000 626.890 550.000 ;
    END
  END mstream_o[620]
  PIN mstream_o[621]
    DIRECTION OUTPUT TRISTATE ;
    USE SIGNAL ;
    ANTENNADIFFAREA 0.795200 ;
    PORT
      LAYER met2 ;
        RECT 627.530 546.000 627.810 550.000 ;
    END
  END mstream_o[621]
  PIN mstream_o[622]
    DIRECTION OUTPUT TRISTATE ;
    USE SIGNAL ;
    ANTENNADIFFAREA 0.795200 ;
    PORT
      LAYER met2 ;
        RECT 628.450 546.000 628.730 550.000 ;
    END
  END mstream_o[622]
  PIN mstream_o[623]
    DIRECTION OUTPUT TRISTATE ;
    USE SIGNAL ;
    ANTENNADIFFAREA 0.795200 ;
    PORT
      LAYER met2 ;
        RECT 629.370 546.000 629.650 550.000 ;
    END
  END mstream_o[623]
  PIN mstream_o[624]
    DIRECTION OUTPUT TRISTATE ;
    USE SIGNAL ;
    ANTENNADIFFAREA 0.795200 ;
    PORT
      LAYER met2 ;
        RECT 630.290 546.000 630.570 550.000 ;
    END
  END mstream_o[624]
  PIN mstream_o[625]
    DIRECTION OUTPUT TRISTATE ;
    USE SIGNAL ;
    ANTENNADIFFAREA 0.795200 ;
    PORT
      LAYER met2 ;
        RECT 631.210 546.000 631.490 550.000 ;
    END
  END mstream_o[625]
  PIN mstream_o[626]
    DIRECTION OUTPUT TRISTATE ;
    USE SIGNAL ;
    ANTENNADIFFAREA 0.795200 ;
    PORT
      LAYER met2 ;
        RECT 632.130 546.000 632.410 550.000 ;
    END
  END mstream_o[626]
  PIN mstream_o[627]
    DIRECTION OUTPUT TRISTATE ;
    USE SIGNAL ;
    ANTENNADIFFAREA 0.795200 ;
    PORT
      LAYER met2 ;
        RECT 633.050 546.000 633.330 550.000 ;
    END
  END mstream_o[627]
  PIN mstream_o[628]
    DIRECTION OUTPUT TRISTATE ;
    USE SIGNAL ;
    ANTENNADIFFAREA 0.795200 ;
    PORT
      LAYER met2 ;
        RECT 633.970 546.000 634.250 550.000 ;
    END
  END mstream_o[628]
  PIN mstream_o[629]
    DIRECTION OUTPUT TRISTATE ;
    USE SIGNAL ;
    ANTENNADIFFAREA 0.795200 ;
    PORT
      LAYER met2 ;
        RECT 634.890 546.000 635.170 550.000 ;
    END
  END mstream_o[629]
  PIN mstream_o[62]
    DIRECTION OUTPUT TRISTATE ;
    USE SIGNAL ;
    ANTENNADIFFAREA 0.795200 ;
    PORT
      LAYER met2 ;
        RECT 113.250 546.000 113.530 550.000 ;
    END
  END mstream_o[62]
  PIN mstream_o[630]
    DIRECTION OUTPUT TRISTATE ;
    USE SIGNAL ;
    ANTENNADIFFAREA 0.795200 ;
    PORT
      LAYER met2 ;
        RECT 635.810 546.000 636.090 550.000 ;
    END
  END mstream_o[630]
  PIN mstream_o[631]
    DIRECTION OUTPUT TRISTATE ;
    USE SIGNAL ;
    ANTENNADIFFAREA 0.795200 ;
    PORT
      LAYER met2 ;
        RECT 636.730 546.000 637.010 550.000 ;
    END
  END mstream_o[631]
  PIN mstream_o[632]
    DIRECTION OUTPUT TRISTATE ;
    USE SIGNAL ;
    ANTENNADIFFAREA 0.795200 ;
    PORT
      LAYER met2 ;
        RECT 637.650 546.000 637.930 550.000 ;
    END
  END mstream_o[632]
  PIN mstream_o[633]
    DIRECTION OUTPUT TRISTATE ;
    USE SIGNAL ;
    ANTENNADIFFAREA 0.795200 ;
    PORT
      LAYER met2 ;
        RECT 638.570 546.000 638.850 550.000 ;
    END
  END mstream_o[633]
  PIN mstream_o[634]
    DIRECTION OUTPUT TRISTATE ;
    USE SIGNAL ;
    ANTENNADIFFAREA 0.795200 ;
    PORT
      LAYER met2 ;
        RECT 639.490 546.000 639.770 550.000 ;
    END
  END mstream_o[634]
  PIN mstream_o[635]
    DIRECTION OUTPUT TRISTATE ;
    USE SIGNAL ;
    ANTENNADIFFAREA 0.795200 ;
    PORT
      LAYER met2 ;
        RECT 640.410 546.000 640.690 550.000 ;
    END
  END mstream_o[635]
  PIN mstream_o[636]
    DIRECTION OUTPUT TRISTATE ;
    USE SIGNAL ;
    ANTENNADIFFAREA 0.795200 ;
    PORT
      LAYER met2 ;
        RECT 641.330 546.000 641.610 550.000 ;
    END
  END mstream_o[636]
  PIN mstream_o[637]
    DIRECTION OUTPUT TRISTATE ;
    USE SIGNAL ;
    ANTENNADIFFAREA 0.795200 ;
    PORT
      LAYER met2 ;
        RECT 642.250 546.000 642.530 550.000 ;
    END
  END mstream_o[637]
  PIN mstream_o[638]
    DIRECTION OUTPUT TRISTATE ;
    USE SIGNAL ;
    ANTENNADIFFAREA 0.795200 ;
    PORT
      LAYER met2 ;
        RECT 643.170 546.000 643.450 550.000 ;
    END
  END mstream_o[638]
  PIN mstream_o[639]
    DIRECTION OUTPUT TRISTATE ;
    USE SIGNAL ;
    ANTENNADIFFAREA 0.795200 ;
    PORT
      LAYER met2 ;
        RECT 644.090 546.000 644.370 550.000 ;
    END
  END mstream_o[639]
  PIN mstream_o[63]
    DIRECTION OUTPUT TRISTATE ;
    USE SIGNAL ;
    ANTENNADIFFAREA 0.795200 ;
    PORT
      LAYER met2 ;
        RECT 114.170 546.000 114.450 550.000 ;
    END
  END mstream_o[63]
  PIN mstream_o[640]
    DIRECTION OUTPUT TRISTATE ;
    USE SIGNAL ;
    ANTENNADIFFAREA 0.795200 ;
    PORT
      LAYER met2 ;
        RECT 645.010 546.000 645.290 550.000 ;
    END
  END mstream_o[640]
  PIN mstream_o[641]
    DIRECTION OUTPUT TRISTATE ;
    USE SIGNAL ;
    ANTENNADIFFAREA 0.795200 ;
    PORT
      LAYER met2 ;
        RECT 645.930 546.000 646.210 550.000 ;
    END
  END mstream_o[641]
  PIN mstream_o[642]
    DIRECTION OUTPUT TRISTATE ;
    USE SIGNAL ;
    ANTENNADIFFAREA 0.795200 ;
    PORT
      LAYER met2 ;
        RECT 646.850 546.000 647.130 550.000 ;
    END
  END mstream_o[642]
  PIN mstream_o[643]
    DIRECTION OUTPUT TRISTATE ;
    USE SIGNAL ;
    ANTENNADIFFAREA 0.795200 ;
    PORT
      LAYER met2 ;
        RECT 647.770 546.000 648.050 550.000 ;
    END
  END mstream_o[643]
  PIN mstream_o[644]
    DIRECTION OUTPUT TRISTATE ;
    USE SIGNAL ;
    ANTENNADIFFAREA 0.795200 ;
    PORT
      LAYER met2 ;
        RECT 648.690 546.000 648.970 550.000 ;
    END
  END mstream_o[644]
  PIN mstream_o[645]
    DIRECTION OUTPUT TRISTATE ;
    USE SIGNAL ;
    ANTENNADIFFAREA 0.795200 ;
    PORT
      LAYER met2 ;
        RECT 649.610 546.000 649.890 550.000 ;
    END
  END mstream_o[645]
  PIN mstream_o[646]
    DIRECTION OUTPUT TRISTATE ;
    USE SIGNAL ;
    ANTENNADIFFAREA 0.795200 ;
    PORT
      LAYER met2 ;
        RECT 650.530 546.000 650.810 550.000 ;
    END
  END mstream_o[646]
  PIN mstream_o[647]
    DIRECTION OUTPUT TRISTATE ;
    USE SIGNAL ;
    ANTENNADIFFAREA 0.795200 ;
    PORT
      LAYER met2 ;
        RECT 651.450 546.000 651.730 550.000 ;
    END
  END mstream_o[647]
  PIN mstream_o[648]
    DIRECTION OUTPUT TRISTATE ;
    USE SIGNAL ;
    ANTENNADIFFAREA 0.795200 ;
    PORT
      LAYER met2 ;
        RECT 652.370 546.000 652.650 550.000 ;
    END
  END mstream_o[648]
  PIN mstream_o[649]
    DIRECTION OUTPUT TRISTATE ;
    USE SIGNAL ;
    ANTENNADIFFAREA 0.795200 ;
    PORT
      LAYER met2 ;
        RECT 653.290 546.000 653.570 550.000 ;
    END
  END mstream_o[649]
  PIN mstream_o[64]
    DIRECTION OUTPUT TRISTATE ;
    USE SIGNAL ;
    ANTENNADIFFAREA 0.795200 ;
    PORT
      LAYER met2 ;
        RECT 115.090 546.000 115.370 550.000 ;
    END
  END mstream_o[64]
  PIN mstream_o[650]
    DIRECTION OUTPUT TRISTATE ;
    USE SIGNAL ;
    ANTENNADIFFAREA 0.795200 ;
    PORT
      LAYER met2 ;
        RECT 654.210 546.000 654.490 550.000 ;
    END
  END mstream_o[650]
  PIN mstream_o[651]
    DIRECTION OUTPUT TRISTATE ;
    USE SIGNAL ;
    ANTENNADIFFAREA 0.795200 ;
    PORT
      LAYER met2 ;
        RECT 655.130 546.000 655.410 550.000 ;
    END
  END mstream_o[651]
  PIN mstream_o[652]
    DIRECTION OUTPUT TRISTATE ;
    USE SIGNAL ;
    ANTENNADIFFAREA 0.795200 ;
    PORT
      LAYER met2 ;
        RECT 656.050 546.000 656.330 550.000 ;
    END
  END mstream_o[652]
  PIN mstream_o[653]
    DIRECTION OUTPUT TRISTATE ;
    USE SIGNAL ;
    ANTENNADIFFAREA 0.795200 ;
    PORT
      LAYER met2 ;
        RECT 656.970 546.000 657.250 550.000 ;
    END
  END mstream_o[653]
  PIN mstream_o[654]
    DIRECTION OUTPUT TRISTATE ;
    USE SIGNAL ;
    ANTENNADIFFAREA 0.795200 ;
    PORT
      LAYER met2 ;
        RECT 657.890 546.000 658.170 550.000 ;
    END
  END mstream_o[654]
  PIN mstream_o[655]
    DIRECTION OUTPUT TRISTATE ;
    USE SIGNAL ;
    ANTENNADIFFAREA 0.795200 ;
    PORT
      LAYER met2 ;
        RECT 658.810 546.000 659.090 550.000 ;
    END
  END mstream_o[655]
  PIN mstream_o[656]
    DIRECTION OUTPUT TRISTATE ;
    USE SIGNAL ;
    ANTENNADIFFAREA 0.795200 ;
    PORT
      LAYER met2 ;
        RECT 659.730 546.000 660.010 550.000 ;
    END
  END mstream_o[656]
  PIN mstream_o[657]
    DIRECTION OUTPUT TRISTATE ;
    USE SIGNAL ;
    ANTENNADIFFAREA 0.795200 ;
    PORT
      LAYER met2 ;
        RECT 660.650 546.000 660.930 550.000 ;
    END
  END mstream_o[657]
  PIN mstream_o[658]
    DIRECTION OUTPUT TRISTATE ;
    USE SIGNAL ;
    ANTENNADIFFAREA 0.795200 ;
    PORT
      LAYER met2 ;
        RECT 661.570 546.000 661.850 550.000 ;
    END
  END mstream_o[658]
  PIN mstream_o[659]
    DIRECTION OUTPUT TRISTATE ;
    USE SIGNAL ;
    ANTENNADIFFAREA 0.795200 ;
    PORT
      LAYER met2 ;
        RECT 662.490 546.000 662.770 550.000 ;
    END
  END mstream_o[659]
  PIN mstream_o[65]
    DIRECTION OUTPUT TRISTATE ;
    USE SIGNAL ;
    ANTENNADIFFAREA 0.795200 ;
    PORT
      LAYER met2 ;
        RECT 116.010 546.000 116.290 550.000 ;
    END
  END mstream_o[65]
  PIN mstream_o[660]
    DIRECTION OUTPUT TRISTATE ;
    USE SIGNAL ;
    ANTENNADIFFAREA 0.795200 ;
    PORT
      LAYER met2 ;
        RECT 663.410 546.000 663.690 550.000 ;
    END
  END mstream_o[660]
  PIN mstream_o[661]
    DIRECTION OUTPUT TRISTATE ;
    USE SIGNAL ;
    ANTENNADIFFAREA 0.795200 ;
    PORT
      LAYER met2 ;
        RECT 664.330 546.000 664.610 550.000 ;
    END
  END mstream_o[661]
  PIN mstream_o[662]
    DIRECTION OUTPUT TRISTATE ;
    USE SIGNAL ;
    ANTENNADIFFAREA 0.795200 ;
    PORT
      LAYER met2 ;
        RECT 665.250 546.000 665.530 550.000 ;
    END
  END mstream_o[662]
  PIN mstream_o[663]
    DIRECTION OUTPUT TRISTATE ;
    USE SIGNAL ;
    ANTENNADIFFAREA 0.795200 ;
    PORT
      LAYER met2 ;
        RECT 666.170 546.000 666.450 550.000 ;
    END
  END mstream_o[663]
  PIN mstream_o[664]
    DIRECTION OUTPUT TRISTATE ;
    USE SIGNAL ;
    ANTENNADIFFAREA 0.795200 ;
    PORT
      LAYER met2 ;
        RECT 667.090 546.000 667.370 550.000 ;
    END
  END mstream_o[664]
  PIN mstream_o[665]
    DIRECTION OUTPUT TRISTATE ;
    USE SIGNAL ;
    ANTENNADIFFAREA 0.795200 ;
    PORT
      LAYER met2 ;
        RECT 668.010 546.000 668.290 550.000 ;
    END
  END mstream_o[665]
  PIN mstream_o[666]
    DIRECTION OUTPUT TRISTATE ;
    USE SIGNAL ;
    ANTENNADIFFAREA 0.795200 ;
    PORT
      LAYER met2 ;
        RECT 668.930 546.000 669.210 550.000 ;
    END
  END mstream_o[666]
  PIN mstream_o[667]
    DIRECTION OUTPUT TRISTATE ;
    USE SIGNAL ;
    ANTENNADIFFAREA 0.795200 ;
    PORT
      LAYER met2 ;
        RECT 669.850 546.000 670.130 550.000 ;
    END
  END mstream_o[667]
  PIN mstream_o[668]
    DIRECTION OUTPUT TRISTATE ;
    USE SIGNAL ;
    ANTENNADIFFAREA 0.795200 ;
    PORT
      LAYER met2 ;
        RECT 670.770 546.000 671.050 550.000 ;
    END
  END mstream_o[668]
  PIN mstream_o[669]
    DIRECTION OUTPUT TRISTATE ;
    USE SIGNAL ;
    ANTENNADIFFAREA 0.795200 ;
    PORT
      LAYER met2 ;
        RECT 671.690 546.000 671.970 550.000 ;
    END
  END mstream_o[669]
  PIN mstream_o[66]
    DIRECTION OUTPUT TRISTATE ;
    USE SIGNAL ;
    ANTENNADIFFAREA 0.795200 ;
    PORT
      LAYER met2 ;
        RECT 116.930 546.000 117.210 550.000 ;
    END
  END mstream_o[66]
  PIN mstream_o[670]
    DIRECTION OUTPUT TRISTATE ;
    USE SIGNAL ;
    ANTENNADIFFAREA 0.795200 ;
    PORT
      LAYER met2 ;
        RECT 672.610 546.000 672.890 550.000 ;
    END
  END mstream_o[670]
  PIN mstream_o[671]
    DIRECTION OUTPUT TRISTATE ;
    USE SIGNAL ;
    ANTENNADIFFAREA 0.795200 ;
    PORT
      LAYER met2 ;
        RECT 673.530 546.000 673.810 550.000 ;
    END
  END mstream_o[671]
  PIN mstream_o[672]
    DIRECTION OUTPUT TRISTATE ;
    USE SIGNAL ;
    ANTENNADIFFAREA 0.795200 ;
    PORT
      LAYER met2 ;
        RECT 674.450 546.000 674.730 550.000 ;
    END
  END mstream_o[672]
  PIN mstream_o[673]
    DIRECTION OUTPUT TRISTATE ;
    USE SIGNAL ;
    ANTENNADIFFAREA 0.795200 ;
    PORT
      LAYER met2 ;
        RECT 675.370 546.000 675.650 550.000 ;
    END
  END mstream_o[673]
  PIN mstream_o[674]
    DIRECTION OUTPUT TRISTATE ;
    USE SIGNAL ;
    ANTENNADIFFAREA 0.795200 ;
    PORT
      LAYER met2 ;
        RECT 676.290 546.000 676.570 550.000 ;
    END
  END mstream_o[674]
  PIN mstream_o[675]
    DIRECTION OUTPUT TRISTATE ;
    USE SIGNAL ;
    ANTENNADIFFAREA 0.795200 ;
    PORT
      LAYER met2 ;
        RECT 677.210 546.000 677.490 550.000 ;
    END
  END mstream_o[675]
  PIN mstream_o[676]
    DIRECTION OUTPUT TRISTATE ;
    USE SIGNAL ;
    ANTENNADIFFAREA 0.795200 ;
    PORT
      LAYER met2 ;
        RECT 678.130 546.000 678.410 550.000 ;
    END
  END mstream_o[676]
  PIN mstream_o[677]
    DIRECTION OUTPUT TRISTATE ;
    USE SIGNAL ;
    ANTENNADIFFAREA 0.795200 ;
    PORT
      LAYER met2 ;
        RECT 679.050 546.000 679.330 550.000 ;
    END
  END mstream_o[677]
  PIN mstream_o[678]
    DIRECTION OUTPUT TRISTATE ;
    USE SIGNAL ;
    ANTENNADIFFAREA 0.795200 ;
    PORT
      LAYER met2 ;
        RECT 679.970 546.000 680.250 550.000 ;
    END
  END mstream_o[678]
  PIN mstream_o[679]
    DIRECTION OUTPUT TRISTATE ;
    USE SIGNAL ;
    ANTENNADIFFAREA 0.795200 ;
    PORT
      LAYER met2 ;
        RECT 680.890 546.000 681.170 550.000 ;
    END
  END mstream_o[679]
  PIN mstream_o[67]
    DIRECTION OUTPUT TRISTATE ;
    USE SIGNAL ;
    ANTENNADIFFAREA 0.795200 ;
    PORT
      LAYER met2 ;
        RECT 117.850 546.000 118.130 550.000 ;
    END
  END mstream_o[67]
  PIN mstream_o[680]
    DIRECTION OUTPUT TRISTATE ;
    USE SIGNAL ;
    ANTENNADIFFAREA 0.795200 ;
    PORT
      LAYER met2 ;
        RECT 681.810 546.000 682.090 550.000 ;
    END
  END mstream_o[680]
  PIN mstream_o[681]
    DIRECTION OUTPUT TRISTATE ;
    USE SIGNAL ;
    ANTENNADIFFAREA 0.795200 ;
    PORT
      LAYER met2 ;
        RECT 682.730 546.000 683.010 550.000 ;
    END
  END mstream_o[681]
  PIN mstream_o[682]
    DIRECTION OUTPUT TRISTATE ;
    USE SIGNAL ;
    ANTENNADIFFAREA 0.795200 ;
    PORT
      LAYER met2 ;
        RECT 683.650 546.000 683.930 550.000 ;
    END
  END mstream_o[682]
  PIN mstream_o[683]
    DIRECTION OUTPUT TRISTATE ;
    USE SIGNAL ;
    ANTENNADIFFAREA 0.795200 ;
    PORT
      LAYER met2 ;
        RECT 684.570 546.000 684.850 550.000 ;
    END
  END mstream_o[683]
  PIN mstream_o[684]
    DIRECTION OUTPUT TRISTATE ;
    USE SIGNAL ;
    ANTENNADIFFAREA 0.795200 ;
    PORT
      LAYER met2 ;
        RECT 685.490 546.000 685.770 550.000 ;
    END
  END mstream_o[684]
  PIN mstream_o[685]
    DIRECTION OUTPUT TRISTATE ;
    USE SIGNAL ;
    ANTENNADIFFAREA 0.795200 ;
    PORT
      LAYER met2 ;
        RECT 686.410 546.000 686.690 550.000 ;
    END
  END mstream_o[685]
  PIN mstream_o[686]
    DIRECTION OUTPUT TRISTATE ;
    USE SIGNAL ;
    ANTENNADIFFAREA 0.795200 ;
    PORT
      LAYER met2 ;
        RECT 687.330 546.000 687.610 550.000 ;
    END
  END mstream_o[686]
  PIN mstream_o[687]
    DIRECTION OUTPUT TRISTATE ;
    USE SIGNAL ;
    ANTENNADIFFAREA 0.795200 ;
    PORT
      LAYER met2 ;
        RECT 688.250 546.000 688.530 550.000 ;
    END
  END mstream_o[687]
  PIN mstream_o[688]
    DIRECTION OUTPUT TRISTATE ;
    USE SIGNAL ;
    ANTENNADIFFAREA 0.795200 ;
    PORT
      LAYER met2 ;
        RECT 689.170 546.000 689.450 550.000 ;
    END
  END mstream_o[688]
  PIN mstream_o[689]
    DIRECTION OUTPUT TRISTATE ;
    USE SIGNAL ;
    ANTENNADIFFAREA 0.795200 ;
    PORT
      LAYER met2 ;
        RECT 690.090 546.000 690.370 550.000 ;
    END
  END mstream_o[689]
  PIN mstream_o[68]
    DIRECTION OUTPUT TRISTATE ;
    USE SIGNAL ;
    ANTENNADIFFAREA 0.795200 ;
    PORT
      LAYER met2 ;
        RECT 118.770 546.000 119.050 550.000 ;
    END
  END mstream_o[68]
  PIN mstream_o[690]
    DIRECTION OUTPUT TRISTATE ;
    USE SIGNAL ;
    ANTENNADIFFAREA 0.795200 ;
    PORT
      LAYER met2 ;
        RECT 691.010 546.000 691.290 550.000 ;
    END
  END mstream_o[690]
  PIN mstream_o[691]
    DIRECTION OUTPUT TRISTATE ;
    USE SIGNAL ;
    ANTENNADIFFAREA 0.795200 ;
    PORT
      LAYER met2 ;
        RECT 691.930 546.000 692.210 550.000 ;
    END
  END mstream_o[691]
  PIN mstream_o[692]
    DIRECTION OUTPUT TRISTATE ;
    USE SIGNAL ;
    ANTENNADIFFAREA 0.795200 ;
    PORT
      LAYER met2 ;
        RECT 692.850 546.000 693.130 550.000 ;
    END
  END mstream_o[692]
  PIN mstream_o[693]
    DIRECTION OUTPUT TRISTATE ;
    USE SIGNAL ;
    ANTENNADIFFAREA 0.795200 ;
    PORT
      LAYER met2 ;
        RECT 693.770 546.000 694.050 550.000 ;
    END
  END mstream_o[693]
  PIN mstream_o[694]
    DIRECTION OUTPUT TRISTATE ;
    USE SIGNAL ;
    ANTENNADIFFAREA 0.795200 ;
    PORT
      LAYER met2 ;
        RECT 694.690 546.000 694.970 550.000 ;
    END
  END mstream_o[694]
  PIN mstream_o[695]
    DIRECTION OUTPUT TRISTATE ;
    USE SIGNAL ;
    ANTENNADIFFAREA 0.795200 ;
    PORT
      LAYER met2 ;
        RECT 695.610 546.000 695.890 550.000 ;
    END
  END mstream_o[695]
  PIN mstream_o[696]
    DIRECTION OUTPUT TRISTATE ;
    USE SIGNAL ;
    ANTENNADIFFAREA 0.795200 ;
    PORT
      LAYER met2 ;
        RECT 696.530 546.000 696.810 550.000 ;
    END
  END mstream_o[696]
  PIN mstream_o[697]
    DIRECTION OUTPUT TRISTATE ;
    USE SIGNAL ;
    ANTENNADIFFAREA 0.795200 ;
    PORT
      LAYER met2 ;
        RECT 697.450 546.000 697.730 550.000 ;
    END
  END mstream_o[697]
  PIN mstream_o[698]
    DIRECTION OUTPUT TRISTATE ;
    USE SIGNAL ;
    ANTENNADIFFAREA 0.795200 ;
    PORT
      LAYER met2 ;
        RECT 698.370 546.000 698.650 550.000 ;
    END
  END mstream_o[698]
  PIN mstream_o[699]
    DIRECTION OUTPUT TRISTATE ;
    USE SIGNAL ;
    ANTENNADIFFAREA 0.795200 ;
    PORT
      LAYER met2 ;
        RECT 699.290 546.000 699.570 550.000 ;
    END
  END mstream_o[699]
  PIN mstream_o[69]
    DIRECTION OUTPUT TRISTATE ;
    USE SIGNAL ;
    ANTENNADIFFAREA 0.795200 ;
    PORT
      LAYER met2 ;
        RECT 119.690 546.000 119.970 550.000 ;
    END
  END mstream_o[69]
  PIN mstream_o[6]
    DIRECTION OUTPUT TRISTATE ;
    USE SIGNAL ;
    ANTENNADIFFAREA 0.795200 ;
    PORT
      LAYER met2 ;
        RECT 61.730 546.000 62.010 550.000 ;
    END
  END mstream_o[6]
  PIN mstream_o[700]
    DIRECTION OUTPUT TRISTATE ;
    USE SIGNAL ;
    ANTENNADIFFAREA 0.795200 ;
    PORT
      LAYER met2 ;
        RECT 700.210 546.000 700.490 550.000 ;
    END
  END mstream_o[700]
  PIN mstream_o[701]
    DIRECTION OUTPUT TRISTATE ;
    USE SIGNAL ;
    ANTENNADIFFAREA 0.795200 ;
    PORT
      LAYER met2 ;
        RECT 701.130 546.000 701.410 550.000 ;
    END
  END mstream_o[701]
  PIN mstream_o[702]
    DIRECTION OUTPUT TRISTATE ;
    USE SIGNAL ;
    ANTENNADIFFAREA 0.795200 ;
    PORT
      LAYER met2 ;
        RECT 702.050 546.000 702.330 550.000 ;
    END
  END mstream_o[702]
  PIN mstream_o[703]
    DIRECTION OUTPUT TRISTATE ;
    USE SIGNAL ;
    ANTENNADIFFAREA 0.795200 ;
    PORT
      LAYER met2 ;
        RECT 702.970 546.000 703.250 550.000 ;
    END
  END mstream_o[703]
  PIN mstream_o[704]
    DIRECTION OUTPUT TRISTATE ;
    USE SIGNAL ;
    ANTENNADIFFAREA 0.795200 ;
    PORT
      LAYER met2 ;
        RECT 703.890 546.000 704.170 550.000 ;
    END
  END mstream_o[704]
  PIN mstream_o[705]
    DIRECTION OUTPUT TRISTATE ;
    USE SIGNAL ;
    ANTENNADIFFAREA 0.795200 ;
    PORT
      LAYER met2 ;
        RECT 704.810 546.000 705.090 550.000 ;
    END
  END mstream_o[705]
  PIN mstream_o[706]
    DIRECTION OUTPUT TRISTATE ;
    USE SIGNAL ;
    ANTENNADIFFAREA 0.795200 ;
    PORT
      LAYER met2 ;
        RECT 705.730 546.000 706.010 550.000 ;
    END
  END mstream_o[706]
  PIN mstream_o[707]
    DIRECTION OUTPUT TRISTATE ;
    USE SIGNAL ;
    ANTENNADIFFAREA 0.795200 ;
    PORT
      LAYER met2 ;
        RECT 706.650 546.000 706.930 550.000 ;
    END
  END mstream_o[707]
  PIN mstream_o[708]
    DIRECTION OUTPUT TRISTATE ;
    USE SIGNAL ;
    ANTENNADIFFAREA 0.795200 ;
    PORT
      LAYER met2 ;
        RECT 707.570 546.000 707.850 550.000 ;
    END
  END mstream_o[708]
  PIN mstream_o[709]
    DIRECTION OUTPUT TRISTATE ;
    USE SIGNAL ;
    ANTENNADIFFAREA 0.795200 ;
    PORT
      LAYER met2 ;
        RECT 708.490 546.000 708.770 550.000 ;
    END
  END mstream_o[709]
  PIN mstream_o[70]
    DIRECTION OUTPUT TRISTATE ;
    USE SIGNAL ;
    ANTENNADIFFAREA 0.795200 ;
    PORT
      LAYER met2 ;
        RECT 120.610 546.000 120.890 550.000 ;
    END
  END mstream_o[70]
  PIN mstream_o[710]
    DIRECTION OUTPUT TRISTATE ;
    USE SIGNAL ;
    ANTENNADIFFAREA 0.795200 ;
    PORT
      LAYER met2 ;
        RECT 709.410 546.000 709.690 550.000 ;
    END
  END mstream_o[710]
  PIN mstream_o[711]
    DIRECTION OUTPUT TRISTATE ;
    USE SIGNAL ;
    ANTENNADIFFAREA 0.795200 ;
    PORT
      LAYER met2 ;
        RECT 710.330 546.000 710.610 550.000 ;
    END
  END mstream_o[711]
  PIN mstream_o[712]
    DIRECTION OUTPUT TRISTATE ;
    USE SIGNAL ;
    ANTENNADIFFAREA 0.795200 ;
    PORT
      LAYER met2 ;
        RECT 711.250 546.000 711.530 550.000 ;
    END
  END mstream_o[712]
  PIN mstream_o[713]
    DIRECTION OUTPUT TRISTATE ;
    USE SIGNAL ;
    ANTENNADIFFAREA 0.795200 ;
    PORT
      LAYER met2 ;
        RECT 712.170 546.000 712.450 550.000 ;
    END
  END mstream_o[713]
  PIN mstream_o[714]
    DIRECTION OUTPUT TRISTATE ;
    USE SIGNAL ;
    ANTENNADIFFAREA 0.795200 ;
    PORT
      LAYER met2 ;
        RECT 713.090 546.000 713.370 550.000 ;
    END
  END mstream_o[714]
  PIN mstream_o[715]
    DIRECTION OUTPUT TRISTATE ;
    USE SIGNAL ;
    ANTENNADIFFAREA 0.795200 ;
    PORT
      LAYER met2 ;
        RECT 714.010 546.000 714.290 550.000 ;
    END
  END mstream_o[715]
  PIN mstream_o[716]
    DIRECTION OUTPUT TRISTATE ;
    USE SIGNAL ;
    ANTENNADIFFAREA 0.795200 ;
    PORT
      LAYER met2 ;
        RECT 714.930 546.000 715.210 550.000 ;
    END
  END mstream_o[716]
  PIN mstream_o[717]
    DIRECTION OUTPUT TRISTATE ;
    USE SIGNAL ;
    ANTENNADIFFAREA 0.795200 ;
    PORT
      LAYER met2 ;
        RECT 715.850 546.000 716.130 550.000 ;
    END
  END mstream_o[717]
  PIN mstream_o[718]
    DIRECTION OUTPUT TRISTATE ;
    USE SIGNAL ;
    ANTENNADIFFAREA 0.795200 ;
    PORT
      LAYER met2 ;
        RECT 716.770 546.000 717.050 550.000 ;
    END
  END mstream_o[718]
  PIN mstream_o[719]
    DIRECTION OUTPUT TRISTATE ;
    USE SIGNAL ;
    ANTENNADIFFAREA 0.795200 ;
    PORT
      LAYER met2 ;
        RECT 717.690 546.000 717.970 550.000 ;
    END
  END mstream_o[719]
  PIN mstream_o[71]
    DIRECTION OUTPUT TRISTATE ;
    USE SIGNAL ;
    ANTENNADIFFAREA 0.795200 ;
    PORT
      LAYER met2 ;
        RECT 121.530 546.000 121.810 550.000 ;
    END
  END mstream_o[71]
  PIN mstream_o[720]
    DIRECTION OUTPUT TRISTATE ;
    USE SIGNAL ;
    ANTENNADIFFAREA 0.795200 ;
    PORT
      LAYER met2 ;
        RECT 718.610 546.000 718.890 550.000 ;
    END
  END mstream_o[720]
  PIN mstream_o[721]
    DIRECTION OUTPUT TRISTATE ;
    USE SIGNAL ;
    ANTENNADIFFAREA 0.795200 ;
    PORT
      LAYER met2 ;
        RECT 719.530 546.000 719.810 550.000 ;
    END
  END mstream_o[721]
  PIN mstream_o[722]
    DIRECTION OUTPUT TRISTATE ;
    USE SIGNAL ;
    ANTENNADIFFAREA 0.795200 ;
    PORT
      LAYER met2 ;
        RECT 720.450 546.000 720.730 550.000 ;
    END
  END mstream_o[722]
  PIN mstream_o[723]
    DIRECTION OUTPUT TRISTATE ;
    USE SIGNAL ;
    ANTENNADIFFAREA 0.795200 ;
    PORT
      LAYER met2 ;
        RECT 721.370 546.000 721.650 550.000 ;
    END
  END mstream_o[723]
  PIN mstream_o[724]
    DIRECTION OUTPUT TRISTATE ;
    USE SIGNAL ;
    ANTENNADIFFAREA 0.795200 ;
    PORT
      LAYER met2 ;
        RECT 722.290 546.000 722.570 550.000 ;
    END
  END mstream_o[724]
  PIN mstream_o[725]
    DIRECTION OUTPUT TRISTATE ;
    USE SIGNAL ;
    ANTENNADIFFAREA 0.795200 ;
    PORT
      LAYER met2 ;
        RECT 723.210 546.000 723.490 550.000 ;
    END
  END mstream_o[725]
  PIN mstream_o[726]
    DIRECTION OUTPUT TRISTATE ;
    USE SIGNAL ;
    ANTENNADIFFAREA 0.795200 ;
    PORT
      LAYER met2 ;
        RECT 724.130 546.000 724.410 550.000 ;
    END
  END mstream_o[726]
  PIN mstream_o[727]
    DIRECTION OUTPUT TRISTATE ;
    USE SIGNAL ;
    ANTENNADIFFAREA 0.795200 ;
    PORT
      LAYER met2 ;
        RECT 725.050 546.000 725.330 550.000 ;
    END
  END mstream_o[727]
  PIN mstream_o[728]
    DIRECTION OUTPUT TRISTATE ;
    USE SIGNAL ;
    ANTENNADIFFAREA 0.795200 ;
    PORT
      LAYER met2 ;
        RECT 725.970 546.000 726.250 550.000 ;
    END
  END mstream_o[728]
  PIN mstream_o[729]
    DIRECTION OUTPUT TRISTATE ;
    USE SIGNAL ;
    ANTENNADIFFAREA 0.795200 ;
    PORT
      LAYER met2 ;
        RECT 726.890 546.000 727.170 550.000 ;
    END
  END mstream_o[729]
  PIN mstream_o[72]
    DIRECTION OUTPUT TRISTATE ;
    USE SIGNAL ;
    ANTENNADIFFAREA 0.795200 ;
    PORT
      LAYER met2 ;
        RECT 122.450 546.000 122.730 550.000 ;
    END
  END mstream_o[72]
  PIN mstream_o[730]
    DIRECTION OUTPUT TRISTATE ;
    USE SIGNAL ;
    ANTENNADIFFAREA 0.795200 ;
    PORT
      LAYER met2 ;
        RECT 727.810 546.000 728.090 550.000 ;
    END
  END mstream_o[730]
  PIN mstream_o[731]
    DIRECTION OUTPUT TRISTATE ;
    USE SIGNAL ;
    ANTENNADIFFAREA 0.795200 ;
    PORT
      LAYER met2 ;
        RECT 728.730 546.000 729.010 550.000 ;
    END
  END mstream_o[731]
  PIN mstream_o[732]
    DIRECTION OUTPUT TRISTATE ;
    USE SIGNAL ;
    ANTENNADIFFAREA 0.795200 ;
    PORT
      LAYER met2 ;
        RECT 729.650 546.000 729.930 550.000 ;
    END
  END mstream_o[732]
  PIN mstream_o[733]
    DIRECTION OUTPUT TRISTATE ;
    USE SIGNAL ;
    ANTENNADIFFAREA 0.795200 ;
    PORT
      LAYER met2 ;
        RECT 730.570 546.000 730.850 550.000 ;
    END
  END mstream_o[733]
  PIN mstream_o[734]
    DIRECTION OUTPUT TRISTATE ;
    USE SIGNAL ;
    ANTENNADIFFAREA 0.795200 ;
    PORT
      LAYER met2 ;
        RECT 731.490 546.000 731.770 550.000 ;
    END
  END mstream_o[734]
  PIN mstream_o[735]
    DIRECTION OUTPUT TRISTATE ;
    USE SIGNAL ;
    ANTENNADIFFAREA 0.795200 ;
    PORT
      LAYER met2 ;
        RECT 732.410 546.000 732.690 550.000 ;
    END
  END mstream_o[735]
  PIN mstream_o[736]
    DIRECTION OUTPUT TRISTATE ;
    USE SIGNAL ;
    ANTENNADIFFAREA 0.795200 ;
    PORT
      LAYER met2 ;
        RECT 733.330 546.000 733.610 550.000 ;
    END
  END mstream_o[736]
  PIN mstream_o[737]
    DIRECTION OUTPUT TRISTATE ;
    USE SIGNAL ;
    ANTENNADIFFAREA 0.795200 ;
    PORT
      LAYER met2 ;
        RECT 734.250 546.000 734.530 550.000 ;
    END
  END mstream_o[737]
  PIN mstream_o[738]
    DIRECTION OUTPUT TRISTATE ;
    USE SIGNAL ;
    ANTENNADIFFAREA 0.795200 ;
    PORT
      LAYER met2 ;
        RECT 735.170 546.000 735.450 550.000 ;
    END
  END mstream_o[738]
  PIN mstream_o[739]
    DIRECTION OUTPUT TRISTATE ;
    USE SIGNAL ;
    ANTENNADIFFAREA 0.795200 ;
    PORT
      LAYER met2 ;
        RECT 736.090 546.000 736.370 550.000 ;
    END
  END mstream_o[739]
  PIN mstream_o[73]
    DIRECTION OUTPUT TRISTATE ;
    USE SIGNAL ;
    ANTENNADIFFAREA 0.795200 ;
    PORT
      LAYER met2 ;
        RECT 123.370 546.000 123.650 550.000 ;
    END
  END mstream_o[73]
  PIN mstream_o[740]
    DIRECTION OUTPUT TRISTATE ;
    USE SIGNAL ;
    ANTENNADIFFAREA 0.795200 ;
    PORT
      LAYER met2 ;
        RECT 737.010 546.000 737.290 550.000 ;
    END
  END mstream_o[740]
  PIN mstream_o[741]
    DIRECTION OUTPUT TRISTATE ;
    USE SIGNAL ;
    ANTENNADIFFAREA 0.795200 ;
    PORT
      LAYER met2 ;
        RECT 737.930 546.000 738.210 550.000 ;
    END
  END mstream_o[741]
  PIN mstream_o[742]
    DIRECTION OUTPUT TRISTATE ;
    USE SIGNAL ;
    ANTENNADIFFAREA 0.795200 ;
    PORT
      LAYER met2 ;
        RECT 738.850 546.000 739.130 550.000 ;
    END
  END mstream_o[742]
  PIN mstream_o[743]
    DIRECTION OUTPUT TRISTATE ;
    USE SIGNAL ;
    ANTENNADIFFAREA 0.795200 ;
    PORT
      LAYER met2 ;
        RECT 739.770 546.000 740.050 550.000 ;
    END
  END mstream_o[743]
  PIN mstream_o[744]
    DIRECTION OUTPUT TRISTATE ;
    USE SIGNAL ;
    ANTENNADIFFAREA 0.795200 ;
    PORT
      LAYER met2 ;
        RECT 740.690 546.000 740.970 550.000 ;
    END
  END mstream_o[744]
  PIN mstream_o[745]
    DIRECTION OUTPUT TRISTATE ;
    USE SIGNAL ;
    ANTENNADIFFAREA 0.795200 ;
    PORT
      LAYER met2 ;
        RECT 741.610 546.000 741.890 550.000 ;
    END
  END mstream_o[745]
  PIN mstream_o[746]
    DIRECTION OUTPUT TRISTATE ;
    USE SIGNAL ;
    ANTENNADIFFAREA 0.795200 ;
    PORT
      LAYER met2 ;
        RECT 742.530 546.000 742.810 550.000 ;
    END
  END mstream_o[746]
  PIN mstream_o[747]
    DIRECTION OUTPUT TRISTATE ;
    USE SIGNAL ;
    ANTENNADIFFAREA 0.795200 ;
    PORT
      LAYER met2 ;
        RECT 743.450 546.000 743.730 550.000 ;
    END
  END mstream_o[747]
  PIN mstream_o[748]
    DIRECTION OUTPUT TRISTATE ;
    USE SIGNAL ;
    ANTENNADIFFAREA 0.795200 ;
    PORT
      LAYER met3 ;
        RECT 796.000 19.080 800.000 19.680 ;
    END
  END mstream_o[748]
  PIN mstream_o[749]
    DIRECTION OUTPUT TRISTATE ;
    USE SIGNAL ;
    ANTENNADIFFAREA 0.795200 ;
    PORT
      LAYER met3 ;
        RECT 796.000 39.480 800.000 40.080 ;
    END
  END mstream_o[749]
  PIN mstream_o[74]
    DIRECTION OUTPUT TRISTATE ;
    USE SIGNAL ;
    ANTENNADIFFAREA 0.795200 ;
    PORT
      LAYER met2 ;
        RECT 124.290 546.000 124.570 550.000 ;
    END
  END mstream_o[74]
  PIN mstream_o[750]
    DIRECTION OUTPUT TRISTATE ;
    USE SIGNAL ;
    ANTENNADIFFAREA 0.445500 ;
    PORT
      LAYER met3 ;
        RECT 796.000 59.880 800.000 60.480 ;
    END
  END mstream_o[750]
  PIN mstream_o[751]
    DIRECTION OUTPUT TRISTATE ;
    USE SIGNAL ;
    ANTENNADIFFAREA 0.445500 ;
    PORT
      LAYER met3 ;
        RECT 796.000 80.280 800.000 80.880 ;
    END
  END mstream_o[751]
  PIN mstream_o[752]
    DIRECTION OUTPUT TRISTATE ;
    USE SIGNAL ;
    ANTENNADIFFAREA 0.445500 ;
    PORT
      LAYER met3 ;
        RECT 796.000 100.680 800.000 101.280 ;
    END
  END mstream_o[752]
  PIN mstream_o[753]
    DIRECTION OUTPUT TRISTATE ;
    USE SIGNAL ;
    ANTENNADIFFAREA 0.795200 ;
    PORT
      LAYER met3 ;
        RECT 796.000 121.080 800.000 121.680 ;
    END
  END mstream_o[753]
  PIN mstream_o[754]
    DIRECTION OUTPUT TRISTATE ;
    USE SIGNAL ;
    ANTENNADIFFAREA 0.445500 ;
    PORT
      LAYER met3 ;
        RECT 796.000 141.480 800.000 142.080 ;
    END
  END mstream_o[754]
  PIN mstream_o[755]
    DIRECTION OUTPUT TRISTATE ;
    USE SIGNAL ;
    ANTENNADIFFAREA 0.445500 ;
    PORT
      LAYER met3 ;
        RECT 796.000 161.880 800.000 162.480 ;
    END
  END mstream_o[755]
  PIN mstream_o[756]
    DIRECTION OUTPUT TRISTATE ;
    USE SIGNAL ;
    ANTENNADIFFAREA 0.445500 ;
    PORT
      LAYER met3 ;
        RECT 796.000 182.280 800.000 182.880 ;
    END
  END mstream_o[756]
  PIN mstream_o[757]
    DIRECTION OUTPUT TRISTATE ;
    USE SIGNAL ;
    ANTENNADIFFAREA 0.445500 ;
    PORT
      LAYER met3 ;
        RECT 796.000 202.680 800.000 203.280 ;
    END
  END mstream_o[757]
  PIN mstream_o[758]
    DIRECTION OUTPUT TRISTATE ;
    USE SIGNAL ;
    ANTENNADIFFAREA 0.445500 ;
    PORT
      LAYER met3 ;
        RECT 796.000 223.080 800.000 223.680 ;
    END
  END mstream_o[758]
  PIN mstream_o[759]
    DIRECTION OUTPUT TRISTATE ;
    USE SIGNAL ;
    ANTENNADIFFAREA 0.445500 ;
    PORT
      LAYER met3 ;
        RECT 796.000 243.480 800.000 244.080 ;
    END
  END mstream_o[759]
  PIN mstream_o[75]
    DIRECTION OUTPUT TRISTATE ;
    USE SIGNAL ;
    ANTENNADIFFAREA 0.795200 ;
    PORT
      LAYER met2 ;
        RECT 125.210 546.000 125.490 550.000 ;
    END
  END mstream_o[75]
  PIN mstream_o[760]
    DIRECTION OUTPUT TRISTATE ;
    USE SIGNAL ;
    ANTENNADIFFAREA 0.445500 ;
    PORT
      LAYER met3 ;
        RECT 796.000 263.880 800.000 264.480 ;
    END
  END mstream_o[760]
  PIN mstream_o[761]
    DIRECTION OUTPUT TRISTATE ;
    USE SIGNAL ;
    ANTENNADIFFAREA 0.445500 ;
    PORT
      LAYER met3 ;
        RECT 796.000 284.280 800.000 284.880 ;
    END
  END mstream_o[761]
  PIN mstream_o[762]
    DIRECTION OUTPUT TRISTATE ;
    USE SIGNAL ;
    ANTENNADIFFAREA 0.445500 ;
    PORT
      LAYER met3 ;
        RECT 796.000 304.680 800.000 305.280 ;
    END
  END mstream_o[762]
  PIN mstream_o[763]
    DIRECTION OUTPUT TRISTATE ;
    USE SIGNAL ;
    ANTENNADIFFAREA 0.445500 ;
    PORT
      LAYER met3 ;
        RECT 796.000 325.080 800.000 325.680 ;
    END
  END mstream_o[763]
  PIN mstream_o[764]
    DIRECTION OUTPUT TRISTATE ;
    USE SIGNAL ;
    ANTENNADIFFAREA 0.795200 ;
    PORT
      LAYER met3 ;
        RECT 796.000 345.480 800.000 346.080 ;
    END
  END mstream_o[764]
  PIN mstream_o[765]
    DIRECTION OUTPUT TRISTATE ;
    USE SIGNAL ;
    ANTENNADIFFAREA 0.445500 ;
    PORT
      LAYER met3 ;
        RECT 796.000 365.880 800.000 366.480 ;
    END
  END mstream_o[765]
  PIN mstream_o[766]
    DIRECTION OUTPUT TRISTATE ;
    USE SIGNAL ;
    ANTENNADIFFAREA 0.795200 ;
    PORT
      LAYER met3 ;
        RECT 796.000 386.280 800.000 386.880 ;
    END
  END mstream_o[766]
  PIN mstream_o[767]
    DIRECTION OUTPUT TRISTATE ;
    USE SIGNAL ;
    ANTENNADIFFAREA 0.795200 ;
    PORT
      LAYER met3 ;
        RECT 796.000 406.680 800.000 407.280 ;
    END
  END mstream_o[767]
  PIN mstream_o[768]
    DIRECTION OUTPUT TRISTATE ;
    USE SIGNAL ;
    ANTENNADIFFAREA 0.795200 ;
    PORT
      LAYER met3 ;
        RECT 796.000 427.080 800.000 427.680 ;
    END
  END mstream_o[768]
  PIN mstream_o[769]
    DIRECTION OUTPUT TRISTATE ;
    USE SIGNAL ;
    ANTENNADIFFAREA 0.795200 ;
    PORT
      LAYER met3 ;
        RECT 796.000 447.480 800.000 448.080 ;
    END
  END mstream_o[769]
  PIN mstream_o[76]
    DIRECTION OUTPUT TRISTATE ;
    USE SIGNAL ;
    ANTENNADIFFAREA 0.795200 ;
    PORT
      LAYER met2 ;
        RECT 126.130 546.000 126.410 550.000 ;
    END
  END mstream_o[76]
  PIN mstream_o[770]
    DIRECTION OUTPUT TRISTATE ;
    USE SIGNAL ;
    ANTENNADIFFAREA 0.445500 ;
    PORT
      LAYER met3 ;
        RECT 796.000 467.880 800.000 468.480 ;
    END
  END mstream_o[770]
  PIN mstream_o[771]
    DIRECTION OUTPUT TRISTATE ;
    USE SIGNAL ;
    ANTENNADIFFAREA 0.795200 ;
    PORT
      LAYER met3 ;
        RECT 796.000 488.280 800.000 488.880 ;
    END
  END mstream_o[771]
  PIN mstream_o[772]
    DIRECTION OUTPUT TRISTATE ;
    USE SIGNAL ;
    ANTENNADIFFAREA 0.795200 ;
    PORT
      LAYER met3 ;
        RECT 796.000 508.680 800.000 509.280 ;
    END
  END mstream_o[772]
  PIN mstream_o[773]
    DIRECTION OUTPUT TRISTATE ;
    USE SIGNAL ;
    ANTENNADIFFAREA 0.795200 ;
    PORT
      LAYER met3 ;
        RECT 796.000 529.080 800.000 529.680 ;
    END
  END mstream_o[773]
  PIN mstream_o[77]
    DIRECTION OUTPUT TRISTATE ;
    USE SIGNAL ;
    ANTENNADIFFAREA 0.795200 ;
    PORT
      LAYER met2 ;
        RECT 127.050 546.000 127.330 550.000 ;
    END
  END mstream_o[77]
  PIN mstream_o[78]
    DIRECTION OUTPUT TRISTATE ;
    USE SIGNAL ;
    ANTENNADIFFAREA 0.795200 ;
    PORT
      LAYER met2 ;
        RECT 127.970 546.000 128.250 550.000 ;
    END
  END mstream_o[78]
  PIN mstream_o[79]
    DIRECTION OUTPUT TRISTATE ;
    USE SIGNAL ;
    ANTENNADIFFAREA 0.795200 ;
    PORT
      LAYER met2 ;
        RECT 128.890 546.000 129.170 550.000 ;
    END
  END mstream_o[79]
  PIN mstream_o[7]
    DIRECTION OUTPUT TRISTATE ;
    USE SIGNAL ;
    ANTENNADIFFAREA 0.795200 ;
    PORT
      LAYER met2 ;
        RECT 62.650 546.000 62.930 550.000 ;
    END
  END mstream_o[7]
  PIN mstream_o[80]
    DIRECTION OUTPUT TRISTATE ;
    USE SIGNAL ;
    ANTENNADIFFAREA 0.795200 ;
    PORT
      LAYER met2 ;
        RECT 129.810 546.000 130.090 550.000 ;
    END
  END mstream_o[80]
  PIN mstream_o[81]
    DIRECTION OUTPUT TRISTATE ;
    USE SIGNAL ;
    ANTENNADIFFAREA 0.795200 ;
    PORT
      LAYER met2 ;
        RECT 130.730 546.000 131.010 550.000 ;
    END
  END mstream_o[81]
  PIN mstream_o[82]
    DIRECTION OUTPUT TRISTATE ;
    USE SIGNAL ;
    ANTENNADIFFAREA 0.795200 ;
    PORT
      LAYER met2 ;
        RECT 131.650 546.000 131.930 550.000 ;
    END
  END mstream_o[82]
  PIN mstream_o[83]
    DIRECTION OUTPUT TRISTATE ;
    USE SIGNAL ;
    ANTENNADIFFAREA 0.795200 ;
    PORT
      LAYER met2 ;
        RECT 132.570 546.000 132.850 550.000 ;
    END
  END mstream_o[83]
  PIN mstream_o[84]
    DIRECTION OUTPUT TRISTATE ;
    USE SIGNAL ;
    ANTENNADIFFAREA 0.795200 ;
    PORT
      LAYER met2 ;
        RECT 133.490 546.000 133.770 550.000 ;
    END
  END mstream_o[84]
  PIN mstream_o[85]
    DIRECTION OUTPUT TRISTATE ;
    USE SIGNAL ;
    ANTENNADIFFAREA 0.795200 ;
    PORT
      LAYER met2 ;
        RECT 134.410 546.000 134.690 550.000 ;
    END
  END mstream_o[85]
  PIN mstream_o[86]
    DIRECTION OUTPUT TRISTATE ;
    USE SIGNAL ;
    ANTENNADIFFAREA 0.795200 ;
    PORT
      LAYER met2 ;
        RECT 135.330 546.000 135.610 550.000 ;
    END
  END mstream_o[86]
  PIN mstream_o[87]
    DIRECTION OUTPUT TRISTATE ;
    USE SIGNAL ;
    ANTENNADIFFAREA 0.795200 ;
    PORT
      LAYER met2 ;
        RECT 136.250 546.000 136.530 550.000 ;
    END
  END mstream_o[87]
  PIN mstream_o[88]
    DIRECTION OUTPUT TRISTATE ;
    USE SIGNAL ;
    ANTENNADIFFAREA 0.795200 ;
    PORT
      LAYER met2 ;
        RECT 137.170 546.000 137.450 550.000 ;
    END
  END mstream_o[88]
  PIN mstream_o[89]
    DIRECTION OUTPUT TRISTATE ;
    USE SIGNAL ;
    ANTENNADIFFAREA 0.795200 ;
    PORT
      LAYER met2 ;
        RECT 138.090 546.000 138.370 550.000 ;
    END
  END mstream_o[89]
  PIN mstream_o[8]
    DIRECTION OUTPUT TRISTATE ;
    USE SIGNAL ;
    ANTENNADIFFAREA 0.795200 ;
    PORT
      LAYER met2 ;
        RECT 63.570 546.000 63.850 550.000 ;
    END
  END mstream_o[8]
  PIN mstream_o[90]
    DIRECTION OUTPUT TRISTATE ;
    USE SIGNAL ;
    ANTENNADIFFAREA 0.795200 ;
    PORT
      LAYER met2 ;
        RECT 139.010 546.000 139.290 550.000 ;
    END
  END mstream_o[90]
  PIN mstream_o[91]
    DIRECTION OUTPUT TRISTATE ;
    USE SIGNAL ;
    ANTENNADIFFAREA 0.795200 ;
    PORT
      LAYER met2 ;
        RECT 139.930 546.000 140.210 550.000 ;
    END
  END mstream_o[91]
  PIN mstream_o[92]
    DIRECTION OUTPUT TRISTATE ;
    USE SIGNAL ;
    ANTENNADIFFAREA 0.795200 ;
    PORT
      LAYER met2 ;
        RECT 140.850 546.000 141.130 550.000 ;
    END
  END mstream_o[92]
  PIN mstream_o[93]
    DIRECTION OUTPUT TRISTATE ;
    USE SIGNAL ;
    ANTENNADIFFAREA 0.795200 ;
    PORT
      LAYER met2 ;
        RECT 141.770 546.000 142.050 550.000 ;
    END
  END mstream_o[93]
  PIN mstream_o[94]
    DIRECTION OUTPUT TRISTATE ;
    USE SIGNAL ;
    ANTENNADIFFAREA 0.795200 ;
    PORT
      LAYER met2 ;
        RECT 142.690 546.000 142.970 550.000 ;
    END
  END mstream_o[94]
  PIN mstream_o[95]
    DIRECTION OUTPUT TRISTATE ;
    USE SIGNAL ;
    ANTENNADIFFAREA 0.795200 ;
    PORT
      LAYER met2 ;
        RECT 143.610 546.000 143.890 550.000 ;
    END
  END mstream_o[95]
  PIN mstream_o[96]
    DIRECTION OUTPUT TRISTATE ;
    USE SIGNAL ;
    ANTENNADIFFAREA 0.795200 ;
    PORT
      LAYER met2 ;
        RECT 144.530 546.000 144.810 550.000 ;
    END
  END mstream_o[96]
  PIN mstream_o[97]
    DIRECTION OUTPUT TRISTATE ;
    USE SIGNAL ;
    ANTENNADIFFAREA 0.795200 ;
    PORT
      LAYER met2 ;
        RECT 145.450 546.000 145.730 550.000 ;
    END
  END mstream_o[97]
  PIN mstream_o[98]
    DIRECTION OUTPUT TRISTATE ;
    USE SIGNAL ;
    ANTENNADIFFAREA 0.795200 ;
    PORT
      LAYER met2 ;
        RECT 146.370 546.000 146.650 550.000 ;
    END
  END mstream_o[98]
  PIN mstream_o[99]
    DIRECTION OUTPUT TRISTATE ;
    USE SIGNAL ;
    ANTENNADIFFAREA 0.795200 ;
    PORT
      LAYER met2 ;
        RECT 147.290 546.000 147.570 550.000 ;
    END
  END mstream_o[99]
  PIN mstream_o[9]
    DIRECTION OUTPUT TRISTATE ;
    USE SIGNAL ;
    ANTENNADIFFAREA 0.795200 ;
    PORT
      LAYER met2 ;
        RECT 64.490 546.000 64.770 550.000 ;
    END
  END mstream_o[9]
  PIN nrst_i
    DIRECTION INPUT ;
    USE SIGNAL ;
    ANTENNAGATEAREA 0.213000 ;
    PORT
      LAYER met3 ;
        RECT 0.000 91.160 4.000 91.760 ;
    END
  END nrst_i
  PIN selind_o[0]
    DIRECTION OUTPUT TRISTATE ;
    USE SIGNAL ;
    ANTENNADIFFAREA 0.795200 ;
    PORT
      LAYER met3 ;
        RECT 0.000 397.160 4.000 397.760 ;
    END
  END selind_o[0]
  PIN selind_o[1]
    DIRECTION OUTPUT TRISTATE ;
    USE SIGNAL ;
    ANTENNADIFFAREA 0.795200 ;
    PORT
      LAYER met3 ;
        RECT 0.000 458.360 4.000 458.960 ;
    END
  END selind_o[1]
  PIN selind_o[2]
    DIRECTION OUTPUT TRISTATE ;
    USE SIGNAL ;
    ANTENNADIFFAREA 0.795200 ;
    PORT
      LAYER met3 ;
        RECT 0.000 519.560 4.000 520.160 ;
    END
  END selind_o[2]
  PIN sstream_i[0]
    DIRECTION INPUT ;
    USE SIGNAL ;
    ANTENNAGATEAREA 0.213000 ;
    PORT
      LAYER met2 ;
        RECT 47.930 0.000 48.210 4.000 ;
    END
  END sstream_i[0]
  PIN sstream_i[100]
    DIRECTION INPUT ;
    USE SIGNAL ;
    ANTENNAGATEAREA 0.159000 ;
    PORT
      LAYER met2 ;
        RECT 323.930 0.000 324.210 4.000 ;
    END
  END sstream_i[100]
  PIN sstream_i[101]
    DIRECTION INPUT ;
    USE SIGNAL ;
    ANTENNAGATEAREA 0.213000 ;
    PORT
      LAYER met2 ;
        RECT 326.690 0.000 326.970 4.000 ;
    END
  END sstream_i[101]
  PIN sstream_i[102]
    DIRECTION INPUT ;
    USE SIGNAL ;
    ANTENNAGATEAREA 0.213000 ;
    PORT
      LAYER met2 ;
        RECT 329.450 0.000 329.730 4.000 ;
    END
  END sstream_i[102]
  PIN sstream_i[103]
    DIRECTION INPUT ;
    USE SIGNAL ;
    ANTENNAGATEAREA 0.247500 ;
    PORT
      LAYER met2 ;
        RECT 332.210 0.000 332.490 4.000 ;
    END
  END sstream_i[103]
  PIN sstream_i[104]
    DIRECTION INPUT ;
    USE SIGNAL ;
    ANTENNAGATEAREA 0.247500 ;
    PORT
      LAYER met2 ;
        RECT 334.970 0.000 335.250 4.000 ;
    END
  END sstream_i[104]
  PIN sstream_i[105]
    DIRECTION INPUT ;
    USE SIGNAL ;
    ANTENNAGATEAREA 0.247500 ;
    PORT
      LAYER met2 ;
        RECT 337.730 0.000 338.010 4.000 ;
    END
  END sstream_i[105]
  PIN sstream_i[106]
    DIRECTION INPUT ;
    USE SIGNAL ;
    ANTENNAGATEAREA 0.213000 ;
    PORT
      LAYER met2 ;
        RECT 340.490 0.000 340.770 4.000 ;
    END
  END sstream_i[106]
  PIN sstream_i[107]
    DIRECTION INPUT ;
    USE SIGNAL ;
    ANTENNAGATEAREA 0.213000 ;
    PORT
      LAYER met2 ;
        RECT 343.250 0.000 343.530 4.000 ;
    END
  END sstream_i[107]
  PIN sstream_i[108]
    DIRECTION INPUT ;
    USE SIGNAL ;
    ANTENNAGATEAREA 0.159000 ;
    PORT
      LAYER met2 ;
        RECT 346.010 0.000 346.290 4.000 ;
    END
  END sstream_i[108]
  PIN sstream_i[109]
    DIRECTION INPUT ;
    USE SIGNAL ;
    ANTENNAGATEAREA 0.213000 ;
    PORT
      LAYER met2 ;
        RECT 348.770 0.000 349.050 4.000 ;
    END
  END sstream_i[109]
  PIN sstream_i[10]
    DIRECTION INPUT ;
    USE SIGNAL ;
    ANTENNAGATEAREA 0.426000 ;
    PORT
      LAYER met2 ;
        RECT 75.530 0.000 75.810 4.000 ;
    END
  END sstream_i[10]
  PIN sstream_i[110]
    DIRECTION INPUT ;
    USE SIGNAL ;
    ANTENNAGATEAREA 0.213000 ;
    PORT
      LAYER met2 ;
        RECT 351.530 0.000 351.810 4.000 ;
    END
  END sstream_i[110]
  PIN sstream_i[111]
    DIRECTION INPUT ;
    USE SIGNAL ;
    ANTENNAGATEAREA 0.247500 ;
    PORT
      LAYER met2 ;
        RECT 354.290 0.000 354.570 4.000 ;
    END
  END sstream_i[111]
  PIN sstream_i[112]
    DIRECTION INPUT ;
    USE SIGNAL ;
    ANTENNAGATEAREA 0.247500 ;
    PORT
      LAYER met2 ;
        RECT 357.050 0.000 357.330 4.000 ;
    END
  END sstream_i[112]
  PIN sstream_i[113]
    DIRECTION INPUT ;
    USE SIGNAL ;
    ANTENNAGATEAREA 0.247500 ;
    PORT
      LAYER met2 ;
        RECT 359.810 0.000 360.090 4.000 ;
    END
  END sstream_i[113]
  PIN sstream_i[114]
    DIRECTION INPUT ;
    USE SIGNAL ;
    ANTENNAGATEAREA 0.213000 ;
    PORT
      LAYER met2 ;
        RECT 362.570 0.000 362.850 4.000 ;
    END
  END sstream_i[114]
  PIN sstream_i[115]
    DIRECTION INPUT ;
    USE SIGNAL ;
    ANTENNAGATEAREA 0.213000 ;
    PORT
      LAYER met2 ;
        RECT 365.330 0.000 365.610 4.000 ;
    END
  END sstream_i[115]
  PIN sstream_i[116]
    DIRECTION INPUT ;
    USE SIGNAL ;
    ANTENNAGATEAREA 0.159000 ;
    PORT
      LAYER met2 ;
        RECT 368.090 0.000 368.370 4.000 ;
    END
  END sstream_i[116]
  PIN sstream_i[117]
    DIRECTION INPUT ;
    USE SIGNAL ;
    ANTENNAGATEAREA 0.213000 ;
    PORT
      LAYER met2 ;
        RECT 370.850 0.000 371.130 4.000 ;
    END
  END sstream_i[117]
  PIN sstream_i[118]
    DIRECTION INPUT ;
    USE SIGNAL ;
    ANTENNAGATEAREA 0.247500 ;
    PORT
      LAYER met2 ;
        RECT 373.610 0.000 373.890 4.000 ;
    END
  END sstream_i[118]
  PIN sstream_i[119]
    DIRECTION INPUT ;
    USE SIGNAL ;
    ANTENNAGATEAREA 0.247500 ;
    PORT
      LAYER met2 ;
        RECT 376.370 0.000 376.650 4.000 ;
    END
  END sstream_i[119]
  PIN sstream_i[11]
    DIRECTION INPUT ;
    USE SIGNAL ;
    ANTENNAGATEAREA 0.247500 ;
    PORT
      LAYER met2 ;
        RECT 78.290 0.000 78.570 4.000 ;
    END
  END sstream_i[11]
  PIN sstream_i[120]
    DIRECTION INPUT ;
    USE SIGNAL ;
    ANTENNAGATEAREA 0.247500 ;
    PORT
      LAYER met2 ;
        RECT 379.130 0.000 379.410 4.000 ;
    END
  END sstream_i[120]
  PIN sstream_i[121]
    DIRECTION INPUT ;
    USE SIGNAL ;
    ANTENNAGATEAREA 0.247500 ;
    PORT
      LAYER met2 ;
        RECT 381.890 0.000 382.170 4.000 ;
    END
  END sstream_i[121]
  PIN sstream_i[122]
    DIRECTION INPUT ;
    USE SIGNAL ;
    ANTENNAGATEAREA 0.247500 ;
    PORT
      LAYER met2 ;
        RECT 384.650 0.000 384.930 4.000 ;
    END
  END sstream_i[122]
  PIN sstream_i[123]
    DIRECTION INPUT ;
    USE SIGNAL ;
    ANTENNAGATEAREA 0.159000 ;
    PORT
      LAYER met2 ;
        RECT 387.410 0.000 387.690 4.000 ;
    END
  END sstream_i[123]
  PIN sstream_i[124]
    DIRECTION INPUT ;
    USE SIGNAL ;
    ANTENNAGATEAREA 0.213000 ;
    PORT
      LAYER met2 ;
        RECT 390.170 0.000 390.450 4.000 ;
    END
  END sstream_i[124]
  PIN sstream_i[125]
    DIRECTION INPUT ;
    USE SIGNAL ;
    ANTENNAGATEAREA 0.247500 ;
    PORT
      LAYER met2 ;
        RECT 392.930 0.000 393.210 4.000 ;
    END
  END sstream_i[125]
  PIN sstream_i[126]
    DIRECTION INPUT ;
    USE SIGNAL ;
    ANTENNAGATEAREA 0.213000 ;
    PORT
      LAYER met2 ;
        RECT 395.690 0.000 395.970 4.000 ;
    END
  END sstream_i[126]
  PIN sstream_i[127]
    DIRECTION INPUT ;
    USE SIGNAL ;
    ANTENNAGATEAREA 0.247500 ;
    PORT
      LAYER met2 ;
        RECT 398.450 0.000 398.730 4.000 ;
    END
  END sstream_i[127]
  PIN sstream_i[128]
    DIRECTION INPUT ;
    USE SIGNAL ;
    ANTENNAGATEAREA 0.247500 ;
    PORT
      LAYER met2 ;
        RECT 401.210 0.000 401.490 4.000 ;
    END
  END sstream_i[128]
  PIN sstream_i[129]
    DIRECTION INPUT ;
    USE SIGNAL ;
    ANTENNAGATEAREA 0.247500 ;
    PORT
      LAYER met2 ;
        RECT 403.970 0.000 404.250 4.000 ;
    END
  END sstream_i[129]
  PIN sstream_i[12]
    DIRECTION INPUT ;
    USE SIGNAL ;
    ANTENNAGATEAREA 0.247500 ;
    PORT
      LAYER met2 ;
        RECT 81.050 0.000 81.330 4.000 ;
    END
  END sstream_i[12]
  PIN sstream_i[130]
    DIRECTION INPUT ;
    USE SIGNAL ;
    ANTENNAGATEAREA 0.247500 ;
    PORT
      LAYER met2 ;
        RECT 406.730 0.000 407.010 4.000 ;
    END
  END sstream_i[130]
  PIN sstream_i[131]
    DIRECTION INPUT ;
    USE SIGNAL ;
    ANTENNAGATEAREA 0.247500 ;
    PORT
      LAYER met2 ;
        RECT 409.490 0.000 409.770 4.000 ;
    END
  END sstream_i[131]
  PIN sstream_i[132]
    DIRECTION INPUT ;
    USE SIGNAL ;
    ANTENNAGATEAREA 0.247500 ;
    PORT
      LAYER met2 ;
        RECT 412.250 0.000 412.530 4.000 ;
    END
  END sstream_i[132]
  PIN sstream_i[133]
    DIRECTION INPUT ;
    USE SIGNAL ;
    ANTENNAGATEAREA 0.213000 ;
    PORT
      LAYER met2 ;
        RECT 415.010 0.000 415.290 4.000 ;
    END
  END sstream_i[133]
  PIN sstream_i[134]
    DIRECTION INPUT ;
    USE SIGNAL ;
    ANTENNAGATEAREA 0.247500 ;
    PORT
      LAYER met2 ;
        RECT 417.770 0.000 418.050 4.000 ;
    END
  END sstream_i[134]
  PIN sstream_i[135]
    DIRECTION INPUT ;
    USE SIGNAL ;
    ANTENNAGATEAREA 0.247500 ;
    PORT
      LAYER met2 ;
        RECT 420.530 0.000 420.810 4.000 ;
    END
  END sstream_i[135]
  PIN sstream_i[136]
    DIRECTION INPUT ;
    USE SIGNAL ;
    ANTENNAGATEAREA 0.247500 ;
    PORT
      LAYER met2 ;
        RECT 423.290 0.000 423.570 4.000 ;
    END
  END sstream_i[136]
  PIN sstream_i[137]
    DIRECTION INPUT ;
    USE SIGNAL ;
    ANTENNAGATEAREA 0.247500 ;
    PORT
      LAYER met2 ;
        RECT 426.050 0.000 426.330 4.000 ;
    END
  END sstream_i[137]
  PIN sstream_i[138]
    DIRECTION INPUT ;
    USE SIGNAL ;
    ANTENNAGATEAREA 0.247500 ;
    PORT
      LAYER met2 ;
        RECT 428.810 0.000 429.090 4.000 ;
    END
  END sstream_i[138]
  PIN sstream_i[139]
    DIRECTION INPUT ;
    USE SIGNAL ;
    ANTENNAGATEAREA 0.247500 ;
    PORT
      LAYER met2 ;
        RECT 431.570 0.000 431.850 4.000 ;
    END
  END sstream_i[139]
  PIN sstream_i[13]
    DIRECTION INPUT ;
    USE SIGNAL ;
    ANTENNAGATEAREA 0.247500 ;
    PORT
      LAYER met2 ;
        RECT 83.810 0.000 84.090 4.000 ;
    END
  END sstream_i[13]
  PIN sstream_i[140]
    DIRECTION INPUT ;
    USE SIGNAL ;
    ANTENNAGATEAREA 0.247500 ;
    PORT
      LAYER met2 ;
        RECT 434.330 0.000 434.610 4.000 ;
    END
  END sstream_i[140]
  PIN sstream_i[141]
    DIRECTION INPUT ;
    USE SIGNAL ;
    ANTENNAGATEAREA 0.213000 ;
    PORT
      LAYER met2 ;
        RECT 437.090 0.000 437.370 4.000 ;
    END
  END sstream_i[141]
  PIN sstream_i[142]
    DIRECTION INPUT ;
    USE SIGNAL ;
    ANTENNAGATEAREA 0.159000 ;
    PORT
      LAYER met2 ;
        RECT 439.850 0.000 440.130 4.000 ;
    END
  END sstream_i[142]
  PIN sstream_i[143]
    DIRECTION INPUT ;
    USE SIGNAL ;
    ANTENNAGATEAREA 0.247500 ;
    PORT
      LAYER met2 ;
        RECT 442.610 0.000 442.890 4.000 ;
    END
  END sstream_i[143]
  PIN sstream_i[144]
    DIRECTION INPUT ;
    USE SIGNAL ;
    ANTENNAGATEAREA 0.247500 ;
    PORT
      LAYER met2 ;
        RECT 445.370 0.000 445.650 4.000 ;
    END
  END sstream_i[144]
  PIN sstream_i[145]
    DIRECTION INPUT ;
    USE SIGNAL ;
    ANTENNAGATEAREA 0.247500 ;
    PORT
      LAYER met2 ;
        RECT 448.130 0.000 448.410 4.000 ;
    END
  END sstream_i[145]
  PIN sstream_i[146]
    DIRECTION INPUT ;
    USE SIGNAL ;
    ANTENNAGATEAREA 0.247500 ;
    PORT
      LAYER met2 ;
        RECT 450.890 0.000 451.170 4.000 ;
    END
  END sstream_i[146]
  PIN sstream_i[147]
    DIRECTION INPUT ;
    USE SIGNAL ;
    ANTENNAGATEAREA 0.213000 ;
    PORT
      LAYER met2 ;
        RECT 453.650 0.000 453.930 4.000 ;
    END
  END sstream_i[147]
  PIN sstream_i[148]
    DIRECTION INPUT ;
    USE SIGNAL ;
    ANTENNAGATEAREA 0.159000 ;
    PORT
      LAYER met2 ;
        RECT 456.410 0.000 456.690 4.000 ;
    END
  END sstream_i[148]
  PIN sstream_i[149]
    DIRECTION INPUT ;
    USE SIGNAL ;
    ANTENNAGATEAREA 0.213000 ;
    PORT
      LAYER met2 ;
        RECT 459.170 0.000 459.450 4.000 ;
    END
  END sstream_i[149]
  PIN sstream_i[14]
    DIRECTION INPUT ;
    USE SIGNAL ;
    ANTENNAGATEAREA 0.247500 ;
    PORT
      LAYER met2 ;
        RECT 86.570 0.000 86.850 4.000 ;
    END
  END sstream_i[14]
  PIN sstream_i[150]
    DIRECTION INPUT ;
    USE SIGNAL ;
    ANTENNAGATEAREA 0.247500 ;
    PORT
      LAYER met2 ;
        RECT 461.930 0.000 462.210 4.000 ;
    END
  END sstream_i[150]
  PIN sstream_i[151]
    DIRECTION INPUT ;
    USE SIGNAL ;
    ANTENNAGATEAREA 0.247500 ;
    PORT
      LAYER met2 ;
        RECT 464.690 0.000 464.970 4.000 ;
    END
  END sstream_i[151]
  PIN sstream_i[152]
    DIRECTION INPUT ;
    USE SIGNAL ;
    ANTENNAGATEAREA 0.247500 ;
    PORT
      LAYER met2 ;
        RECT 467.450 0.000 467.730 4.000 ;
    END
  END sstream_i[152]
  PIN sstream_i[153]
    DIRECTION INPUT ;
    USE SIGNAL ;
    ANTENNAGATEAREA 0.247500 ;
    PORT
      LAYER met2 ;
        RECT 470.210 0.000 470.490 4.000 ;
    END
  END sstream_i[153]
  PIN sstream_i[154]
    DIRECTION INPUT ;
    USE SIGNAL ;
    ANTENNAGATEAREA 0.247500 ;
    PORT
      LAYER met2 ;
        RECT 472.970 0.000 473.250 4.000 ;
    END
  END sstream_i[154]
  PIN sstream_i[155]
    DIRECTION INPUT ;
    USE SIGNAL ;
    ANTENNAGATEAREA 0.159000 ;
    PORT
      LAYER met2 ;
        RECT 475.730 0.000 476.010 4.000 ;
    END
  END sstream_i[155]
  PIN sstream_i[156]
    DIRECTION INPUT ;
    USE SIGNAL ;
    ANTENNAGATEAREA 0.159000 ;
    PORT
      LAYER met2 ;
        RECT 478.490 0.000 478.770 4.000 ;
    END
  END sstream_i[156]
  PIN sstream_i[157]
    DIRECTION INPUT ;
    USE SIGNAL ;
    ANTENNAGATEAREA 0.213000 ;
    PORT
      LAYER met2 ;
        RECT 481.250 0.000 481.530 4.000 ;
    END
  END sstream_i[157]
  PIN sstream_i[158]
    DIRECTION INPUT ;
    USE SIGNAL ;
    ANTENNAGATEAREA 0.247500 ;
    PORT
      LAYER met2 ;
        RECT 484.010 0.000 484.290 4.000 ;
    END
  END sstream_i[158]
  PIN sstream_i[159]
    DIRECTION INPUT ;
    USE SIGNAL ;
    ANTENNAGATEAREA 0.247500 ;
    PORT
      LAYER met2 ;
        RECT 486.770 0.000 487.050 4.000 ;
    END
  END sstream_i[159]
  PIN sstream_i[15]
    DIRECTION INPUT ;
    USE SIGNAL ;
    ANTENNAGATEAREA 0.426000 ;
    PORT
      LAYER met2 ;
        RECT 89.330 0.000 89.610 4.000 ;
    END
  END sstream_i[15]
  PIN sstream_i[160]
    DIRECTION INPUT ;
    USE SIGNAL ;
    ANTENNAGATEAREA 0.247500 ;
    PORT
      LAYER met2 ;
        RECT 489.530 0.000 489.810 4.000 ;
    END
  END sstream_i[160]
  PIN sstream_i[161]
    DIRECTION INPUT ;
    USE SIGNAL ;
    ANTENNAGATEAREA 0.247500 ;
    PORT
      LAYER met2 ;
        RECT 492.290 0.000 492.570 4.000 ;
    END
  END sstream_i[161]
  PIN sstream_i[162]
    DIRECTION INPUT ;
    USE SIGNAL ;
    ANTENNAGATEAREA 0.247500 ;
    PORT
      LAYER met2 ;
        RECT 495.050 0.000 495.330 4.000 ;
    END
  END sstream_i[162]
  PIN sstream_i[163]
    DIRECTION INPUT ;
    USE SIGNAL ;
    ANTENNAGATEAREA 0.213000 ;
    PORT
      LAYER met2 ;
        RECT 497.810 0.000 498.090 4.000 ;
    END
  END sstream_i[163]
  PIN sstream_i[164]
    DIRECTION INPUT ;
    USE SIGNAL ;
    ANTENNAGATEAREA 0.159000 ;
    PORT
      LAYER met2 ;
        RECT 500.570 0.000 500.850 4.000 ;
    END
  END sstream_i[164]
  PIN sstream_i[165]
    DIRECTION INPUT ;
    USE SIGNAL ;
    ANTENNAGATEAREA 0.213000 ;
    PORT
      LAYER met2 ;
        RECT 503.330 0.000 503.610 4.000 ;
    END
  END sstream_i[165]
  PIN sstream_i[166]
    DIRECTION INPUT ;
    USE SIGNAL ;
    ANTENNAGATEAREA 0.247500 ;
    PORT
      LAYER met2 ;
        RECT 506.090 0.000 506.370 4.000 ;
    END
  END sstream_i[166]
  PIN sstream_i[167]
    DIRECTION INPUT ;
    USE SIGNAL ;
    ANTENNAGATEAREA 0.247500 ;
    PORT
      LAYER met2 ;
        RECT 508.850 0.000 509.130 4.000 ;
    END
  END sstream_i[167]
  PIN sstream_i[168]
    DIRECTION INPUT ;
    USE SIGNAL ;
    ANTENNAGATEAREA 0.247500 ;
    PORT
      LAYER met2 ;
        RECT 511.610 0.000 511.890 4.000 ;
    END
  END sstream_i[168]
  PIN sstream_i[169]
    DIRECTION INPUT ;
    USE SIGNAL ;
    ANTENNAGATEAREA 0.247500 ;
    PORT
      LAYER met2 ;
        RECT 514.370 0.000 514.650 4.000 ;
    END
  END sstream_i[169]
  PIN sstream_i[16]
    DIRECTION INPUT ;
    USE SIGNAL ;
    ANTENNAGATEAREA 0.247500 ;
    PORT
      LAYER met2 ;
        RECT 92.090 0.000 92.370 4.000 ;
    END
  END sstream_i[16]
  PIN sstream_i[170]
    DIRECTION INPUT ;
    USE SIGNAL ;
    ANTENNAGATEAREA 0.247500 ;
    PORT
      LAYER met2 ;
        RECT 517.130 0.000 517.410 4.000 ;
    END
  END sstream_i[170]
  PIN sstream_i[171]
    DIRECTION INPUT ;
    USE SIGNAL ;
    ANTENNAGATEAREA 0.247500 ;
    PORT
      LAYER met2 ;
        RECT 519.890 0.000 520.170 4.000 ;
    END
  END sstream_i[171]
  PIN sstream_i[172]
    DIRECTION INPUT ;
    USE SIGNAL ;
    ANTENNAGATEAREA 0.213000 ;
    PORT
      LAYER met2 ;
        RECT 522.650 0.000 522.930 4.000 ;
    END
  END sstream_i[172]
  PIN sstream_i[173]
    DIRECTION INPUT ;
    USE SIGNAL ;
    ANTENNAGATEAREA 0.213000 ;
    PORT
      LAYER met2 ;
        RECT 525.410 0.000 525.690 4.000 ;
    END
  END sstream_i[173]
  PIN sstream_i[174]
    DIRECTION INPUT ;
    USE SIGNAL ;
    ANTENNAGATEAREA 0.213000 ;
    PORT
      LAYER met2 ;
        RECT 528.170 0.000 528.450 4.000 ;
    END
  END sstream_i[174]
  PIN sstream_i[175]
    DIRECTION INPUT ;
    USE SIGNAL ;
    ANTENNAGATEAREA 0.213000 ;
    PORT
      LAYER met2 ;
        RECT 530.930 0.000 531.210 4.000 ;
    END
  END sstream_i[175]
  PIN sstream_i[176]
    DIRECTION INPUT ;
    USE SIGNAL ;
    ANTENNAGATEAREA 0.247500 ;
    PORT
      LAYER met2 ;
        RECT 533.690 0.000 533.970 4.000 ;
    END
  END sstream_i[176]
  PIN sstream_i[177]
    DIRECTION INPUT ;
    USE SIGNAL ;
    ANTENNAGATEAREA 0.247500 ;
    PORT
      LAYER met2 ;
        RECT 536.450 0.000 536.730 4.000 ;
    END
  END sstream_i[177]
  PIN sstream_i[178]
    DIRECTION INPUT ;
    USE SIGNAL ;
    ANTENNAGATEAREA 0.247500 ;
    PORT
      LAYER met2 ;
        RECT 539.210 0.000 539.490 4.000 ;
    END
  END sstream_i[178]
  PIN sstream_i[179]
    DIRECTION INPUT ;
    USE SIGNAL ;
    ANTENNAGATEAREA 0.213000 ;
    PORT
      LAYER met2 ;
        RECT 541.970 0.000 542.250 4.000 ;
    END
  END sstream_i[179]
  PIN sstream_i[17]
    DIRECTION INPUT ;
    USE SIGNAL ;
    ANTENNAGATEAREA 0.426000 ;
    PORT
      LAYER met2 ;
        RECT 94.850 0.000 95.130 4.000 ;
    END
  END sstream_i[17]
  PIN sstream_i[180]
    DIRECTION INPUT ;
    USE SIGNAL ;
    ANTENNAGATEAREA 0.247500 ;
    PORT
      LAYER met2 ;
        RECT 544.730 0.000 545.010 4.000 ;
    END
  END sstream_i[180]
  PIN sstream_i[181]
    DIRECTION INPUT ;
    USE SIGNAL ;
    ANTENNAGATEAREA 0.213000 ;
    PORT
      LAYER met2 ;
        RECT 547.490 0.000 547.770 4.000 ;
    END
  END sstream_i[181]
  PIN sstream_i[182]
    DIRECTION INPUT ;
    USE SIGNAL ;
    ANTENNAGATEAREA 0.213000 ;
    PORT
      LAYER met2 ;
        RECT 550.250 0.000 550.530 4.000 ;
    END
  END sstream_i[182]
  PIN sstream_i[183]
    DIRECTION INPUT ;
    USE SIGNAL ;
    ANTENNAGATEAREA 0.213000 ;
    PORT
      LAYER met2 ;
        RECT 553.010 0.000 553.290 4.000 ;
    END
  END sstream_i[183]
  PIN sstream_i[184]
    DIRECTION INPUT ;
    USE SIGNAL ;
    ANTENNAGATEAREA 0.247500 ;
    PORT
      LAYER met2 ;
        RECT 555.770 0.000 556.050 4.000 ;
    END
  END sstream_i[184]
  PIN sstream_i[185]
    DIRECTION INPUT ;
    USE SIGNAL ;
    ANTENNAGATEAREA 0.247500 ;
    PORT
      LAYER met2 ;
        RECT 558.530 0.000 558.810 4.000 ;
    END
  END sstream_i[185]
  PIN sstream_i[186]
    DIRECTION INPUT ;
    USE SIGNAL ;
    ANTENNAGATEAREA 0.247500 ;
    PORT
      LAYER met2 ;
        RECT 561.290 0.000 561.570 4.000 ;
    END
  END sstream_i[186]
  PIN sstream_i[187]
    DIRECTION INPUT ;
    USE SIGNAL ;
    ANTENNAGATEAREA 0.213000 ;
    PORT
      LAYER met2 ;
        RECT 564.050 0.000 564.330 4.000 ;
    END
  END sstream_i[187]
  PIN sstream_i[188]
    DIRECTION INPUT ;
    USE SIGNAL ;
    ANTENNAGATEAREA 0.247500 ;
    PORT
      LAYER met2 ;
        RECT 566.810 0.000 567.090 4.000 ;
    END
  END sstream_i[188]
  PIN sstream_i[189]
    DIRECTION INPUT ;
    USE SIGNAL ;
    ANTENNAGATEAREA 0.247500 ;
    PORT
      LAYER met2 ;
        RECT 569.570 0.000 569.850 4.000 ;
    END
  END sstream_i[189]
  PIN sstream_i[18]
    DIRECTION INPUT ;
    USE SIGNAL ;
    ANTENNAGATEAREA 0.247500 ;
    PORT
      LAYER met2 ;
        RECT 97.610 0.000 97.890 4.000 ;
    END
  END sstream_i[18]
  PIN sstream_i[190]
    DIRECTION INPUT ;
    USE SIGNAL ;
    ANTENNAGATEAREA 0.247500 ;
    PORT
      LAYER met2 ;
        RECT 572.330 0.000 572.610 4.000 ;
    END
  END sstream_i[190]
  PIN sstream_i[191]
    DIRECTION INPUT ;
    USE SIGNAL ;
    ANTENNAGATEAREA 0.247500 ;
    PORT
      LAYER met2 ;
        RECT 575.090 0.000 575.370 4.000 ;
    END
  END sstream_i[191]
  PIN sstream_i[192]
    DIRECTION INPUT ;
    USE SIGNAL ;
    ANTENNAGATEAREA 0.247500 ;
    PORT
      LAYER met2 ;
        RECT 577.850 0.000 578.130 4.000 ;
    END
  END sstream_i[192]
  PIN sstream_i[193]
    DIRECTION INPUT ;
    USE SIGNAL ;
    ANTENNAGATEAREA 0.247500 ;
    PORT
      LAYER met2 ;
        RECT 580.610 0.000 580.890 4.000 ;
    END
  END sstream_i[193]
  PIN sstream_i[194]
    DIRECTION INPUT ;
    USE SIGNAL ;
    ANTENNAGATEAREA 0.247500 ;
    PORT
      LAYER met2 ;
        RECT 583.370 0.000 583.650 4.000 ;
    END
  END sstream_i[194]
  PIN sstream_i[195]
    DIRECTION INPUT ;
    USE SIGNAL ;
    ANTENNAGATEAREA 0.247500 ;
    PORT
      LAYER met2 ;
        RECT 586.130 0.000 586.410 4.000 ;
    END
  END sstream_i[195]
  PIN sstream_i[196]
    DIRECTION INPUT ;
    USE SIGNAL ;
    ANTENNAGATEAREA 0.247500 ;
    PORT
      LAYER met2 ;
        RECT 588.890 0.000 589.170 4.000 ;
    END
  END sstream_i[196]
  PIN sstream_i[197]
    DIRECTION INPUT ;
    USE SIGNAL ;
    ANTENNAGATEAREA 0.247500 ;
    PORT
      LAYER met2 ;
        RECT 591.650 0.000 591.930 4.000 ;
    END
  END sstream_i[197]
  PIN sstream_i[198]
    DIRECTION INPUT ;
    USE SIGNAL ;
    ANTENNAGATEAREA 0.247500 ;
    PORT
      LAYER met2 ;
        RECT 594.410 0.000 594.690 4.000 ;
    END
  END sstream_i[198]
  PIN sstream_i[199]
    DIRECTION INPUT ;
    USE SIGNAL ;
    ANTENNAGATEAREA 0.247500 ;
    PORT
      LAYER met2 ;
        RECT 597.170 0.000 597.450 4.000 ;
    END
  END sstream_i[199]
  PIN sstream_i[19]
    DIRECTION INPUT ;
    USE SIGNAL ;
    ANTENNAGATEAREA 0.213000 ;
    PORT
      LAYER met2 ;
        RECT 100.370 0.000 100.650 4.000 ;
    END
  END sstream_i[19]
  PIN sstream_i[1]
    DIRECTION INPUT ;
    USE SIGNAL ;
    ANTENNAGATEAREA 0.247500 ;
    PORT
      LAYER met2 ;
        RECT 50.690 0.000 50.970 4.000 ;
    END
  END sstream_i[1]
  PIN sstream_i[200]
    DIRECTION INPUT ;
    USE SIGNAL ;
    ANTENNAGATEAREA 0.247500 ;
    PORT
      LAYER met2 ;
        RECT 599.930 0.000 600.210 4.000 ;
    END
  END sstream_i[200]
  PIN sstream_i[201]
    DIRECTION INPUT ;
    USE SIGNAL ;
    ANTENNAGATEAREA 0.247500 ;
    PORT
      LAYER met2 ;
        RECT 602.690 0.000 602.970 4.000 ;
    END
  END sstream_i[201]
  PIN sstream_i[202]
    DIRECTION INPUT ;
    USE SIGNAL ;
    ANTENNAGATEAREA 0.247500 ;
    PORT
      LAYER met2 ;
        RECT 605.450 0.000 605.730 4.000 ;
    END
  END sstream_i[202]
  PIN sstream_i[203]
    DIRECTION INPUT ;
    USE SIGNAL ;
    ANTENNAGATEAREA 0.247500 ;
    PORT
      LAYER met2 ;
        RECT 608.210 0.000 608.490 4.000 ;
    END
  END sstream_i[203]
  PIN sstream_i[204]
    DIRECTION INPUT ;
    USE SIGNAL ;
    ANTENNAGATEAREA 0.247500 ;
    PORT
      LAYER met2 ;
        RECT 610.970 0.000 611.250 4.000 ;
    END
  END sstream_i[204]
  PIN sstream_i[205]
    DIRECTION INPUT ;
    USE SIGNAL ;
    ANTENNAGATEAREA 0.247500 ;
    PORT
      LAYER met2 ;
        RECT 613.730 0.000 614.010 4.000 ;
    END
  END sstream_i[205]
  PIN sstream_i[206]
    DIRECTION INPUT ;
    USE SIGNAL ;
    ANTENNAGATEAREA 0.213000 ;
    PORT
      LAYER met2 ;
        RECT 616.490 0.000 616.770 4.000 ;
    END
  END sstream_i[206]
  PIN sstream_i[207]
    DIRECTION INPUT ;
    USE SIGNAL ;
    ANTENNAGATEAREA 0.247500 ;
    PORT
      LAYER met2 ;
        RECT 619.250 0.000 619.530 4.000 ;
    END
  END sstream_i[207]
  PIN sstream_i[208]
    DIRECTION INPUT ;
    USE SIGNAL ;
    ANTENNAGATEAREA 0.247500 ;
    PORT
      LAYER met2 ;
        RECT 622.010 0.000 622.290 4.000 ;
    END
  END sstream_i[208]
  PIN sstream_i[209]
    DIRECTION INPUT ;
    USE SIGNAL ;
    ANTENNAGATEAREA 0.247500 ;
    PORT
      LAYER met2 ;
        RECT 624.770 0.000 625.050 4.000 ;
    END
  END sstream_i[209]
  PIN sstream_i[20]
    DIRECTION INPUT ;
    USE SIGNAL ;
    ANTENNAGATEAREA 0.213000 ;
    PORT
      LAYER met2 ;
        RECT 103.130 0.000 103.410 4.000 ;
    END
  END sstream_i[20]
  PIN sstream_i[210]
    DIRECTION INPUT ;
    USE SIGNAL ;
    ANTENNAGATEAREA 0.247500 ;
    PORT
      LAYER met2 ;
        RECT 627.530 0.000 627.810 4.000 ;
    END
  END sstream_i[210]
  PIN sstream_i[211]
    DIRECTION INPUT ;
    USE SIGNAL ;
    ANTENNAGATEAREA 0.247500 ;
    PORT
      LAYER met2 ;
        RECT 630.290 0.000 630.570 4.000 ;
    END
  END sstream_i[211]
  PIN sstream_i[212]
    DIRECTION INPUT ;
    USE SIGNAL ;
    ANTENNAGATEAREA 0.426000 ;
    PORT
      LAYER met2 ;
        RECT 633.050 0.000 633.330 4.000 ;
    END
  END sstream_i[212]
  PIN sstream_i[213]
    DIRECTION INPUT ;
    USE SIGNAL ;
    ANTENNAGATEAREA 0.247500 ;
    PORT
      LAYER met2 ;
        RECT 635.810 0.000 636.090 4.000 ;
    END
  END sstream_i[213]
  PIN sstream_i[214]
    DIRECTION INPUT ;
    USE SIGNAL ;
    ANTENNAGATEAREA 0.247500 ;
    PORT
      LAYER met2 ;
        RECT 638.570 0.000 638.850 4.000 ;
    END
  END sstream_i[214]
  PIN sstream_i[215]
    DIRECTION INPUT ;
    USE SIGNAL ;
    ANTENNAGATEAREA 0.247500 ;
    PORT
      LAYER met2 ;
        RECT 641.330 0.000 641.610 4.000 ;
    END
  END sstream_i[215]
  PIN sstream_i[216]
    DIRECTION INPUT ;
    USE SIGNAL ;
    ANTENNAGATEAREA 0.247500 ;
    PORT
      LAYER met2 ;
        RECT 644.090 0.000 644.370 4.000 ;
    END
  END sstream_i[216]
  PIN sstream_i[217]
    DIRECTION INPUT ;
    USE SIGNAL ;
    ANTENNAGATEAREA 0.247500 ;
    PORT
      LAYER met2 ;
        RECT 646.850 0.000 647.130 4.000 ;
    END
  END sstream_i[217]
  PIN sstream_i[218]
    DIRECTION INPUT ;
    USE SIGNAL ;
    ANTENNAGATEAREA 0.247500 ;
    PORT
      LAYER met2 ;
        RECT 649.610 0.000 649.890 4.000 ;
    END
  END sstream_i[218]
  PIN sstream_i[219]
    DIRECTION INPUT ;
    USE SIGNAL ;
    ANTENNAGATEAREA 0.247500 ;
    PORT
      LAYER met2 ;
        RECT 652.370 0.000 652.650 4.000 ;
    END
  END sstream_i[219]
  PIN sstream_i[21]
    DIRECTION INPUT ;
    USE SIGNAL ;
    ANTENNAGATEAREA 0.247500 ;
    PORT
      LAYER met2 ;
        RECT 105.890 0.000 106.170 4.000 ;
    END
  END sstream_i[21]
  PIN sstream_i[220]
    DIRECTION INPUT ;
    USE SIGNAL ;
    ANTENNAGATEAREA 0.247500 ;
    PORT
      LAYER met2 ;
        RECT 655.130 0.000 655.410 4.000 ;
    END
  END sstream_i[220]
  PIN sstream_i[221]
    DIRECTION INPUT ;
    USE SIGNAL ;
    ANTENNAGATEAREA 0.426000 ;
    PORT
      LAYER met2 ;
        RECT 657.890 0.000 658.170 4.000 ;
    END
  END sstream_i[221]
  PIN sstream_i[222]
    DIRECTION INPUT ;
    USE SIGNAL ;
    ANTENNAGATEAREA 0.426000 ;
    PORT
      LAYER met2 ;
        RECT 660.650 0.000 660.930 4.000 ;
    END
  END sstream_i[222]
  PIN sstream_i[223]
    DIRECTION INPUT ;
    USE SIGNAL ;
    ANTENNAGATEAREA 0.247500 ;
    PORT
      LAYER met2 ;
        RECT 663.410 0.000 663.690 4.000 ;
    END
  END sstream_i[223]
  PIN sstream_i[224]
    DIRECTION INPUT ;
    USE SIGNAL ;
    ANTENNAGATEAREA 0.247500 ;
    PORT
      LAYER met2 ;
        RECT 666.170 0.000 666.450 4.000 ;
    END
  END sstream_i[224]
  PIN sstream_i[225]
    DIRECTION INPUT ;
    USE SIGNAL ;
    ANTENNAGATEAREA 0.247500 ;
    PORT
      LAYER met2 ;
        RECT 668.930 0.000 669.210 4.000 ;
    END
  END sstream_i[225]
  PIN sstream_i[226]
    DIRECTION INPUT ;
    USE SIGNAL ;
    ANTENNAGATEAREA 0.247500 ;
    PORT
      LAYER met2 ;
        RECT 671.690 0.000 671.970 4.000 ;
    END
  END sstream_i[226]
  PIN sstream_i[227]
    DIRECTION INPUT ;
    USE SIGNAL ;
    ANTENNAGATEAREA 0.247500 ;
    PORT
      LAYER met2 ;
        RECT 674.450 0.000 674.730 4.000 ;
    END
  END sstream_i[227]
  PIN sstream_i[228]
    DIRECTION INPUT ;
    USE SIGNAL ;
    ANTENNAGATEAREA 0.247500 ;
    PORT
      LAYER met2 ;
        RECT 677.210 0.000 677.490 4.000 ;
    END
  END sstream_i[228]
  PIN sstream_i[229]
    DIRECTION INPUT ;
    USE SIGNAL ;
    ANTENNAGATEAREA 0.247500 ;
    PORT
      LAYER met2 ;
        RECT 679.970 0.000 680.250 4.000 ;
    END
  END sstream_i[229]
  PIN sstream_i[22]
    DIRECTION INPUT ;
    USE SIGNAL ;
    ANTENNAGATEAREA 0.426000 ;
    PORT
      LAYER met2 ;
        RECT 108.650 0.000 108.930 4.000 ;
    END
  END sstream_i[22]
  PIN sstream_i[230]
    DIRECTION INPUT ;
    USE SIGNAL ;
    ANTENNAGATEAREA 0.247500 ;
    PORT
      LAYER met2 ;
        RECT 682.730 0.000 683.010 4.000 ;
    END
  END sstream_i[230]
  PIN sstream_i[231]
    DIRECTION INPUT ;
    USE SIGNAL ;
    ANTENNAGATEAREA 0.213000 ;
    PORT
      LAYER met2 ;
        RECT 685.490 0.000 685.770 4.000 ;
    END
  END sstream_i[231]
  PIN sstream_i[232]
    DIRECTION INPUT ;
    USE SIGNAL ;
    ANTENNAGATEAREA 0.159000 ;
    PORT
      LAYER met2 ;
        RECT 688.250 0.000 688.530 4.000 ;
    END
  END sstream_i[232]
  PIN sstream_i[233]
    DIRECTION INPUT ;
    USE SIGNAL ;
    ANTENNAGATEAREA 0.159000 ;
    PORT
      LAYER met2 ;
        RECT 691.010 0.000 691.290 4.000 ;
    END
  END sstream_i[233]
  PIN sstream_i[234]
    DIRECTION INPUT ;
    USE SIGNAL ;
    ANTENNAGATEAREA 0.213000 ;
    PORT
      LAYER met2 ;
        RECT 693.770 0.000 694.050 4.000 ;
    END
  END sstream_i[234]
  PIN sstream_i[235]
    DIRECTION INPUT ;
    USE SIGNAL ;
    ANTENNAGATEAREA 0.159000 ;
    PORT
      LAYER met2 ;
        RECT 696.530 0.000 696.810 4.000 ;
    END
  END sstream_i[235]
  PIN sstream_i[236]
    DIRECTION INPUT ;
    USE SIGNAL ;
    ANTENNAGATEAREA 0.159000 ;
    PORT
      LAYER met2 ;
        RECT 699.290 0.000 699.570 4.000 ;
    END
  END sstream_i[236]
  PIN sstream_i[237]
    DIRECTION INPUT ;
    USE SIGNAL ;
    ANTENNAGATEAREA 0.213000 ;
    PORT
      LAYER met2 ;
        RECT 702.050 0.000 702.330 4.000 ;
    END
  END sstream_i[237]
  PIN sstream_i[238]
    DIRECTION INPUT ;
    USE SIGNAL ;
    ANTENNAGATEAREA 0.213000 ;
    PORT
      LAYER met2 ;
        RECT 704.810 0.000 705.090 4.000 ;
    END
  END sstream_i[238]
  PIN sstream_i[239]
    DIRECTION INPUT ;
    USE SIGNAL ;
    ANTENNAGATEAREA 0.159000 ;
    PORT
      LAYER met2 ;
        RECT 707.570 0.000 707.850 4.000 ;
    END
  END sstream_i[239]
  PIN sstream_i[23]
    DIRECTION INPUT ;
    USE SIGNAL ;
    ANTENNAGATEAREA 0.247500 ;
    PORT
      LAYER met2 ;
        RECT 111.410 0.000 111.690 4.000 ;
    END
  END sstream_i[23]
  PIN sstream_i[240]
    DIRECTION INPUT ;
    USE SIGNAL ;
    ANTENNAGATEAREA 0.213000 ;
    PORT
      LAYER met2 ;
        RECT 710.330 0.000 710.610 4.000 ;
    END
  END sstream_i[240]
  PIN sstream_i[241]
    DIRECTION INPUT ;
    USE SIGNAL ;
    ANTENNAGATEAREA 0.213000 ;
    PORT
      LAYER met2 ;
        RECT 713.090 0.000 713.370 4.000 ;
    END
  END sstream_i[241]
  PIN sstream_i[242]
    DIRECTION INPUT ;
    USE SIGNAL ;
    ANTENNAGATEAREA 0.213000 ;
    PORT
      LAYER met2 ;
        RECT 715.850 0.000 716.130 4.000 ;
    END
  END sstream_i[242]
  PIN sstream_i[243]
    DIRECTION INPUT ;
    USE SIGNAL ;
    ANTENNAGATEAREA 0.213000 ;
    PORT
      LAYER met2 ;
        RECT 718.610 0.000 718.890 4.000 ;
    END
  END sstream_i[243]
  PIN sstream_i[244]
    DIRECTION INPUT ;
    USE SIGNAL ;
    ANTENNAGATEAREA 0.213000 ;
    PORT
      LAYER met2 ;
        RECT 721.370 0.000 721.650 4.000 ;
    END
  END sstream_i[244]
  PIN sstream_i[245]
    DIRECTION INPUT ;
    USE SIGNAL ;
    ANTENNAGATEAREA 0.213000 ;
    PORT
      LAYER met2 ;
        RECT 724.130 0.000 724.410 4.000 ;
    END
  END sstream_i[245]
  PIN sstream_i[246]
    DIRECTION INPUT ;
    USE SIGNAL ;
    ANTENNAGATEAREA 0.247500 ;
    PORT
      LAYER met2 ;
        RECT 726.890 0.000 727.170 4.000 ;
    END
  END sstream_i[246]
  PIN sstream_i[247]
    DIRECTION INPUT ;
    USE SIGNAL ;
    ANTENNAGATEAREA 0.213000 ;
    PORT
      LAYER met2 ;
        RECT 729.650 0.000 729.930 4.000 ;
    END
  END sstream_i[247]
  PIN sstream_i[248]
    DIRECTION INPUT ;
    USE SIGNAL ;
    ANTENNAGATEAREA 0.247500 ;
    PORT
      LAYER met2 ;
        RECT 732.410 0.000 732.690 4.000 ;
    END
  END sstream_i[248]
  PIN sstream_i[249]
    DIRECTION INPUT ;
    USE SIGNAL ;
    ANTENNAGATEAREA 0.213000 ;
    PORT
      LAYER met2 ;
        RECT 735.170 0.000 735.450 4.000 ;
    END
  END sstream_i[249]
  PIN sstream_i[24]
    DIRECTION INPUT ;
    USE SIGNAL ;
    ANTENNAGATEAREA 0.247500 ;
    PORT
      LAYER met2 ;
        RECT 114.170 0.000 114.450 4.000 ;
    END
  END sstream_i[24]
  PIN sstream_i[250]
    DIRECTION INPUT ;
    USE SIGNAL ;
    ANTENNAGATEAREA 0.213000 ;
    PORT
      LAYER met2 ;
        RECT 737.930 0.000 738.210 4.000 ;
    END
  END sstream_i[250]
  PIN sstream_i[251]
    DIRECTION INPUT ;
    USE SIGNAL ;
    ANTENNAGATEAREA 0.213000 ;
    PORT
      LAYER met2 ;
        RECT 740.690 0.000 740.970 4.000 ;
    END
  END sstream_i[251]
  PIN sstream_i[252]
    DIRECTION INPUT ;
    USE SIGNAL ;
    ANTENNAGATEAREA 0.213000 ;
    PORT
      LAYER met2 ;
        RECT 743.450 0.000 743.730 4.000 ;
    END
  END sstream_i[252]
  PIN sstream_i[253]
    DIRECTION INPUT ;
    USE SIGNAL ;
    ANTENNAGATEAREA 0.247500 ;
    PORT
      LAYER met2 ;
        RECT 746.210 0.000 746.490 4.000 ;
    END
  END sstream_i[253]
  PIN sstream_i[254]
    DIRECTION INPUT ;
    USE SIGNAL ;
    ANTENNAGATEAREA 0.247500 ;
    PORT
      LAYER met2 ;
        RECT 748.970 0.000 749.250 4.000 ;
    END
  END sstream_i[254]
  PIN sstream_i[255]
    DIRECTION INPUT ;
    USE SIGNAL ;
    ANTENNAGATEAREA 0.247500 ;
    PORT
      LAYER met2 ;
        RECT 751.730 0.000 752.010 4.000 ;
    END
  END sstream_i[255]
  PIN sstream_i[256]
    DIRECTION INPUT ;
    USE SIGNAL ;
    ANTENNAGATEAREA 0.213000 ;
    PORT
      LAYER met2 ;
        RECT 754.490 0.000 754.770 4.000 ;
    END
  END sstream_i[256]
  PIN sstream_i[257]
    DIRECTION INPUT ;
    USE SIGNAL ;
    ANTENNAGATEAREA 0.213000 ;
    PORT
      LAYER met2 ;
        RECT 757.250 0.000 757.530 4.000 ;
    END
  END sstream_i[257]
  PIN sstream_i[25]
    DIRECTION INPUT ;
    USE SIGNAL ;
    ANTENNAGATEAREA 0.247500 ;
    PORT
      LAYER met2 ;
        RECT 116.930 0.000 117.210 4.000 ;
    END
  END sstream_i[25]
  PIN sstream_i[26]
    DIRECTION INPUT ;
    USE SIGNAL ;
    ANTENNAGATEAREA 0.247500 ;
    PORT
      LAYER met2 ;
        RECT 119.690 0.000 119.970 4.000 ;
    END
  END sstream_i[26]
  PIN sstream_i[27]
    DIRECTION INPUT ;
    USE SIGNAL ;
    ANTENNAGATEAREA 0.213000 ;
    PORT
      LAYER met2 ;
        RECT 122.450 0.000 122.730 4.000 ;
    END
  END sstream_i[27]
  PIN sstream_i[28]
    DIRECTION INPUT ;
    USE SIGNAL ;
    ANTENNAGATEAREA 0.213000 ;
    PORT
      LAYER met2 ;
        RECT 125.210 0.000 125.490 4.000 ;
    END
  END sstream_i[28]
  PIN sstream_i[29]
    DIRECTION INPUT ;
    USE SIGNAL ;
    ANTENNAGATEAREA 0.247500 ;
    PORT
      LAYER met2 ;
        RECT 127.970 0.000 128.250 4.000 ;
    END
  END sstream_i[29]
  PIN sstream_i[2]
    DIRECTION INPUT ;
    USE SIGNAL ;
    ANTENNAGATEAREA 0.247500 ;
    PORT
      LAYER met2 ;
        RECT 53.450 0.000 53.730 4.000 ;
    END
  END sstream_i[2]
  PIN sstream_i[30]
    DIRECTION INPUT ;
    USE SIGNAL ;
    ANTENNAGATEAREA 0.247500 ;
    PORT
      LAYER met2 ;
        RECT 130.730 0.000 131.010 4.000 ;
    END
  END sstream_i[30]
  PIN sstream_i[31]
    DIRECTION INPUT ;
    USE SIGNAL ;
    ANTENNAGATEAREA 0.247500 ;
    PORT
      LAYER met2 ;
        RECT 133.490 0.000 133.770 4.000 ;
    END
  END sstream_i[31]
  PIN sstream_i[32]
    DIRECTION INPUT ;
    USE SIGNAL ;
    ANTENNAGATEAREA 0.247500 ;
    PORT
      LAYER met2 ;
        RECT 136.250 0.000 136.530 4.000 ;
    END
  END sstream_i[32]
  PIN sstream_i[33]
    DIRECTION INPUT ;
    USE SIGNAL ;
    ANTENNAGATEAREA 0.247500 ;
    PORT
      LAYER met2 ;
        RECT 139.010 0.000 139.290 4.000 ;
    END
  END sstream_i[33]
  PIN sstream_i[34]
    DIRECTION INPUT ;
    USE SIGNAL ;
    ANTENNAGATEAREA 0.247500 ;
    PORT
      LAYER met2 ;
        RECT 141.770 0.000 142.050 4.000 ;
    END
  END sstream_i[34]
  PIN sstream_i[35]
    DIRECTION INPUT ;
    USE SIGNAL ;
    ANTENNAGATEAREA 0.247500 ;
    PORT
      LAYER met2 ;
        RECT 144.530 0.000 144.810 4.000 ;
    END
  END sstream_i[35]
  PIN sstream_i[36]
    DIRECTION INPUT ;
    USE SIGNAL ;
    ANTENNAGATEAREA 0.247500 ;
    PORT
      LAYER met2 ;
        RECT 147.290 0.000 147.570 4.000 ;
    END
  END sstream_i[36]
  PIN sstream_i[37]
    DIRECTION INPUT ;
    USE SIGNAL ;
    ANTENNAGATEAREA 0.213000 ;
    PORT
      LAYER met2 ;
        RECT 150.050 0.000 150.330 4.000 ;
    END
  END sstream_i[37]
  PIN sstream_i[38]
    DIRECTION INPUT ;
    USE SIGNAL ;
    ANTENNAGATEAREA 0.247500 ;
    PORT
      LAYER met2 ;
        RECT 152.810 0.000 153.090 4.000 ;
    END
  END sstream_i[38]
  PIN sstream_i[39]
    DIRECTION INPUT ;
    USE SIGNAL ;
    ANTENNAGATEAREA 0.247500 ;
    PORT
      LAYER met2 ;
        RECT 155.570 0.000 155.850 4.000 ;
    END
  END sstream_i[39]
  PIN sstream_i[3]
    DIRECTION INPUT ;
    USE SIGNAL ;
    ANTENNAGATEAREA 0.247500 ;
    PORT
      LAYER met2 ;
        RECT 56.210 0.000 56.490 4.000 ;
    END
  END sstream_i[3]
  PIN sstream_i[40]
    DIRECTION INPUT ;
    USE SIGNAL ;
    ANTENNAGATEAREA 0.247500 ;
    PORT
      LAYER met2 ;
        RECT 158.330 0.000 158.610 4.000 ;
    END
  END sstream_i[40]
  PIN sstream_i[41]
    DIRECTION INPUT ;
    USE SIGNAL ;
    ANTENNAGATEAREA 0.247500 ;
    PORT
      LAYER met2 ;
        RECT 161.090 0.000 161.370 4.000 ;
    END
  END sstream_i[41]
  PIN sstream_i[42]
    DIRECTION INPUT ;
    USE SIGNAL ;
    ANTENNAGATEAREA 0.213000 ;
    PORT
      LAYER met2 ;
        RECT 163.850 0.000 164.130 4.000 ;
    END
  END sstream_i[42]
  PIN sstream_i[43]
    DIRECTION INPUT ;
    USE SIGNAL ;
    ANTENNAGATEAREA 0.213000 ;
    PORT
      LAYER met2 ;
        RECT 166.610 0.000 166.890 4.000 ;
    END
  END sstream_i[43]
  PIN sstream_i[44]
    DIRECTION INPUT ;
    USE SIGNAL ;
    ANTENNAGATEAREA 0.213000 ;
    PORT
      LAYER met2 ;
        RECT 169.370 0.000 169.650 4.000 ;
    END
  END sstream_i[44]
  PIN sstream_i[45]
    DIRECTION INPUT ;
    USE SIGNAL ;
    ANTENNAGATEAREA 0.213000 ;
    PORT
      LAYER met2 ;
        RECT 172.130 0.000 172.410 4.000 ;
    END
  END sstream_i[45]
  PIN sstream_i[46]
    DIRECTION INPUT ;
    USE SIGNAL ;
    ANTENNAGATEAREA 0.213000 ;
    PORT
      LAYER met2 ;
        RECT 174.890 0.000 175.170 4.000 ;
    END
  END sstream_i[46]
  PIN sstream_i[47]
    DIRECTION INPUT ;
    USE SIGNAL ;
    ANTENNAGATEAREA 0.213000 ;
    PORT
      LAYER met2 ;
        RECT 177.650 0.000 177.930 4.000 ;
    END
  END sstream_i[47]
  PIN sstream_i[48]
    DIRECTION INPUT ;
    USE SIGNAL ;
    ANTENNAGATEAREA 0.213000 ;
    PORT
      LAYER met2 ;
        RECT 180.410 0.000 180.690 4.000 ;
    END
  END sstream_i[48]
  PIN sstream_i[49]
    DIRECTION INPUT ;
    USE SIGNAL ;
    ANTENNAGATEAREA 0.213000 ;
    PORT
      LAYER met2 ;
        RECT 183.170 0.000 183.450 4.000 ;
    END
  END sstream_i[49]
  PIN sstream_i[4]
    DIRECTION INPUT ;
    USE SIGNAL ;
    ANTENNAGATEAREA 0.247500 ;
    PORT
      LAYER met2 ;
        RECT 58.970 0.000 59.250 4.000 ;
    END
  END sstream_i[4]
  PIN sstream_i[50]
    DIRECTION INPUT ;
    USE SIGNAL ;
    ANTENNAGATEAREA 0.213000 ;
    PORT
      LAYER met2 ;
        RECT 185.930 0.000 186.210 4.000 ;
    END
  END sstream_i[50]
  PIN sstream_i[51]
    DIRECTION INPUT ;
    USE SIGNAL ;
    ANTENNAGATEAREA 0.159000 ;
    PORT
      LAYER met2 ;
        RECT 188.690 0.000 188.970 4.000 ;
    END
  END sstream_i[51]
  PIN sstream_i[52]
    DIRECTION INPUT ;
    USE SIGNAL ;
    ANTENNAGATEAREA 0.213000 ;
    PORT
      LAYER met2 ;
        RECT 191.450 0.000 191.730 4.000 ;
    END
  END sstream_i[52]
  PIN sstream_i[53]
    DIRECTION INPUT ;
    USE SIGNAL ;
    ANTENNAGATEAREA 0.213000 ;
    PORT
      LAYER met2 ;
        RECT 194.210 0.000 194.490 4.000 ;
    END
  END sstream_i[53]
  PIN sstream_i[54]
    DIRECTION INPUT ;
    USE SIGNAL ;
    ANTENNAGATEAREA 0.213000 ;
    PORT
      LAYER met2 ;
        RECT 196.970 0.000 197.250 4.000 ;
    END
  END sstream_i[54]
  PIN sstream_i[55]
    DIRECTION INPUT ;
    USE SIGNAL ;
    ANTENNAGATEAREA 0.159000 ;
    PORT
      LAYER met2 ;
        RECT 199.730 0.000 200.010 4.000 ;
    END
  END sstream_i[55]
  PIN sstream_i[56]
    DIRECTION INPUT ;
    USE SIGNAL ;
    ANTENNAGATEAREA 0.213000 ;
    PORT
      LAYER met2 ;
        RECT 202.490 0.000 202.770 4.000 ;
    END
  END sstream_i[56]
  PIN sstream_i[57]
    DIRECTION INPUT ;
    USE SIGNAL ;
    ANTENNAGATEAREA 0.213000 ;
    PORT
      LAYER met2 ;
        RECT 205.250 0.000 205.530 4.000 ;
    END
  END sstream_i[57]
  PIN sstream_i[58]
    DIRECTION INPUT ;
    USE SIGNAL ;
    ANTENNAGATEAREA 0.213000 ;
    PORT
      LAYER met2 ;
        RECT 208.010 0.000 208.290 4.000 ;
    END
  END sstream_i[58]
  PIN sstream_i[59]
    DIRECTION INPUT ;
    USE SIGNAL ;
    ANTENNAGATEAREA 0.213000 ;
    PORT
      LAYER met2 ;
        RECT 210.770 0.000 211.050 4.000 ;
    END
  END sstream_i[59]
  PIN sstream_i[5]
    DIRECTION INPUT ;
    USE SIGNAL ;
    ANTENNAGATEAREA 0.247500 ;
    PORT
      LAYER met2 ;
        RECT 61.730 0.000 62.010 4.000 ;
    END
  END sstream_i[5]
  PIN sstream_i[60]
    DIRECTION INPUT ;
    USE SIGNAL ;
    ANTENNAGATEAREA 0.159000 ;
    PORT
      LAYER met2 ;
        RECT 213.530 0.000 213.810 4.000 ;
    END
  END sstream_i[60]
  PIN sstream_i[61]
    DIRECTION INPUT ;
    USE SIGNAL ;
    ANTENNAGATEAREA 0.159000 ;
    PORT
      LAYER met2 ;
        RECT 216.290 0.000 216.570 4.000 ;
    END
  END sstream_i[61]
  PIN sstream_i[62]
    DIRECTION INPUT ;
    USE SIGNAL ;
    ANTENNAGATEAREA 0.213000 ;
    PORT
      LAYER met2 ;
        RECT 219.050 0.000 219.330 4.000 ;
    END
  END sstream_i[62]
  PIN sstream_i[63]
    DIRECTION INPUT ;
    USE SIGNAL ;
    ANTENNAGATEAREA 0.213000 ;
    PORT
      LAYER met2 ;
        RECT 221.810 0.000 222.090 4.000 ;
    END
  END sstream_i[63]
  PIN sstream_i[64]
    DIRECTION INPUT ;
    USE SIGNAL ;
    ANTENNAGATEAREA 0.247500 ;
    PORT
      LAYER met2 ;
        RECT 224.570 0.000 224.850 4.000 ;
    END
  END sstream_i[64]
  PIN sstream_i[65]
    DIRECTION INPUT ;
    USE SIGNAL ;
    ANTENNAGATEAREA 0.213000 ;
    PORT
      LAYER met2 ;
        RECT 227.330 0.000 227.610 4.000 ;
    END
  END sstream_i[65]
  PIN sstream_i[66]
    DIRECTION INPUT ;
    USE SIGNAL ;
    ANTENNAGATEAREA 0.213000 ;
    PORT
      LAYER met2 ;
        RECT 230.090 0.000 230.370 4.000 ;
    END
  END sstream_i[66]
  PIN sstream_i[67]
    DIRECTION INPUT ;
    USE SIGNAL ;
    ANTENNAGATEAREA 0.159000 ;
    PORT
      LAYER met2 ;
        RECT 232.850 0.000 233.130 4.000 ;
    END
  END sstream_i[67]
  PIN sstream_i[68]
    DIRECTION INPUT ;
    USE SIGNAL ;
    ANTENNAGATEAREA 0.159000 ;
    PORT
      LAYER met2 ;
        RECT 235.610 0.000 235.890 4.000 ;
    END
  END sstream_i[68]
  PIN sstream_i[69]
    DIRECTION INPUT ;
    USE SIGNAL ;
    ANTENNAGATEAREA 0.213000 ;
    PORT
      LAYER met2 ;
        RECT 238.370 0.000 238.650 4.000 ;
    END
  END sstream_i[69]
  PIN sstream_i[6]
    DIRECTION INPUT ;
    USE SIGNAL ;
    ANTENNAGATEAREA 0.247500 ;
    PORT
      LAYER met2 ;
        RECT 64.490 0.000 64.770 4.000 ;
    END
  END sstream_i[6]
  PIN sstream_i[70]
    DIRECTION INPUT ;
    USE SIGNAL ;
    ANTENNAGATEAREA 0.213000 ;
    PORT
      LAYER met2 ;
        RECT 241.130 0.000 241.410 4.000 ;
    END
  END sstream_i[70]
  PIN sstream_i[71]
    DIRECTION INPUT ;
    USE SIGNAL ;
    ANTENNAGATEAREA 0.247500 ;
    PORT
      LAYER met2 ;
        RECT 243.890 0.000 244.170 4.000 ;
    END
  END sstream_i[71]
  PIN sstream_i[72]
    DIRECTION INPUT ;
    USE SIGNAL ;
    ANTENNAGATEAREA 0.247500 ;
    PORT
      LAYER met2 ;
        RECT 246.650 0.000 246.930 4.000 ;
    END
  END sstream_i[72]
  PIN sstream_i[73]
    DIRECTION INPUT ;
    USE SIGNAL ;
    ANTENNAGATEAREA 0.247500 ;
    PORT
      LAYER met2 ;
        RECT 249.410 0.000 249.690 4.000 ;
    END
  END sstream_i[73]
  PIN sstream_i[74]
    DIRECTION INPUT ;
    USE SIGNAL ;
    ANTENNAGATEAREA 0.213000 ;
    PORT
      LAYER met2 ;
        RECT 252.170 0.000 252.450 4.000 ;
    END
  END sstream_i[74]
  PIN sstream_i[75]
    DIRECTION INPUT ;
    USE SIGNAL ;
    ANTENNAGATEAREA 0.159000 ;
    PORT
      LAYER met2 ;
        RECT 254.930 0.000 255.210 4.000 ;
    END
  END sstream_i[75]
  PIN sstream_i[76]
    DIRECTION INPUT ;
    USE SIGNAL ;
    ANTENNAGATEAREA 0.213000 ;
    PORT
      LAYER met2 ;
        RECT 257.690 0.000 257.970 4.000 ;
    END
  END sstream_i[76]
  PIN sstream_i[77]
    DIRECTION INPUT ;
    USE SIGNAL ;
    ANTENNAGATEAREA 0.213000 ;
    PORT
      LAYER met2 ;
        RECT 260.450 0.000 260.730 4.000 ;
    END
  END sstream_i[77]
  PIN sstream_i[78]
    DIRECTION INPUT ;
    USE SIGNAL ;
    ANTENNAGATEAREA 0.247500 ;
    PORT
      LAYER met2 ;
        RECT 263.210 0.000 263.490 4.000 ;
    END
  END sstream_i[78]
  PIN sstream_i[79]
    DIRECTION INPUT ;
    USE SIGNAL ;
    ANTENNAGATEAREA 0.247500 ;
    PORT
      LAYER met2 ;
        RECT 265.970 0.000 266.250 4.000 ;
    END
  END sstream_i[79]
  PIN sstream_i[7]
    DIRECTION INPUT ;
    USE SIGNAL ;
    ANTENNAGATEAREA 0.247500 ;
    PORT
      LAYER met2 ;
        RECT 67.250 0.000 67.530 4.000 ;
    END
  END sstream_i[7]
  PIN sstream_i[80]
    DIRECTION INPUT ;
    USE SIGNAL ;
    ANTENNAGATEAREA 0.247500 ;
    PORT
      LAYER met2 ;
        RECT 268.730 0.000 269.010 4.000 ;
    END
  END sstream_i[80]
  PIN sstream_i[81]
    DIRECTION INPUT ;
    USE SIGNAL ;
    ANTENNAGATEAREA 0.213000 ;
    PORT
      LAYER met2 ;
        RECT 271.490 0.000 271.770 4.000 ;
    END
  END sstream_i[81]
  PIN sstream_i[82]
    DIRECTION INPUT ;
    USE SIGNAL ;
    ANTENNAGATEAREA 0.213000 ;
    PORT
      LAYER met2 ;
        RECT 274.250 0.000 274.530 4.000 ;
    END
  END sstream_i[82]
  PIN sstream_i[83]
    DIRECTION INPUT ;
    USE SIGNAL ;
    ANTENNAGATEAREA 0.159000 ;
    PORT
      LAYER met2 ;
        RECT 277.010 0.000 277.290 4.000 ;
    END
  END sstream_i[83]
  PIN sstream_i[84]
    DIRECTION INPUT ;
    USE SIGNAL ;
    ANTENNAGATEAREA 0.213000 ;
    PORT
      LAYER met2 ;
        RECT 279.770 0.000 280.050 4.000 ;
    END
  END sstream_i[84]
  PIN sstream_i[85]
    DIRECTION INPUT ;
    USE SIGNAL ;
    ANTENNAGATEAREA 0.213000 ;
    PORT
      LAYER met2 ;
        RECT 282.530 0.000 282.810 4.000 ;
    END
  END sstream_i[85]
  PIN sstream_i[86]
    DIRECTION INPUT ;
    USE SIGNAL ;
    ANTENNAGATEAREA 0.247500 ;
    PORT
      LAYER met2 ;
        RECT 285.290 0.000 285.570 4.000 ;
    END
  END sstream_i[86]
  PIN sstream_i[87]
    DIRECTION INPUT ;
    USE SIGNAL ;
    ANTENNAGATEAREA 0.247500 ;
    PORT
      LAYER met2 ;
        RECT 288.050 0.000 288.330 4.000 ;
    END
  END sstream_i[87]
  PIN sstream_i[88]
    DIRECTION INPUT ;
    USE SIGNAL ;
    ANTENNAGATEAREA 0.247500 ;
    PORT
      LAYER met2 ;
        RECT 290.810 0.000 291.090 4.000 ;
    END
  END sstream_i[88]
  PIN sstream_i[89]
    DIRECTION INPUT ;
    USE SIGNAL ;
    ANTENNAGATEAREA 0.213000 ;
    PORT
      LAYER met2 ;
        RECT 293.570 0.000 293.850 4.000 ;
    END
  END sstream_i[89]
  PIN sstream_i[8]
    DIRECTION INPUT ;
    USE SIGNAL ;
    ANTENNAGATEAREA 0.247500 ;
    PORT
      LAYER met2 ;
        RECT 70.010 0.000 70.290 4.000 ;
    END
  END sstream_i[8]
  PIN sstream_i[90]
    DIRECTION INPUT ;
    USE SIGNAL ;
    ANTENNAGATEAREA 0.159000 ;
    PORT
      LAYER met2 ;
        RECT 296.330 0.000 296.610 4.000 ;
    END
  END sstream_i[90]
  PIN sstream_i[91]
    DIRECTION INPUT ;
    USE SIGNAL ;
    ANTENNAGATEAREA 0.159000 ;
    PORT
      LAYER met2 ;
        RECT 299.090 0.000 299.370 4.000 ;
    END
  END sstream_i[91]
  PIN sstream_i[92]
    DIRECTION INPUT ;
    USE SIGNAL ;
    ANTENNAGATEAREA 0.213000 ;
    PORT
      LAYER met2 ;
        RECT 301.850 0.000 302.130 4.000 ;
    END
  END sstream_i[92]
  PIN sstream_i[93]
    DIRECTION INPUT ;
    USE SIGNAL ;
    ANTENNAGATEAREA 0.213000 ;
    PORT
      LAYER met2 ;
        RECT 304.610 0.000 304.890 4.000 ;
    END
  END sstream_i[93]
  PIN sstream_i[94]
    DIRECTION INPUT ;
    USE SIGNAL ;
    ANTENNAGATEAREA 0.247500 ;
    PORT
      LAYER met2 ;
        RECT 307.370 0.000 307.650 4.000 ;
    END
  END sstream_i[94]
  PIN sstream_i[95]
    DIRECTION INPUT ;
    USE SIGNAL ;
    ANTENNAGATEAREA 0.247500 ;
    PORT
      LAYER met2 ;
        RECT 310.130 0.000 310.410 4.000 ;
    END
  END sstream_i[95]
  PIN sstream_i[96]
    DIRECTION INPUT ;
    USE SIGNAL ;
    ANTENNAGATEAREA 0.247500 ;
    PORT
      LAYER met2 ;
        RECT 312.890 0.000 313.170 4.000 ;
    END
  END sstream_i[96]
  PIN sstream_i[97]
    DIRECTION INPUT ;
    USE SIGNAL ;
    ANTENNAGATEAREA 0.213000 ;
    PORT
      LAYER met2 ;
        RECT 315.650 0.000 315.930 4.000 ;
    END
  END sstream_i[97]
  PIN sstream_i[98]
    DIRECTION INPUT ;
    USE SIGNAL ;
    ANTENNAGATEAREA 0.213000 ;
    PORT
      LAYER met2 ;
        RECT 318.410 0.000 318.690 4.000 ;
    END
  END sstream_i[98]
  PIN sstream_i[99]
    DIRECTION INPUT ;
    USE SIGNAL ;
    ANTENNAGATEAREA 0.213000 ;
    PORT
      LAYER met2 ;
        RECT 321.170 0.000 321.450 4.000 ;
    END
  END sstream_i[99]
  PIN sstream_i[9]
    DIRECTION INPUT ;
    USE SIGNAL ;
    ANTENNAGATEAREA 0.247500 ;
    PORT
      LAYER met2 ;
        RECT 72.770 0.000 73.050 4.000 ;
    END
  END sstream_i[9]
  PIN sstream_o
    DIRECTION OUTPUT TRISTATE ;
    USE SIGNAL ;
    ANTENNADIFFAREA 0.795200 ;
    PORT
      LAYER met2 ;
        RECT 760.010 0.000 760.290 4.000 ;
    END
  END sstream_o
  PIN vccd1
    DIRECTION INOUT ;
    USE POWER ;
    PORT
      LAYER met4 ;
        RECT -2.080 3.280 -0.480 546.160 ;
    END
    PORT
      LAYER met5 ;
        RECT -2.080 3.280 802.020 4.880 ;
    END
    PORT
      LAYER met5 ;
        RECT -2.080 544.560 802.020 546.160 ;
    END
    PORT
      LAYER met4 ;
        RECT 800.420 3.280 802.020 546.160 ;
    END
    PORT
      LAYER met4 ;
        RECT 21.040 -0.020 22.640 549.460 ;
    END
    PORT
      LAYER met4 ;
        RECT 174.640 -0.020 176.240 549.460 ;
    END
    PORT
      LAYER met4 ;
        RECT 328.240 -0.020 329.840 549.460 ;
    END
    PORT
      LAYER met4 ;
        RECT 481.840 -0.020 483.440 549.460 ;
    END
    PORT
      LAYER met4 ;
        RECT 635.440 -0.020 637.040 549.460 ;
    END
    PORT
      LAYER met4 ;
        RECT 789.040 -0.020 790.640 549.460 ;
    END
    PORT
      LAYER met5 ;
        RECT -5.380 26.730 805.320 28.330 ;
    END
    PORT
      LAYER met5 ;
        RECT -5.380 179.910 805.320 181.510 ;
    END
    PORT
      LAYER met5 ;
        RECT -5.380 333.090 805.320 334.690 ;
    END
    PORT
      LAYER met5 ;
        RECT -5.380 486.270 805.320 487.870 ;
    END
  END vccd1
  PIN vssd1
    DIRECTION INOUT ;
    USE GROUND ;
    PORT
      LAYER met4 ;
        RECT -5.380 -0.020 -3.780 549.460 ;
    END
    PORT
      LAYER met5 ;
        RECT -5.380 -0.020 805.320 1.580 ;
    END
    PORT
      LAYER met5 ;
        RECT -5.380 547.860 805.320 549.460 ;
    END
    PORT
      LAYER met4 ;
        RECT 803.720 -0.020 805.320 549.460 ;
    END
    PORT
      LAYER met4 ;
        RECT 24.340 -0.020 25.940 549.460 ;
    END
    PORT
      LAYER met4 ;
        RECT 177.940 -0.020 179.540 549.460 ;
    END
    PORT
      LAYER met4 ;
        RECT 331.540 -0.020 333.140 549.460 ;
    END
    PORT
      LAYER met4 ;
        RECT 485.140 -0.020 486.740 549.460 ;
    END
    PORT
      LAYER met4 ;
        RECT 638.740 -0.020 640.340 549.460 ;
    END
    PORT
      LAYER met4 ;
        RECT 792.340 -0.020 793.940 549.460 ;
    END
    PORT
      LAYER met5 ;
        RECT -5.380 30.030 805.320 31.630 ;
    END
    PORT
      LAYER met5 ;
        RECT -5.380 183.210 805.320 184.810 ;
    END
    PORT
      LAYER met5 ;
        RECT -5.380 336.390 805.320 337.990 ;
    END
    PORT
      LAYER met5 ;
        RECT -5.380 489.570 805.320 491.170 ;
    END
  END vssd1
  OBS
      LAYER li1 ;
        RECT 5.520 10.795 794.420 538.645 ;
      LAYER met1 ;
        RECT 4.670 9.900 794.810 547.020 ;
      LAYER met2 ;
        RECT 4.690 545.720 55.930 547.925 ;
        RECT 56.770 545.720 56.850 547.925 ;
        RECT 57.690 545.720 57.770 547.925 ;
        RECT 58.610 545.720 58.690 547.925 ;
        RECT 59.530 545.720 59.610 547.925 ;
        RECT 60.450 545.720 60.530 547.925 ;
        RECT 61.370 545.720 61.450 547.925 ;
        RECT 62.290 545.720 62.370 547.925 ;
        RECT 63.210 545.720 63.290 547.925 ;
        RECT 64.130 545.720 64.210 547.925 ;
        RECT 65.050 545.720 65.130 547.925 ;
        RECT 65.970 545.720 66.050 547.925 ;
        RECT 66.890 545.720 66.970 547.925 ;
        RECT 67.810 545.720 67.890 547.925 ;
        RECT 68.730 545.720 68.810 547.925 ;
        RECT 69.650 545.720 69.730 547.925 ;
        RECT 70.570 545.720 70.650 547.925 ;
        RECT 71.490 545.720 71.570 547.925 ;
        RECT 72.410 545.720 72.490 547.925 ;
        RECT 73.330 545.720 73.410 547.925 ;
        RECT 74.250 545.720 74.330 547.925 ;
        RECT 75.170 545.720 75.250 547.925 ;
        RECT 76.090 545.720 76.170 547.925 ;
        RECT 77.010 545.720 77.090 547.925 ;
        RECT 77.930 545.720 78.010 547.925 ;
        RECT 78.850 545.720 78.930 547.925 ;
        RECT 79.770 545.720 79.850 547.925 ;
        RECT 80.690 545.720 80.770 547.925 ;
        RECT 81.610 545.720 81.690 547.925 ;
        RECT 82.530 545.720 82.610 547.925 ;
        RECT 83.450 545.720 83.530 547.925 ;
        RECT 84.370 545.720 84.450 547.925 ;
        RECT 85.290 545.720 85.370 547.925 ;
        RECT 86.210 545.720 86.290 547.925 ;
        RECT 87.130 545.720 87.210 547.925 ;
        RECT 88.050 545.720 88.130 547.925 ;
        RECT 88.970 545.720 89.050 547.925 ;
        RECT 89.890 545.720 89.970 547.925 ;
        RECT 90.810 545.720 90.890 547.925 ;
        RECT 91.730 545.720 91.810 547.925 ;
        RECT 92.650 545.720 92.730 547.925 ;
        RECT 93.570 545.720 93.650 547.925 ;
        RECT 94.490 545.720 94.570 547.925 ;
        RECT 95.410 545.720 95.490 547.925 ;
        RECT 96.330 545.720 96.410 547.925 ;
        RECT 97.250 545.720 97.330 547.925 ;
        RECT 98.170 545.720 98.250 547.925 ;
        RECT 99.090 545.720 99.170 547.925 ;
        RECT 100.010 545.720 100.090 547.925 ;
        RECT 100.930 545.720 101.010 547.925 ;
        RECT 101.850 545.720 101.930 547.925 ;
        RECT 102.770 545.720 102.850 547.925 ;
        RECT 103.690 545.720 103.770 547.925 ;
        RECT 104.610 545.720 104.690 547.925 ;
        RECT 105.530 545.720 105.610 547.925 ;
        RECT 106.450 545.720 106.530 547.925 ;
        RECT 107.370 545.720 107.450 547.925 ;
        RECT 108.290 545.720 108.370 547.925 ;
        RECT 109.210 545.720 109.290 547.925 ;
        RECT 110.130 545.720 110.210 547.925 ;
        RECT 111.050 545.720 111.130 547.925 ;
        RECT 111.970 545.720 112.050 547.925 ;
        RECT 112.890 545.720 112.970 547.925 ;
        RECT 113.810 545.720 113.890 547.925 ;
        RECT 114.730 545.720 114.810 547.925 ;
        RECT 115.650 545.720 115.730 547.925 ;
        RECT 116.570 545.720 116.650 547.925 ;
        RECT 117.490 545.720 117.570 547.925 ;
        RECT 118.410 545.720 118.490 547.925 ;
        RECT 119.330 545.720 119.410 547.925 ;
        RECT 120.250 545.720 120.330 547.925 ;
        RECT 121.170 545.720 121.250 547.925 ;
        RECT 122.090 545.720 122.170 547.925 ;
        RECT 123.010 545.720 123.090 547.925 ;
        RECT 123.930 545.720 124.010 547.925 ;
        RECT 124.850 545.720 124.930 547.925 ;
        RECT 125.770 545.720 125.850 547.925 ;
        RECT 126.690 545.720 126.770 547.925 ;
        RECT 127.610 545.720 127.690 547.925 ;
        RECT 128.530 545.720 128.610 547.925 ;
        RECT 129.450 545.720 129.530 547.925 ;
        RECT 130.370 545.720 130.450 547.925 ;
        RECT 131.290 545.720 131.370 547.925 ;
        RECT 132.210 545.720 132.290 547.925 ;
        RECT 133.130 545.720 133.210 547.925 ;
        RECT 134.050 545.720 134.130 547.925 ;
        RECT 134.970 545.720 135.050 547.925 ;
        RECT 135.890 545.720 135.970 547.925 ;
        RECT 136.810 545.720 136.890 547.925 ;
        RECT 137.730 545.720 137.810 547.925 ;
        RECT 138.650 545.720 138.730 547.925 ;
        RECT 139.570 545.720 139.650 547.925 ;
        RECT 140.490 545.720 140.570 547.925 ;
        RECT 141.410 545.720 141.490 547.925 ;
        RECT 142.330 545.720 142.410 547.925 ;
        RECT 143.250 545.720 143.330 547.925 ;
        RECT 144.170 545.720 144.250 547.925 ;
        RECT 145.090 545.720 145.170 547.925 ;
        RECT 146.010 545.720 146.090 547.925 ;
        RECT 146.930 545.720 147.010 547.925 ;
        RECT 147.850 545.720 147.930 547.925 ;
        RECT 148.770 545.720 148.850 547.925 ;
        RECT 149.690 545.720 149.770 547.925 ;
        RECT 150.610 545.720 150.690 547.925 ;
        RECT 151.530 545.720 151.610 547.925 ;
        RECT 152.450 545.720 152.530 547.925 ;
        RECT 153.370 545.720 153.450 547.925 ;
        RECT 154.290 545.720 154.370 547.925 ;
        RECT 155.210 545.720 155.290 547.925 ;
        RECT 156.130 545.720 156.210 547.925 ;
        RECT 157.050 545.720 157.130 547.925 ;
        RECT 157.970 545.720 158.050 547.925 ;
        RECT 158.890 545.720 158.970 547.925 ;
        RECT 159.810 545.720 159.890 547.925 ;
        RECT 160.730 545.720 160.810 547.925 ;
        RECT 161.650 545.720 161.730 547.925 ;
        RECT 162.570 545.720 162.650 547.925 ;
        RECT 163.490 545.720 163.570 547.925 ;
        RECT 164.410 545.720 164.490 547.925 ;
        RECT 165.330 545.720 165.410 547.925 ;
        RECT 166.250 545.720 166.330 547.925 ;
        RECT 167.170 545.720 167.250 547.925 ;
        RECT 168.090 545.720 168.170 547.925 ;
        RECT 169.010 545.720 169.090 547.925 ;
        RECT 169.930 545.720 170.010 547.925 ;
        RECT 170.850 545.720 170.930 547.925 ;
        RECT 171.770 545.720 171.850 547.925 ;
        RECT 172.690 545.720 172.770 547.925 ;
        RECT 173.610 545.720 173.690 547.925 ;
        RECT 174.530 545.720 174.610 547.925 ;
        RECT 175.450 545.720 175.530 547.925 ;
        RECT 176.370 545.720 176.450 547.925 ;
        RECT 177.290 545.720 177.370 547.925 ;
        RECT 178.210 545.720 178.290 547.925 ;
        RECT 179.130 545.720 179.210 547.925 ;
        RECT 180.050 545.720 180.130 547.925 ;
        RECT 180.970 545.720 181.050 547.925 ;
        RECT 181.890 545.720 181.970 547.925 ;
        RECT 182.810 545.720 182.890 547.925 ;
        RECT 183.730 545.720 183.810 547.925 ;
        RECT 184.650 545.720 184.730 547.925 ;
        RECT 185.570 545.720 185.650 547.925 ;
        RECT 186.490 545.720 186.570 547.925 ;
        RECT 187.410 545.720 187.490 547.925 ;
        RECT 188.330 545.720 188.410 547.925 ;
        RECT 189.250 545.720 189.330 547.925 ;
        RECT 190.170 545.720 190.250 547.925 ;
        RECT 191.090 545.720 191.170 547.925 ;
        RECT 192.010 545.720 192.090 547.925 ;
        RECT 192.930 545.720 193.010 547.925 ;
        RECT 193.850 545.720 193.930 547.925 ;
        RECT 194.770 545.720 194.850 547.925 ;
        RECT 195.690 545.720 195.770 547.925 ;
        RECT 196.610 545.720 196.690 547.925 ;
        RECT 197.530 545.720 197.610 547.925 ;
        RECT 198.450 545.720 198.530 547.925 ;
        RECT 199.370 545.720 199.450 547.925 ;
        RECT 200.290 545.720 200.370 547.925 ;
        RECT 201.210 545.720 201.290 547.925 ;
        RECT 202.130 545.720 202.210 547.925 ;
        RECT 203.050 545.720 203.130 547.925 ;
        RECT 203.970 545.720 204.050 547.925 ;
        RECT 204.890 545.720 204.970 547.925 ;
        RECT 205.810 545.720 205.890 547.925 ;
        RECT 206.730 545.720 206.810 547.925 ;
        RECT 207.650 545.720 207.730 547.925 ;
        RECT 208.570 545.720 208.650 547.925 ;
        RECT 209.490 545.720 209.570 547.925 ;
        RECT 210.410 545.720 210.490 547.925 ;
        RECT 211.330 545.720 211.410 547.925 ;
        RECT 212.250 545.720 212.330 547.925 ;
        RECT 213.170 545.720 213.250 547.925 ;
        RECT 214.090 545.720 214.170 547.925 ;
        RECT 215.010 545.720 215.090 547.925 ;
        RECT 215.930 545.720 216.010 547.925 ;
        RECT 216.850 545.720 216.930 547.925 ;
        RECT 217.770 545.720 217.850 547.925 ;
        RECT 218.690 545.720 218.770 547.925 ;
        RECT 219.610 545.720 219.690 547.925 ;
        RECT 220.530 545.720 220.610 547.925 ;
        RECT 221.450 545.720 221.530 547.925 ;
        RECT 222.370 545.720 222.450 547.925 ;
        RECT 223.290 545.720 223.370 547.925 ;
        RECT 224.210 545.720 224.290 547.925 ;
        RECT 225.130 545.720 225.210 547.925 ;
        RECT 226.050 545.720 226.130 547.925 ;
        RECT 226.970 545.720 227.050 547.925 ;
        RECT 227.890 545.720 227.970 547.925 ;
        RECT 228.810 545.720 228.890 547.925 ;
        RECT 229.730 545.720 229.810 547.925 ;
        RECT 230.650 545.720 230.730 547.925 ;
        RECT 231.570 545.720 231.650 547.925 ;
        RECT 232.490 545.720 232.570 547.925 ;
        RECT 233.410 545.720 233.490 547.925 ;
        RECT 234.330 545.720 234.410 547.925 ;
        RECT 235.250 545.720 235.330 547.925 ;
        RECT 236.170 545.720 236.250 547.925 ;
        RECT 237.090 545.720 237.170 547.925 ;
        RECT 238.010 545.720 238.090 547.925 ;
        RECT 238.930 545.720 239.010 547.925 ;
        RECT 239.850 545.720 239.930 547.925 ;
        RECT 240.770 545.720 240.850 547.925 ;
        RECT 241.690 545.720 241.770 547.925 ;
        RECT 242.610 545.720 242.690 547.925 ;
        RECT 243.530 545.720 243.610 547.925 ;
        RECT 244.450 545.720 244.530 547.925 ;
        RECT 245.370 545.720 245.450 547.925 ;
        RECT 246.290 545.720 246.370 547.925 ;
        RECT 247.210 545.720 247.290 547.925 ;
        RECT 248.130 545.720 248.210 547.925 ;
        RECT 249.050 545.720 249.130 547.925 ;
        RECT 249.970 545.720 250.050 547.925 ;
        RECT 250.890 545.720 250.970 547.925 ;
        RECT 251.810 545.720 251.890 547.925 ;
        RECT 252.730 545.720 252.810 547.925 ;
        RECT 253.650 545.720 253.730 547.925 ;
        RECT 254.570 545.720 254.650 547.925 ;
        RECT 255.490 545.720 255.570 547.925 ;
        RECT 256.410 545.720 256.490 547.925 ;
        RECT 257.330 545.720 257.410 547.925 ;
        RECT 258.250 545.720 258.330 547.925 ;
        RECT 259.170 545.720 259.250 547.925 ;
        RECT 260.090 545.720 260.170 547.925 ;
        RECT 261.010 545.720 261.090 547.925 ;
        RECT 261.930 545.720 262.010 547.925 ;
        RECT 262.850 545.720 262.930 547.925 ;
        RECT 263.770 545.720 263.850 547.925 ;
        RECT 264.690 545.720 264.770 547.925 ;
        RECT 265.610 545.720 265.690 547.925 ;
        RECT 266.530 545.720 266.610 547.925 ;
        RECT 267.450 545.720 267.530 547.925 ;
        RECT 268.370 545.720 268.450 547.925 ;
        RECT 269.290 545.720 269.370 547.925 ;
        RECT 270.210 545.720 270.290 547.925 ;
        RECT 271.130 545.720 271.210 547.925 ;
        RECT 272.050 545.720 272.130 547.925 ;
        RECT 272.970 545.720 273.050 547.925 ;
        RECT 273.890 545.720 273.970 547.925 ;
        RECT 274.810 545.720 274.890 547.925 ;
        RECT 275.730 545.720 275.810 547.925 ;
        RECT 276.650 545.720 276.730 547.925 ;
        RECT 277.570 545.720 277.650 547.925 ;
        RECT 278.490 545.720 278.570 547.925 ;
        RECT 279.410 545.720 279.490 547.925 ;
        RECT 280.330 545.720 280.410 547.925 ;
        RECT 281.250 545.720 281.330 547.925 ;
        RECT 282.170 545.720 282.250 547.925 ;
        RECT 283.090 545.720 283.170 547.925 ;
        RECT 284.010 545.720 284.090 547.925 ;
        RECT 284.930 545.720 285.010 547.925 ;
        RECT 285.850 545.720 285.930 547.925 ;
        RECT 286.770 545.720 286.850 547.925 ;
        RECT 287.690 545.720 287.770 547.925 ;
        RECT 288.610 545.720 288.690 547.925 ;
        RECT 289.530 545.720 289.610 547.925 ;
        RECT 290.450 545.720 290.530 547.925 ;
        RECT 291.370 545.720 291.450 547.925 ;
        RECT 292.290 545.720 292.370 547.925 ;
        RECT 293.210 545.720 293.290 547.925 ;
        RECT 294.130 545.720 294.210 547.925 ;
        RECT 295.050 545.720 295.130 547.925 ;
        RECT 295.970 545.720 296.050 547.925 ;
        RECT 296.890 545.720 296.970 547.925 ;
        RECT 297.810 545.720 297.890 547.925 ;
        RECT 298.730 545.720 298.810 547.925 ;
        RECT 299.650 545.720 299.730 547.925 ;
        RECT 300.570 545.720 300.650 547.925 ;
        RECT 301.490 545.720 301.570 547.925 ;
        RECT 302.410 545.720 302.490 547.925 ;
        RECT 303.330 545.720 303.410 547.925 ;
        RECT 304.250 545.720 304.330 547.925 ;
        RECT 305.170 545.720 305.250 547.925 ;
        RECT 306.090 545.720 306.170 547.925 ;
        RECT 307.010 545.720 307.090 547.925 ;
        RECT 307.930 545.720 308.010 547.925 ;
        RECT 308.850 545.720 308.930 547.925 ;
        RECT 309.770 545.720 309.850 547.925 ;
        RECT 310.690 545.720 310.770 547.925 ;
        RECT 311.610 545.720 311.690 547.925 ;
        RECT 312.530 545.720 312.610 547.925 ;
        RECT 313.450 545.720 313.530 547.925 ;
        RECT 314.370 545.720 314.450 547.925 ;
        RECT 315.290 545.720 315.370 547.925 ;
        RECT 316.210 545.720 316.290 547.925 ;
        RECT 317.130 545.720 317.210 547.925 ;
        RECT 318.050 545.720 318.130 547.925 ;
        RECT 318.970 545.720 319.050 547.925 ;
        RECT 319.890 545.720 319.970 547.925 ;
        RECT 320.810 545.720 320.890 547.925 ;
        RECT 321.730 545.720 321.810 547.925 ;
        RECT 322.650 545.720 322.730 547.925 ;
        RECT 323.570 545.720 323.650 547.925 ;
        RECT 324.490 545.720 324.570 547.925 ;
        RECT 325.410 545.720 325.490 547.925 ;
        RECT 326.330 545.720 326.410 547.925 ;
        RECT 327.250 545.720 327.330 547.925 ;
        RECT 328.170 545.720 328.250 547.925 ;
        RECT 329.090 545.720 329.170 547.925 ;
        RECT 330.010 545.720 330.090 547.925 ;
        RECT 330.930 545.720 331.010 547.925 ;
        RECT 331.850 545.720 331.930 547.925 ;
        RECT 332.770 545.720 332.850 547.925 ;
        RECT 333.690 545.720 333.770 547.925 ;
        RECT 334.610 545.720 334.690 547.925 ;
        RECT 335.530 545.720 335.610 547.925 ;
        RECT 336.450 545.720 336.530 547.925 ;
        RECT 337.370 545.720 337.450 547.925 ;
        RECT 338.290 545.720 338.370 547.925 ;
        RECT 339.210 545.720 339.290 547.925 ;
        RECT 340.130 545.720 340.210 547.925 ;
        RECT 341.050 545.720 341.130 547.925 ;
        RECT 341.970 545.720 342.050 547.925 ;
        RECT 342.890 545.720 342.970 547.925 ;
        RECT 343.810 545.720 343.890 547.925 ;
        RECT 344.730 545.720 344.810 547.925 ;
        RECT 345.650 545.720 345.730 547.925 ;
        RECT 346.570 545.720 346.650 547.925 ;
        RECT 347.490 545.720 347.570 547.925 ;
        RECT 348.410 545.720 348.490 547.925 ;
        RECT 349.330 545.720 349.410 547.925 ;
        RECT 350.250 545.720 350.330 547.925 ;
        RECT 351.170 545.720 351.250 547.925 ;
        RECT 352.090 545.720 352.170 547.925 ;
        RECT 353.010 545.720 353.090 547.925 ;
        RECT 353.930 545.720 354.010 547.925 ;
        RECT 354.850 545.720 354.930 547.925 ;
        RECT 355.770 545.720 355.850 547.925 ;
        RECT 356.690 545.720 356.770 547.925 ;
        RECT 357.610 545.720 357.690 547.925 ;
        RECT 358.530 545.720 358.610 547.925 ;
        RECT 359.450 545.720 359.530 547.925 ;
        RECT 360.370 545.720 360.450 547.925 ;
        RECT 361.290 545.720 361.370 547.925 ;
        RECT 362.210 545.720 362.290 547.925 ;
        RECT 363.130 545.720 363.210 547.925 ;
        RECT 364.050 545.720 364.130 547.925 ;
        RECT 364.970 545.720 365.050 547.925 ;
        RECT 365.890 545.720 365.970 547.925 ;
        RECT 366.810 545.720 366.890 547.925 ;
        RECT 367.730 545.720 367.810 547.925 ;
        RECT 368.650 545.720 368.730 547.925 ;
        RECT 369.570 545.720 369.650 547.925 ;
        RECT 370.490 545.720 370.570 547.925 ;
        RECT 371.410 545.720 371.490 547.925 ;
        RECT 372.330 545.720 372.410 547.925 ;
        RECT 373.250 545.720 373.330 547.925 ;
        RECT 374.170 545.720 374.250 547.925 ;
        RECT 375.090 545.720 375.170 547.925 ;
        RECT 376.010 545.720 376.090 547.925 ;
        RECT 376.930 545.720 377.010 547.925 ;
        RECT 377.850 545.720 377.930 547.925 ;
        RECT 378.770 545.720 378.850 547.925 ;
        RECT 379.690 545.720 379.770 547.925 ;
        RECT 380.610 545.720 380.690 547.925 ;
        RECT 381.530 545.720 381.610 547.925 ;
        RECT 382.450 545.720 382.530 547.925 ;
        RECT 383.370 545.720 383.450 547.925 ;
        RECT 384.290 545.720 384.370 547.925 ;
        RECT 385.210 545.720 385.290 547.925 ;
        RECT 386.130 545.720 386.210 547.925 ;
        RECT 387.050 545.720 387.130 547.925 ;
        RECT 387.970 545.720 388.050 547.925 ;
        RECT 388.890 545.720 388.970 547.925 ;
        RECT 389.810 545.720 389.890 547.925 ;
        RECT 390.730 545.720 390.810 547.925 ;
        RECT 391.650 545.720 391.730 547.925 ;
        RECT 392.570 545.720 392.650 547.925 ;
        RECT 393.490 545.720 393.570 547.925 ;
        RECT 394.410 545.720 394.490 547.925 ;
        RECT 395.330 545.720 395.410 547.925 ;
        RECT 396.250 545.720 396.330 547.925 ;
        RECT 397.170 545.720 397.250 547.925 ;
        RECT 398.090 545.720 398.170 547.925 ;
        RECT 399.010 545.720 399.090 547.925 ;
        RECT 399.930 545.720 400.010 547.925 ;
        RECT 400.850 545.720 400.930 547.925 ;
        RECT 401.770 545.720 401.850 547.925 ;
        RECT 402.690 545.720 402.770 547.925 ;
        RECT 403.610 545.720 403.690 547.925 ;
        RECT 404.530 545.720 404.610 547.925 ;
        RECT 405.450 545.720 405.530 547.925 ;
        RECT 406.370 545.720 406.450 547.925 ;
        RECT 407.290 545.720 407.370 547.925 ;
        RECT 408.210 545.720 408.290 547.925 ;
        RECT 409.130 545.720 409.210 547.925 ;
        RECT 410.050 545.720 410.130 547.925 ;
        RECT 410.970 545.720 411.050 547.925 ;
        RECT 411.890 545.720 411.970 547.925 ;
        RECT 412.810 545.720 412.890 547.925 ;
        RECT 413.730 545.720 413.810 547.925 ;
        RECT 414.650 545.720 414.730 547.925 ;
        RECT 415.570 545.720 415.650 547.925 ;
        RECT 416.490 545.720 416.570 547.925 ;
        RECT 417.410 545.720 417.490 547.925 ;
        RECT 418.330 545.720 418.410 547.925 ;
        RECT 419.250 545.720 419.330 547.925 ;
        RECT 420.170 545.720 420.250 547.925 ;
        RECT 421.090 545.720 421.170 547.925 ;
        RECT 422.010 545.720 422.090 547.925 ;
        RECT 422.930 545.720 423.010 547.925 ;
        RECT 423.850 545.720 423.930 547.925 ;
        RECT 424.770 545.720 424.850 547.925 ;
        RECT 425.690 545.720 425.770 547.925 ;
        RECT 426.610 545.720 426.690 547.925 ;
        RECT 427.530 545.720 427.610 547.925 ;
        RECT 428.450 545.720 428.530 547.925 ;
        RECT 429.370 545.720 429.450 547.925 ;
        RECT 430.290 545.720 430.370 547.925 ;
        RECT 431.210 545.720 431.290 547.925 ;
        RECT 432.130 545.720 432.210 547.925 ;
        RECT 433.050 545.720 433.130 547.925 ;
        RECT 433.970 545.720 434.050 547.925 ;
        RECT 434.890 545.720 434.970 547.925 ;
        RECT 435.810 545.720 435.890 547.925 ;
        RECT 436.730 545.720 436.810 547.925 ;
        RECT 437.650 545.720 437.730 547.925 ;
        RECT 438.570 545.720 438.650 547.925 ;
        RECT 439.490 545.720 439.570 547.925 ;
        RECT 440.410 545.720 440.490 547.925 ;
        RECT 441.330 545.720 441.410 547.925 ;
        RECT 442.250 545.720 442.330 547.925 ;
        RECT 443.170 545.720 443.250 547.925 ;
        RECT 444.090 545.720 444.170 547.925 ;
        RECT 445.010 545.720 445.090 547.925 ;
        RECT 445.930 545.720 446.010 547.925 ;
        RECT 446.850 545.720 446.930 547.925 ;
        RECT 447.770 545.720 447.850 547.925 ;
        RECT 448.690 545.720 448.770 547.925 ;
        RECT 449.610 545.720 449.690 547.925 ;
        RECT 450.530 545.720 450.610 547.925 ;
        RECT 451.450 545.720 451.530 547.925 ;
        RECT 452.370 545.720 452.450 547.925 ;
        RECT 453.290 545.720 453.370 547.925 ;
        RECT 454.210 545.720 454.290 547.925 ;
        RECT 455.130 545.720 455.210 547.925 ;
        RECT 456.050 545.720 456.130 547.925 ;
        RECT 456.970 545.720 457.050 547.925 ;
        RECT 457.890 545.720 457.970 547.925 ;
        RECT 458.810 545.720 458.890 547.925 ;
        RECT 459.730 545.720 459.810 547.925 ;
        RECT 460.650 545.720 460.730 547.925 ;
        RECT 461.570 545.720 461.650 547.925 ;
        RECT 462.490 545.720 462.570 547.925 ;
        RECT 463.410 545.720 463.490 547.925 ;
        RECT 464.330 545.720 464.410 547.925 ;
        RECT 465.250 545.720 465.330 547.925 ;
        RECT 466.170 545.720 466.250 547.925 ;
        RECT 467.090 545.720 467.170 547.925 ;
        RECT 468.010 545.720 468.090 547.925 ;
        RECT 468.930 545.720 469.010 547.925 ;
        RECT 469.850 545.720 469.930 547.925 ;
        RECT 470.770 545.720 470.850 547.925 ;
        RECT 471.690 545.720 471.770 547.925 ;
        RECT 472.610 545.720 472.690 547.925 ;
        RECT 473.530 545.720 473.610 547.925 ;
        RECT 474.450 545.720 474.530 547.925 ;
        RECT 475.370 545.720 475.450 547.925 ;
        RECT 476.290 545.720 476.370 547.925 ;
        RECT 477.210 545.720 477.290 547.925 ;
        RECT 478.130 545.720 478.210 547.925 ;
        RECT 479.050 545.720 479.130 547.925 ;
        RECT 479.970 545.720 480.050 547.925 ;
        RECT 480.890 545.720 480.970 547.925 ;
        RECT 481.810 545.720 481.890 547.925 ;
        RECT 482.730 545.720 482.810 547.925 ;
        RECT 483.650 545.720 483.730 547.925 ;
        RECT 484.570 545.720 484.650 547.925 ;
        RECT 485.490 545.720 485.570 547.925 ;
        RECT 486.410 545.720 486.490 547.925 ;
        RECT 487.330 545.720 487.410 547.925 ;
        RECT 488.250 545.720 488.330 547.925 ;
        RECT 489.170 545.720 489.250 547.925 ;
        RECT 490.090 545.720 490.170 547.925 ;
        RECT 491.010 545.720 491.090 547.925 ;
        RECT 491.930 545.720 492.010 547.925 ;
        RECT 492.850 545.720 492.930 547.925 ;
        RECT 493.770 545.720 493.850 547.925 ;
        RECT 494.690 545.720 494.770 547.925 ;
        RECT 495.610 545.720 495.690 547.925 ;
        RECT 496.530 545.720 496.610 547.925 ;
        RECT 497.450 545.720 497.530 547.925 ;
        RECT 498.370 545.720 498.450 547.925 ;
        RECT 499.290 545.720 499.370 547.925 ;
        RECT 500.210 545.720 500.290 547.925 ;
        RECT 501.130 545.720 501.210 547.925 ;
        RECT 502.050 545.720 502.130 547.925 ;
        RECT 502.970 545.720 503.050 547.925 ;
        RECT 503.890 545.720 503.970 547.925 ;
        RECT 504.810 545.720 504.890 547.925 ;
        RECT 505.730 545.720 505.810 547.925 ;
        RECT 506.650 545.720 506.730 547.925 ;
        RECT 507.570 545.720 507.650 547.925 ;
        RECT 508.490 545.720 508.570 547.925 ;
        RECT 509.410 545.720 509.490 547.925 ;
        RECT 510.330 545.720 510.410 547.925 ;
        RECT 511.250 545.720 511.330 547.925 ;
        RECT 512.170 545.720 512.250 547.925 ;
        RECT 513.090 545.720 513.170 547.925 ;
        RECT 514.010 545.720 514.090 547.925 ;
        RECT 514.930 545.720 515.010 547.925 ;
        RECT 515.850 545.720 515.930 547.925 ;
        RECT 516.770 545.720 516.850 547.925 ;
        RECT 517.690 545.720 517.770 547.925 ;
        RECT 518.610 545.720 518.690 547.925 ;
        RECT 519.530 545.720 519.610 547.925 ;
        RECT 520.450 545.720 520.530 547.925 ;
        RECT 521.370 545.720 521.450 547.925 ;
        RECT 522.290 545.720 522.370 547.925 ;
        RECT 523.210 545.720 523.290 547.925 ;
        RECT 524.130 545.720 524.210 547.925 ;
        RECT 525.050 545.720 525.130 547.925 ;
        RECT 525.970 545.720 526.050 547.925 ;
        RECT 526.890 545.720 526.970 547.925 ;
        RECT 527.810 545.720 527.890 547.925 ;
        RECT 528.730 545.720 528.810 547.925 ;
        RECT 529.650 545.720 529.730 547.925 ;
        RECT 530.570 545.720 530.650 547.925 ;
        RECT 531.490 545.720 531.570 547.925 ;
        RECT 532.410 545.720 532.490 547.925 ;
        RECT 533.330 545.720 533.410 547.925 ;
        RECT 534.250 545.720 534.330 547.925 ;
        RECT 535.170 545.720 535.250 547.925 ;
        RECT 536.090 545.720 536.170 547.925 ;
        RECT 537.010 545.720 537.090 547.925 ;
        RECT 537.930 545.720 538.010 547.925 ;
        RECT 538.850 545.720 538.930 547.925 ;
        RECT 539.770 545.720 539.850 547.925 ;
        RECT 540.690 545.720 540.770 547.925 ;
        RECT 541.610 545.720 541.690 547.925 ;
        RECT 542.530 545.720 542.610 547.925 ;
        RECT 543.450 545.720 543.530 547.925 ;
        RECT 544.370 545.720 544.450 547.925 ;
        RECT 545.290 545.720 545.370 547.925 ;
        RECT 546.210 545.720 546.290 547.925 ;
        RECT 547.130 545.720 547.210 547.925 ;
        RECT 548.050 545.720 548.130 547.925 ;
        RECT 548.970 545.720 549.050 547.925 ;
        RECT 549.890 545.720 549.970 547.925 ;
        RECT 550.810 545.720 550.890 547.925 ;
        RECT 551.730 545.720 551.810 547.925 ;
        RECT 552.650 545.720 552.730 547.925 ;
        RECT 553.570 545.720 553.650 547.925 ;
        RECT 554.490 545.720 554.570 547.925 ;
        RECT 555.410 545.720 555.490 547.925 ;
        RECT 556.330 545.720 556.410 547.925 ;
        RECT 557.250 545.720 557.330 547.925 ;
        RECT 558.170 545.720 558.250 547.925 ;
        RECT 559.090 545.720 559.170 547.925 ;
        RECT 560.010 545.720 560.090 547.925 ;
        RECT 560.930 545.720 561.010 547.925 ;
        RECT 561.850 545.720 561.930 547.925 ;
        RECT 562.770 545.720 562.850 547.925 ;
        RECT 563.690 545.720 563.770 547.925 ;
        RECT 564.610 545.720 564.690 547.925 ;
        RECT 565.530 545.720 565.610 547.925 ;
        RECT 566.450 545.720 566.530 547.925 ;
        RECT 567.370 545.720 567.450 547.925 ;
        RECT 568.290 545.720 568.370 547.925 ;
        RECT 569.210 545.720 569.290 547.925 ;
        RECT 570.130 545.720 570.210 547.925 ;
        RECT 571.050 545.720 571.130 547.925 ;
        RECT 571.970 545.720 572.050 547.925 ;
        RECT 572.890 545.720 572.970 547.925 ;
        RECT 573.810 545.720 573.890 547.925 ;
        RECT 574.730 545.720 574.810 547.925 ;
        RECT 575.650 545.720 575.730 547.925 ;
        RECT 576.570 545.720 576.650 547.925 ;
        RECT 577.490 545.720 577.570 547.925 ;
        RECT 578.410 545.720 578.490 547.925 ;
        RECT 579.330 545.720 579.410 547.925 ;
        RECT 580.250 545.720 580.330 547.925 ;
        RECT 581.170 545.720 581.250 547.925 ;
        RECT 582.090 545.720 582.170 547.925 ;
        RECT 583.010 545.720 583.090 547.925 ;
        RECT 583.930 545.720 584.010 547.925 ;
        RECT 584.850 545.720 584.930 547.925 ;
        RECT 585.770 545.720 585.850 547.925 ;
        RECT 586.690 545.720 586.770 547.925 ;
        RECT 587.610 545.720 587.690 547.925 ;
        RECT 588.530 545.720 588.610 547.925 ;
        RECT 589.450 545.720 589.530 547.925 ;
        RECT 590.370 545.720 590.450 547.925 ;
        RECT 591.290 545.720 591.370 547.925 ;
        RECT 592.210 545.720 592.290 547.925 ;
        RECT 593.130 545.720 593.210 547.925 ;
        RECT 594.050 545.720 594.130 547.925 ;
        RECT 594.970 545.720 595.050 547.925 ;
        RECT 595.890 545.720 595.970 547.925 ;
        RECT 596.810 545.720 596.890 547.925 ;
        RECT 597.730 545.720 597.810 547.925 ;
        RECT 598.650 545.720 598.730 547.925 ;
        RECT 599.570 545.720 599.650 547.925 ;
        RECT 600.490 545.720 600.570 547.925 ;
        RECT 601.410 545.720 601.490 547.925 ;
        RECT 602.330 545.720 602.410 547.925 ;
        RECT 603.250 545.720 603.330 547.925 ;
        RECT 604.170 545.720 604.250 547.925 ;
        RECT 605.090 545.720 605.170 547.925 ;
        RECT 606.010 545.720 606.090 547.925 ;
        RECT 606.930 545.720 607.010 547.925 ;
        RECT 607.850 545.720 607.930 547.925 ;
        RECT 608.770 545.720 608.850 547.925 ;
        RECT 609.690 545.720 609.770 547.925 ;
        RECT 610.610 545.720 610.690 547.925 ;
        RECT 611.530 545.720 611.610 547.925 ;
        RECT 612.450 545.720 612.530 547.925 ;
        RECT 613.370 545.720 613.450 547.925 ;
        RECT 614.290 545.720 614.370 547.925 ;
        RECT 615.210 545.720 615.290 547.925 ;
        RECT 616.130 545.720 616.210 547.925 ;
        RECT 617.050 545.720 617.130 547.925 ;
        RECT 617.970 545.720 618.050 547.925 ;
        RECT 618.890 545.720 618.970 547.925 ;
        RECT 619.810 545.720 619.890 547.925 ;
        RECT 620.730 545.720 620.810 547.925 ;
        RECT 621.650 545.720 621.730 547.925 ;
        RECT 622.570 545.720 622.650 547.925 ;
        RECT 623.490 545.720 623.570 547.925 ;
        RECT 624.410 545.720 624.490 547.925 ;
        RECT 625.330 545.720 625.410 547.925 ;
        RECT 626.250 545.720 626.330 547.925 ;
        RECT 627.170 545.720 627.250 547.925 ;
        RECT 628.090 545.720 628.170 547.925 ;
        RECT 629.010 545.720 629.090 547.925 ;
        RECT 629.930 545.720 630.010 547.925 ;
        RECT 630.850 545.720 630.930 547.925 ;
        RECT 631.770 545.720 631.850 547.925 ;
        RECT 632.690 545.720 632.770 547.925 ;
        RECT 633.610 545.720 633.690 547.925 ;
        RECT 634.530 545.720 634.610 547.925 ;
        RECT 635.450 545.720 635.530 547.925 ;
        RECT 636.370 545.720 636.450 547.925 ;
        RECT 637.290 545.720 637.370 547.925 ;
        RECT 638.210 545.720 638.290 547.925 ;
        RECT 639.130 545.720 639.210 547.925 ;
        RECT 640.050 545.720 640.130 547.925 ;
        RECT 640.970 545.720 641.050 547.925 ;
        RECT 641.890 545.720 641.970 547.925 ;
        RECT 642.810 545.720 642.890 547.925 ;
        RECT 643.730 545.720 643.810 547.925 ;
        RECT 644.650 545.720 644.730 547.925 ;
        RECT 645.570 545.720 645.650 547.925 ;
        RECT 646.490 545.720 646.570 547.925 ;
        RECT 647.410 545.720 647.490 547.925 ;
        RECT 648.330 545.720 648.410 547.925 ;
        RECT 649.250 545.720 649.330 547.925 ;
        RECT 650.170 545.720 650.250 547.925 ;
        RECT 651.090 545.720 651.170 547.925 ;
        RECT 652.010 545.720 652.090 547.925 ;
        RECT 652.930 545.720 653.010 547.925 ;
        RECT 653.850 545.720 653.930 547.925 ;
        RECT 654.770 545.720 654.850 547.925 ;
        RECT 655.690 545.720 655.770 547.925 ;
        RECT 656.610 545.720 656.690 547.925 ;
        RECT 657.530 545.720 657.610 547.925 ;
        RECT 658.450 545.720 658.530 547.925 ;
        RECT 659.370 545.720 659.450 547.925 ;
        RECT 660.290 545.720 660.370 547.925 ;
        RECT 661.210 545.720 661.290 547.925 ;
        RECT 662.130 545.720 662.210 547.925 ;
        RECT 663.050 545.720 663.130 547.925 ;
        RECT 663.970 545.720 664.050 547.925 ;
        RECT 664.890 545.720 664.970 547.925 ;
        RECT 665.810 545.720 665.890 547.925 ;
        RECT 666.730 545.720 666.810 547.925 ;
        RECT 667.650 545.720 667.730 547.925 ;
        RECT 668.570 545.720 668.650 547.925 ;
        RECT 669.490 545.720 669.570 547.925 ;
        RECT 670.410 545.720 670.490 547.925 ;
        RECT 671.330 545.720 671.410 547.925 ;
        RECT 672.250 545.720 672.330 547.925 ;
        RECT 673.170 545.720 673.250 547.925 ;
        RECT 674.090 545.720 674.170 547.925 ;
        RECT 675.010 545.720 675.090 547.925 ;
        RECT 675.930 545.720 676.010 547.925 ;
        RECT 676.850 545.720 676.930 547.925 ;
        RECT 677.770 545.720 677.850 547.925 ;
        RECT 678.690 545.720 678.770 547.925 ;
        RECT 679.610 545.720 679.690 547.925 ;
        RECT 680.530 545.720 680.610 547.925 ;
        RECT 681.450 545.720 681.530 547.925 ;
        RECT 682.370 545.720 682.450 547.925 ;
        RECT 683.290 545.720 683.370 547.925 ;
        RECT 684.210 545.720 684.290 547.925 ;
        RECT 685.130 545.720 685.210 547.925 ;
        RECT 686.050 545.720 686.130 547.925 ;
        RECT 686.970 545.720 687.050 547.925 ;
        RECT 687.890 545.720 687.970 547.925 ;
        RECT 688.810 545.720 688.890 547.925 ;
        RECT 689.730 545.720 689.810 547.925 ;
        RECT 690.650 545.720 690.730 547.925 ;
        RECT 691.570 545.720 691.650 547.925 ;
        RECT 692.490 545.720 692.570 547.925 ;
        RECT 693.410 545.720 693.490 547.925 ;
        RECT 694.330 545.720 694.410 547.925 ;
        RECT 695.250 545.720 695.330 547.925 ;
        RECT 696.170 545.720 696.250 547.925 ;
        RECT 697.090 545.720 697.170 547.925 ;
        RECT 698.010 545.720 698.090 547.925 ;
        RECT 698.930 545.720 699.010 547.925 ;
        RECT 699.850 545.720 699.930 547.925 ;
        RECT 700.770 545.720 700.850 547.925 ;
        RECT 701.690 545.720 701.770 547.925 ;
        RECT 702.610 545.720 702.690 547.925 ;
        RECT 703.530 545.720 703.610 547.925 ;
        RECT 704.450 545.720 704.530 547.925 ;
        RECT 705.370 545.720 705.450 547.925 ;
        RECT 706.290 545.720 706.370 547.925 ;
        RECT 707.210 545.720 707.290 547.925 ;
        RECT 708.130 545.720 708.210 547.925 ;
        RECT 709.050 545.720 709.130 547.925 ;
        RECT 709.970 545.720 710.050 547.925 ;
        RECT 710.890 545.720 710.970 547.925 ;
        RECT 711.810 545.720 711.890 547.925 ;
        RECT 712.730 545.720 712.810 547.925 ;
        RECT 713.650 545.720 713.730 547.925 ;
        RECT 714.570 545.720 714.650 547.925 ;
        RECT 715.490 545.720 715.570 547.925 ;
        RECT 716.410 545.720 716.490 547.925 ;
        RECT 717.330 545.720 717.410 547.925 ;
        RECT 718.250 545.720 718.330 547.925 ;
        RECT 719.170 545.720 719.250 547.925 ;
        RECT 720.090 545.720 720.170 547.925 ;
        RECT 721.010 545.720 721.090 547.925 ;
        RECT 721.930 545.720 722.010 547.925 ;
        RECT 722.850 545.720 722.930 547.925 ;
        RECT 723.770 545.720 723.850 547.925 ;
        RECT 724.690 545.720 724.770 547.925 ;
        RECT 725.610 545.720 725.690 547.925 ;
        RECT 726.530 545.720 726.610 547.925 ;
        RECT 727.450 545.720 727.530 547.925 ;
        RECT 728.370 545.720 728.450 547.925 ;
        RECT 729.290 545.720 729.370 547.925 ;
        RECT 730.210 545.720 730.290 547.925 ;
        RECT 731.130 545.720 731.210 547.925 ;
        RECT 732.050 545.720 732.130 547.925 ;
        RECT 732.970 545.720 733.050 547.925 ;
        RECT 733.890 545.720 733.970 547.925 ;
        RECT 734.810 545.720 734.890 547.925 ;
        RECT 735.730 545.720 735.810 547.925 ;
        RECT 736.650 545.720 736.730 547.925 ;
        RECT 737.570 545.720 737.650 547.925 ;
        RECT 738.490 545.720 738.570 547.925 ;
        RECT 739.410 545.720 739.490 547.925 ;
        RECT 740.330 545.720 740.410 547.925 ;
        RECT 741.250 545.720 741.330 547.925 ;
        RECT 742.170 545.720 742.250 547.925 ;
        RECT 743.090 545.720 743.170 547.925 ;
        RECT 744.010 545.720 794.790 547.925 ;
        RECT 4.690 4.280 794.790 545.720 ;
        RECT 4.690 3.670 39.370 4.280 ;
        RECT 40.210 3.670 42.130 4.280 ;
        RECT 42.970 3.670 44.890 4.280 ;
        RECT 45.730 3.670 47.650 4.280 ;
        RECT 48.490 3.670 50.410 4.280 ;
        RECT 51.250 3.670 53.170 4.280 ;
        RECT 54.010 3.670 55.930 4.280 ;
        RECT 56.770 3.670 58.690 4.280 ;
        RECT 59.530 3.670 61.450 4.280 ;
        RECT 62.290 3.670 64.210 4.280 ;
        RECT 65.050 3.670 66.970 4.280 ;
        RECT 67.810 3.670 69.730 4.280 ;
        RECT 70.570 3.670 72.490 4.280 ;
        RECT 73.330 3.670 75.250 4.280 ;
        RECT 76.090 3.670 78.010 4.280 ;
        RECT 78.850 3.670 80.770 4.280 ;
        RECT 81.610 3.670 83.530 4.280 ;
        RECT 84.370 3.670 86.290 4.280 ;
        RECT 87.130 3.670 89.050 4.280 ;
        RECT 89.890 3.670 91.810 4.280 ;
        RECT 92.650 3.670 94.570 4.280 ;
        RECT 95.410 3.670 97.330 4.280 ;
        RECT 98.170 3.670 100.090 4.280 ;
        RECT 100.930 3.670 102.850 4.280 ;
        RECT 103.690 3.670 105.610 4.280 ;
        RECT 106.450 3.670 108.370 4.280 ;
        RECT 109.210 3.670 111.130 4.280 ;
        RECT 111.970 3.670 113.890 4.280 ;
        RECT 114.730 3.670 116.650 4.280 ;
        RECT 117.490 3.670 119.410 4.280 ;
        RECT 120.250 3.670 122.170 4.280 ;
        RECT 123.010 3.670 124.930 4.280 ;
        RECT 125.770 3.670 127.690 4.280 ;
        RECT 128.530 3.670 130.450 4.280 ;
        RECT 131.290 3.670 133.210 4.280 ;
        RECT 134.050 3.670 135.970 4.280 ;
        RECT 136.810 3.670 138.730 4.280 ;
        RECT 139.570 3.670 141.490 4.280 ;
        RECT 142.330 3.670 144.250 4.280 ;
        RECT 145.090 3.670 147.010 4.280 ;
        RECT 147.850 3.670 149.770 4.280 ;
        RECT 150.610 3.670 152.530 4.280 ;
        RECT 153.370 3.670 155.290 4.280 ;
        RECT 156.130 3.670 158.050 4.280 ;
        RECT 158.890 3.670 160.810 4.280 ;
        RECT 161.650 3.670 163.570 4.280 ;
        RECT 164.410 3.670 166.330 4.280 ;
        RECT 167.170 3.670 169.090 4.280 ;
        RECT 169.930 3.670 171.850 4.280 ;
        RECT 172.690 3.670 174.610 4.280 ;
        RECT 175.450 3.670 177.370 4.280 ;
        RECT 178.210 3.670 180.130 4.280 ;
        RECT 180.970 3.670 182.890 4.280 ;
        RECT 183.730 3.670 185.650 4.280 ;
        RECT 186.490 3.670 188.410 4.280 ;
        RECT 189.250 3.670 191.170 4.280 ;
        RECT 192.010 3.670 193.930 4.280 ;
        RECT 194.770 3.670 196.690 4.280 ;
        RECT 197.530 3.670 199.450 4.280 ;
        RECT 200.290 3.670 202.210 4.280 ;
        RECT 203.050 3.670 204.970 4.280 ;
        RECT 205.810 3.670 207.730 4.280 ;
        RECT 208.570 3.670 210.490 4.280 ;
        RECT 211.330 3.670 213.250 4.280 ;
        RECT 214.090 3.670 216.010 4.280 ;
        RECT 216.850 3.670 218.770 4.280 ;
        RECT 219.610 3.670 221.530 4.280 ;
        RECT 222.370 3.670 224.290 4.280 ;
        RECT 225.130 3.670 227.050 4.280 ;
        RECT 227.890 3.670 229.810 4.280 ;
        RECT 230.650 3.670 232.570 4.280 ;
        RECT 233.410 3.670 235.330 4.280 ;
        RECT 236.170 3.670 238.090 4.280 ;
        RECT 238.930 3.670 240.850 4.280 ;
        RECT 241.690 3.670 243.610 4.280 ;
        RECT 244.450 3.670 246.370 4.280 ;
        RECT 247.210 3.670 249.130 4.280 ;
        RECT 249.970 3.670 251.890 4.280 ;
        RECT 252.730 3.670 254.650 4.280 ;
        RECT 255.490 3.670 257.410 4.280 ;
        RECT 258.250 3.670 260.170 4.280 ;
        RECT 261.010 3.670 262.930 4.280 ;
        RECT 263.770 3.670 265.690 4.280 ;
        RECT 266.530 3.670 268.450 4.280 ;
        RECT 269.290 3.670 271.210 4.280 ;
        RECT 272.050 3.670 273.970 4.280 ;
        RECT 274.810 3.670 276.730 4.280 ;
        RECT 277.570 3.670 279.490 4.280 ;
        RECT 280.330 3.670 282.250 4.280 ;
        RECT 283.090 3.670 285.010 4.280 ;
        RECT 285.850 3.670 287.770 4.280 ;
        RECT 288.610 3.670 290.530 4.280 ;
        RECT 291.370 3.670 293.290 4.280 ;
        RECT 294.130 3.670 296.050 4.280 ;
        RECT 296.890 3.670 298.810 4.280 ;
        RECT 299.650 3.670 301.570 4.280 ;
        RECT 302.410 3.670 304.330 4.280 ;
        RECT 305.170 3.670 307.090 4.280 ;
        RECT 307.930 3.670 309.850 4.280 ;
        RECT 310.690 3.670 312.610 4.280 ;
        RECT 313.450 3.670 315.370 4.280 ;
        RECT 316.210 3.670 318.130 4.280 ;
        RECT 318.970 3.670 320.890 4.280 ;
        RECT 321.730 3.670 323.650 4.280 ;
        RECT 324.490 3.670 326.410 4.280 ;
        RECT 327.250 3.670 329.170 4.280 ;
        RECT 330.010 3.670 331.930 4.280 ;
        RECT 332.770 3.670 334.690 4.280 ;
        RECT 335.530 3.670 337.450 4.280 ;
        RECT 338.290 3.670 340.210 4.280 ;
        RECT 341.050 3.670 342.970 4.280 ;
        RECT 343.810 3.670 345.730 4.280 ;
        RECT 346.570 3.670 348.490 4.280 ;
        RECT 349.330 3.670 351.250 4.280 ;
        RECT 352.090 3.670 354.010 4.280 ;
        RECT 354.850 3.670 356.770 4.280 ;
        RECT 357.610 3.670 359.530 4.280 ;
        RECT 360.370 3.670 362.290 4.280 ;
        RECT 363.130 3.670 365.050 4.280 ;
        RECT 365.890 3.670 367.810 4.280 ;
        RECT 368.650 3.670 370.570 4.280 ;
        RECT 371.410 3.670 373.330 4.280 ;
        RECT 374.170 3.670 376.090 4.280 ;
        RECT 376.930 3.670 378.850 4.280 ;
        RECT 379.690 3.670 381.610 4.280 ;
        RECT 382.450 3.670 384.370 4.280 ;
        RECT 385.210 3.670 387.130 4.280 ;
        RECT 387.970 3.670 389.890 4.280 ;
        RECT 390.730 3.670 392.650 4.280 ;
        RECT 393.490 3.670 395.410 4.280 ;
        RECT 396.250 3.670 398.170 4.280 ;
        RECT 399.010 3.670 400.930 4.280 ;
        RECT 401.770 3.670 403.690 4.280 ;
        RECT 404.530 3.670 406.450 4.280 ;
        RECT 407.290 3.670 409.210 4.280 ;
        RECT 410.050 3.670 411.970 4.280 ;
        RECT 412.810 3.670 414.730 4.280 ;
        RECT 415.570 3.670 417.490 4.280 ;
        RECT 418.330 3.670 420.250 4.280 ;
        RECT 421.090 3.670 423.010 4.280 ;
        RECT 423.850 3.670 425.770 4.280 ;
        RECT 426.610 3.670 428.530 4.280 ;
        RECT 429.370 3.670 431.290 4.280 ;
        RECT 432.130 3.670 434.050 4.280 ;
        RECT 434.890 3.670 436.810 4.280 ;
        RECT 437.650 3.670 439.570 4.280 ;
        RECT 440.410 3.670 442.330 4.280 ;
        RECT 443.170 3.670 445.090 4.280 ;
        RECT 445.930 3.670 447.850 4.280 ;
        RECT 448.690 3.670 450.610 4.280 ;
        RECT 451.450 3.670 453.370 4.280 ;
        RECT 454.210 3.670 456.130 4.280 ;
        RECT 456.970 3.670 458.890 4.280 ;
        RECT 459.730 3.670 461.650 4.280 ;
        RECT 462.490 3.670 464.410 4.280 ;
        RECT 465.250 3.670 467.170 4.280 ;
        RECT 468.010 3.670 469.930 4.280 ;
        RECT 470.770 3.670 472.690 4.280 ;
        RECT 473.530 3.670 475.450 4.280 ;
        RECT 476.290 3.670 478.210 4.280 ;
        RECT 479.050 3.670 480.970 4.280 ;
        RECT 481.810 3.670 483.730 4.280 ;
        RECT 484.570 3.670 486.490 4.280 ;
        RECT 487.330 3.670 489.250 4.280 ;
        RECT 490.090 3.670 492.010 4.280 ;
        RECT 492.850 3.670 494.770 4.280 ;
        RECT 495.610 3.670 497.530 4.280 ;
        RECT 498.370 3.670 500.290 4.280 ;
        RECT 501.130 3.670 503.050 4.280 ;
        RECT 503.890 3.670 505.810 4.280 ;
        RECT 506.650 3.670 508.570 4.280 ;
        RECT 509.410 3.670 511.330 4.280 ;
        RECT 512.170 3.670 514.090 4.280 ;
        RECT 514.930 3.670 516.850 4.280 ;
        RECT 517.690 3.670 519.610 4.280 ;
        RECT 520.450 3.670 522.370 4.280 ;
        RECT 523.210 3.670 525.130 4.280 ;
        RECT 525.970 3.670 527.890 4.280 ;
        RECT 528.730 3.670 530.650 4.280 ;
        RECT 531.490 3.670 533.410 4.280 ;
        RECT 534.250 3.670 536.170 4.280 ;
        RECT 537.010 3.670 538.930 4.280 ;
        RECT 539.770 3.670 541.690 4.280 ;
        RECT 542.530 3.670 544.450 4.280 ;
        RECT 545.290 3.670 547.210 4.280 ;
        RECT 548.050 3.670 549.970 4.280 ;
        RECT 550.810 3.670 552.730 4.280 ;
        RECT 553.570 3.670 555.490 4.280 ;
        RECT 556.330 3.670 558.250 4.280 ;
        RECT 559.090 3.670 561.010 4.280 ;
        RECT 561.850 3.670 563.770 4.280 ;
        RECT 564.610 3.670 566.530 4.280 ;
        RECT 567.370 3.670 569.290 4.280 ;
        RECT 570.130 3.670 572.050 4.280 ;
        RECT 572.890 3.670 574.810 4.280 ;
        RECT 575.650 3.670 577.570 4.280 ;
        RECT 578.410 3.670 580.330 4.280 ;
        RECT 581.170 3.670 583.090 4.280 ;
        RECT 583.930 3.670 585.850 4.280 ;
        RECT 586.690 3.670 588.610 4.280 ;
        RECT 589.450 3.670 591.370 4.280 ;
        RECT 592.210 3.670 594.130 4.280 ;
        RECT 594.970 3.670 596.890 4.280 ;
        RECT 597.730 3.670 599.650 4.280 ;
        RECT 600.490 3.670 602.410 4.280 ;
        RECT 603.250 3.670 605.170 4.280 ;
        RECT 606.010 3.670 607.930 4.280 ;
        RECT 608.770 3.670 610.690 4.280 ;
        RECT 611.530 3.670 613.450 4.280 ;
        RECT 614.290 3.670 616.210 4.280 ;
        RECT 617.050 3.670 618.970 4.280 ;
        RECT 619.810 3.670 621.730 4.280 ;
        RECT 622.570 3.670 624.490 4.280 ;
        RECT 625.330 3.670 627.250 4.280 ;
        RECT 628.090 3.670 630.010 4.280 ;
        RECT 630.850 3.670 632.770 4.280 ;
        RECT 633.610 3.670 635.530 4.280 ;
        RECT 636.370 3.670 638.290 4.280 ;
        RECT 639.130 3.670 641.050 4.280 ;
        RECT 641.890 3.670 643.810 4.280 ;
        RECT 644.650 3.670 646.570 4.280 ;
        RECT 647.410 3.670 649.330 4.280 ;
        RECT 650.170 3.670 652.090 4.280 ;
        RECT 652.930 3.670 654.850 4.280 ;
        RECT 655.690 3.670 657.610 4.280 ;
        RECT 658.450 3.670 660.370 4.280 ;
        RECT 661.210 3.670 663.130 4.280 ;
        RECT 663.970 3.670 665.890 4.280 ;
        RECT 666.730 3.670 668.650 4.280 ;
        RECT 669.490 3.670 671.410 4.280 ;
        RECT 672.250 3.670 674.170 4.280 ;
        RECT 675.010 3.670 676.930 4.280 ;
        RECT 677.770 3.670 679.690 4.280 ;
        RECT 680.530 3.670 682.450 4.280 ;
        RECT 683.290 3.670 685.210 4.280 ;
        RECT 686.050 3.670 687.970 4.280 ;
        RECT 688.810 3.670 690.730 4.280 ;
        RECT 691.570 3.670 693.490 4.280 ;
        RECT 694.330 3.670 696.250 4.280 ;
        RECT 697.090 3.670 699.010 4.280 ;
        RECT 699.850 3.670 701.770 4.280 ;
        RECT 702.610 3.670 704.530 4.280 ;
        RECT 705.370 3.670 707.290 4.280 ;
        RECT 708.130 3.670 710.050 4.280 ;
        RECT 710.890 3.670 712.810 4.280 ;
        RECT 713.650 3.670 715.570 4.280 ;
        RECT 716.410 3.670 718.330 4.280 ;
        RECT 719.170 3.670 721.090 4.280 ;
        RECT 721.930 3.670 723.850 4.280 ;
        RECT 724.690 3.670 726.610 4.280 ;
        RECT 727.450 3.670 729.370 4.280 ;
        RECT 730.210 3.670 732.130 4.280 ;
        RECT 732.970 3.670 734.890 4.280 ;
        RECT 735.730 3.670 737.650 4.280 ;
        RECT 738.490 3.670 740.410 4.280 ;
        RECT 741.250 3.670 743.170 4.280 ;
        RECT 744.010 3.670 745.930 4.280 ;
        RECT 746.770 3.670 748.690 4.280 ;
        RECT 749.530 3.670 751.450 4.280 ;
        RECT 752.290 3.670 754.210 4.280 ;
        RECT 755.050 3.670 756.970 4.280 ;
        RECT 757.810 3.670 759.730 4.280 ;
        RECT 760.570 3.670 794.790 4.280 ;
      LAYER met3 ;
        RECT 3.990 530.080 796.000 549.940 ;
        RECT 3.990 528.680 795.600 530.080 ;
        RECT 3.990 520.560 796.000 528.680 ;
        RECT 4.400 519.160 796.000 520.560 ;
        RECT 3.990 509.680 796.000 519.160 ;
        RECT 3.990 508.280 795.600 509.680 ;
        RECT 3.990 489.280 796.000 508.280 ;
        RECT 3.990 487.880 795.600 489.280 ;
        RECT 3.990 468.880 796.000 487.880 ;
        RECT 3.990 467.480 795.600 468.880 ;
        RECT 3.990 459.360 796.000 467.480 ;
        RECT 4.400 457.960 796.000 459.360 ;
        RECT 3.990 448.480 796.000 457.960 ;
        RECT 3.990 447.080 795.600 448.480 ;
        RECT 3.990 428.080 796.000 447.080 ;
        RECT 3.990 426.680 795.600 428.080 ;
        RECT 3.990 407.680 796.000 426.680 ;
        RECT 3.990 406.280 795.600 407.680 ;
        RECT 3.990 398.160 796.000 406.280 ;
        RECT 4.400 396.760 796.000 398.160 ;
        RECT 3.990 387.280 796.000 396.760 ;
        RECT 3.990 385.880 795.600 387.280 ;
        RECT 3.990 366.880 796.000 385.880 ;
        RECT 3.990 365.480 795.600 366.880 ;
        RECT 3.990 346.480 796.000 365.480 ;
        RECT 3.990 345.080 795.600 346.480 ;
        RECT 3.990 336.960 796.000 345.080 ;
        RECT 4.400 335.560 796.000 336.960 ;
        RECT 3.990 326.080 796.000 335.560 ;
        RECT 3.990 324.680 795.600 326.080 ;
        RECT 3.990 305.680 796.000 324.680 ;
        RECT 3.990 304.280 795.600 305.680 ;
        RECT 3.990 285.280 796.000 304.280 ;
        RECT 3.990 283.880 795.600 285.280 ;
        RECT 3.990 275.760 796.000 283.880 ;
        RECT 4.400 274.360 796.000 275.760 ;
        RECT 3.990 264.880 796.000 274.360 ;
        RECT 3.990 263.480 795.600 264.880 ;
        RECT 3.990 244.480 796.000 263.480 ;
        RECT 3.990 243.080 795.600 244.480 ;
        RECT 3.990 224.080 796.000 243.080 ;
        RECT 3.990 222.680 795.600 224.080 ;
        RECT 3.990 214.560 796.000 222.680 ;
        RECT 4.400 213.160 796.000 214.560 ;
        RECT 3.990 203.680 796.000 213.160 ;
        RECT 3.990 202.280 795.600 203.680 ;
        RECT 3.990 183.280 796.000 202.280 ;
        RECT 3.990 181.880 795.600 183.280 ;
        RECT 3.990 162.880 796.000 181.880 ;
        RECT 3.990 161.480 795.600 162.880 ;
        RECT 3.990 153.360 796.000 161.480 ;
        RECT 4.400 151.960 796.000 153.360 ;
        RECT 3.990 142.480 796.000 151.960 ;
        RECT 3.990 141.080 795.600 142.480 ;
        RECT 3.990 122.080 796.000 141.080 ;
        RECT 3.990 120.680 795.600 122.080 ;
        RECT 3.990 101.680 796.000 120.680 ;
        RECT 3.990 100.280 795.600 101.680 ;
        RECT 3.990 92.160 796.000 100.280 ;
        RECT 4.400 90.760 796.000 92.160 ;
        RECT 3.990 81.280 796.000 90.760 ;
        RECT 3.990 79.880 795.600 81.280 ;
        RECT 3.990 60.880 796.000 79.880 ;
        RECT 3.990 59.480 795.600 60.880 ;
        RECT 3.990 40.480 796.000 59.480 ;
        RECT 3.990 39.080 795.600 40.480 ;
        RECT 3.990 30.960 796.000 39.080 ;
        RECT 4.400 29.560 796.000 30.960 ;
        RECT 3.990 20.080 796.000 29.560 ;
        RECT 3.990 18.680 795.600 20.080 ;
        RECT 3.990 10.715 796.000 18.680 ;
      LAYER met4 ;
        RECT 96.895 549.860 739.385 549.945 ;
        RECT 96.895 13.095 174.240 549.860 ;
        RECT 176.640 13.095 177.540 549.860 ;
        RECT 179.940 13.095 327.840 549.860 ;
        RECT 330.240 13.095 331.140 549.860 ;
        RECT 333.540 13.095 481.440 549.860 ;
        RECT 483.840 13.095 484.740 549.860 ;
        RECT 487.140 13.095 635.040 549.860 ;
        RECT 637.440 13.095 638.340 549.860 ;
        RECT 640.740 13.095 739.385 549.860 ;
  END
END fragment_fifo_m
END LIBRARY

